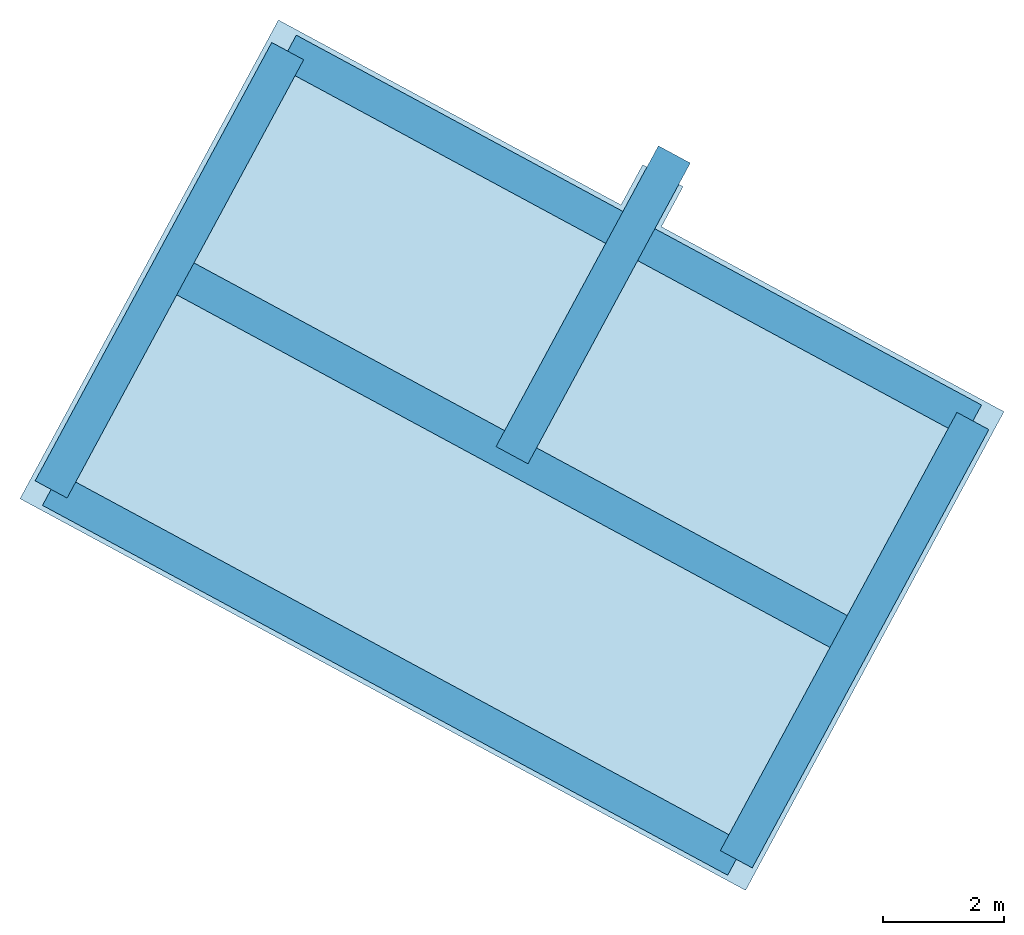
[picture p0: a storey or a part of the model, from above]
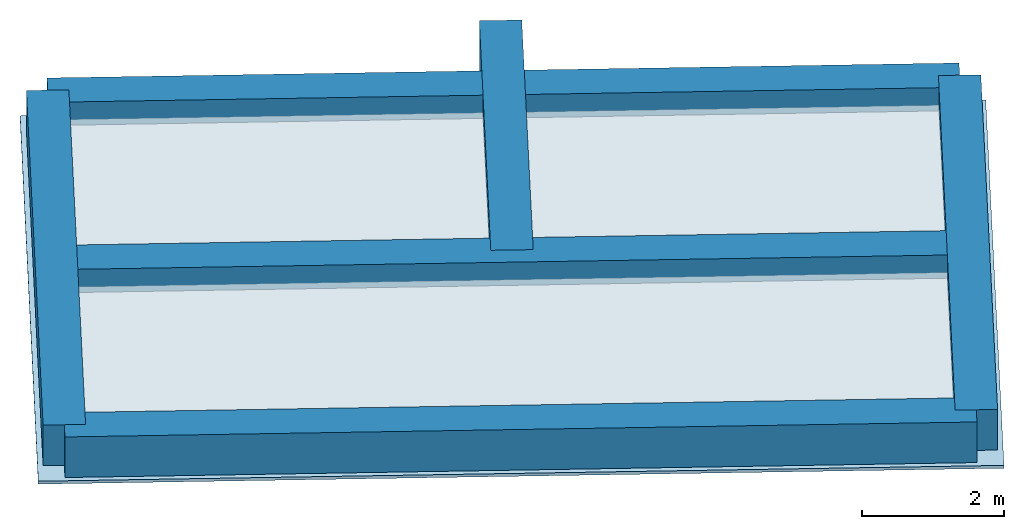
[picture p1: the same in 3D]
Properties of the parts of a building model (IFC2X3), part 1 of 3

# File
Description: ViewDefinition [CoordinationView_V2.0], Option [Elements to export: Visible elements (on all stories)], Option [Partial Structure Display: Entire Model], Option [IFC Domain: All], Option [Structural Function: All Elements], Option [Convert Grid elements: On], Option [Convert IFC Annotations and Archicad 2D elements: Off], Option [Convert 2D symbols of Doors and Windows: Off], Option [Export geometries that Participates in Collision Detection only: Off], Option [Split complex elements: Off], Option [Material Preservation: Never explode], Option [Elements in Solid Element Operations: Extruded/revolved], Option [Elements with junctions: Extruded/revolved without junctions], Option [IFC Model position: Survey Point and Project Origin], Option [Curtain Wall export mode: Single Element], Option [Railing export mode: Single Element], Option [Stair export mode: Single Element], Option [Properties To Export: All properties], Option [Space containment: Off], Option [Geometry to type objects: Off], Option [Element Properties: Off], Option [Building Material Properties: On], Option [Element Parameters: Off], Option [Component Parameters: Off], Option [IFC Base Quantities: Off], Option [Door Window Parameters: On], Option [IFC Space boundaries: Off], Option [Archicad Zone Categories as IFC Space classification data: Off], Option [Element Classifications: On]
File name: I:\_PROJEKT\PQRS\SIWH_18\05_Ausführungsplanung\02 CAD\06 IFC-Modelle\02 TGA\230329\SIWH_18_230329.ifc
Time: 2023-03-29T08:23:47
Author: Kohlrausch Stephan
Organization: Gruppe GME Architekten BDA
Written by: DDS_IFC v3.0
Made in: IFC file generated by Graphisoft Archicad 26.0.0 GER FULL Windows version (IFC add-on version: 4022 GER FULL).
Authorization: Kohlrausch Stephan

# IfcProject, Neubau eines Einfamilienhauses
Description: Katrepeler Landstraße 70A

# IfcSite, Gelände
RefLatitude: 52, 31, 0, 0; RefLongitude: 13, 24, 0, 0; RefElevation: 4.65 m

# IfcBuildingStorey (5)
In: Gebäude
Name | Elevation (m)
Dachaufsicht | 7.905
Staffelgeschoss | 4.55
Erdgeschoss | 0
Gründung | -3.68
Kellergeschoss | -2.98

# IfcBuildingElementProxy: ALLGEMEIN - BAUTEIL (404)
In: Staffelgeschoss
Type - ElementType: SHADING_DEVICE; PredefinedType: USERDEFINED
Classification: Sonnenschutz (Archicad Klassifizierung); Material: ALLGEMEIN - BAUTEIL
Pset_FireRatingProperties - FireResistanceRating: -
AC_Pset_RenovationAndPhasing - Renovation Status: Existing
Material Properties - ALLGEMEIN - BAUTEIL, ThermalConductivity: 0.13; ALLGEMEIN - BAUTEIL, SpecificHeatCapacity: 1600 J/kg/K; ALLGEMEIN - BAUTEIL, MassDensity: 500 kg/m3; ALLGEMEIN - BAUTEIL, Embodied Energy: 13.1 (MJ/kg); ALLGEMEIN - BAUTEIL, Embodied Carbon: 0.64 (kgCO₂/kg); ALLGEMEIN - BAUTEIL, Name: ALLGEMEIN - BAUTEIL; ALLGEMEIN - BAUTEIL, Participates in Collision Detection: yes

# IfcBuildingElementProxy: BO | Dämmung 8+Folie+Estrich 7+Fliese 0,5 | 16cm 170 (8)
In: Staffelgeschoss
Material: Dämmung, hart EPS, Sperrschicht, Folie, Estrich, Kleber, Beton, Leichtbeton
AC_Pset_RenovationAndPhasing - Renovation Status: Existing
Material Properties - Dämmung, hart EPS, ThermalConductivity: 0.042; Dämmung, hart EPS, SpecificHeatCapacity: 1450 J/kg/K; Dämmung, hart EPS, MassDensity: 15 kg/m3; Dämmung, hart EPS, Embodied Energy: 76 (MJ/kg); Dämmung, hart EPS, Embodied Carbon: 3.18 (kgCO₂/kg); Dämmung, hart EPS, Name: Dämmung, hart EPS; Dämmung, hart EPS, Participates in Collision Detection: yes; Sperrschicht, Folie, ThermalConductivity: 0.14; Sperrschicht, Folie, SpecificHeatCapacity: 1000 J/kg/K; Sperrschicht, Folie, MassDensity: 1200 kg/m3; Sperrschicht, Folie, Embodied Energy: 77.2 (MJ/kg); Sperrschicht, Folie, Embodied Carbon: 3.1 (kgCO₂/kg); Sperrschicht, Folie, Name: Sperrschicht, Folie; Sperrschicht, Folie, Participates in Collision Detection: yes; Estrich, ThermalConductivity: 0.8; Estrich, SpecificHeatCapacity: 800 J/kg/K; Estrich, MassDensity: 2300 kg/m3; Estrich, Embodied Energy: 0.92 (MJ/kg); Estrich, Embodied Carbon: 0.15 (kgCO₂/kg); Estrich, Name: Estrich; Estrich, Participates in Collision Detection: yes; Kleber, ThermalConductivity: 0.8; Kleber, SpecificHeatCapacity: 800 J/kg/K; Kleber, MassDensity: 2300 kg/m3; Kleber, Embodied Energy: 0.92 (MJ/kg); Kleber, Embodied Carbon: 0.15 (kgCO₂/kg); Kleber, Name: Kleber; Kleber, Participates in Collision Detection: yes; Beton, Leichtbeton, ThermalConductivity: 0.12; Beton, Leichtbeton, SpecificHeatCapacity: 800 J/kg/K; Beton, Leichtbeton, MassDensity: 450 kg/m3; Beton, Leichtbeton, Embodied Energy: 6.2 (MJ/kg); Beton, Leichtbeton, Embodied Carbon: 0.46 (kgCO₂/kg); Beton, Leichtbeton, Name: Beton, Leichtbeton; Beton, Leichtbeton, Participates in Collision Detection: yes
Name
Decke028
Decke029
Decke041
Decke055
Decke056
Decke057
Decke058
Decke040

# IfcBuildingElementProxy: Gipskarton 15, Decke001
In: Erdgeschoss
Material: Gipskarton
AC_Pset_RenovationAndPhasing - Renovation Status: Existing
Material Properties - Gipskarton, ThermalConductivity: 0.25; Gipskarton, SpecificHeatCapacity: 1000 J/kg/K; Gipskarton, MassDensity: 900 kg/m3; Gipskarton, Embodied Energy: 6.75 (MJ/kg); Gipskarton, Embodied Carbon: 0.39 (kgCO₂/kg); Gipskarton, Name: Gipskarton; Gipskarton, Participates in Collision Detection: yes

# IfcColumn: Beton, Stahlbeton C30/35 D450 (2)
In: Erdgeschoss
Classification: Stütze / Pfeiler (Archicad Klassifizierung); Material: Beton, Stahlbeton C30/35
Pset_ColumnCommon - Slope: 90 deg; FireRating: -; IsExternal: no; LoadBearing: yes; Reference: Beton, Stahlbeton C30/35 D450
AC_Pset_RenovationAndPhasing - Renovation Status: Existing
Material Properties - Beton, Stahlbeton C30/35, ThermalConductivity: 1.35; Beton, Stahlbeton C30/35, SpecificHeatCapacity: 1000 J/kg/K; Beton, Stahlbeton C30/35, MassDensity: 2000 kg/m3; Beton, Stahlbeton C30/35, Embodied Energy: 0.78 (MJ/kg); Beton, Stahlbeton C30/35, Embodied Carbon: 0.113 (kgCO₂/kg); Beton, Stahlbeton C30/35, Name: Beton, Stahlbeton C30/35; Beton, Stahlbeton C30/35, Participates in Collision Detection: yes
Pset_FireRatingProperties - FireResistanceRating: -

# IfcColumn: Metall, Edelstahl D152 (7)
Type - PredefinedType: COLUMN
Classification: Stütze (Archicad Klassifizierung); Material: Metall, Edelstahl
Pset_ColumnCommon - Slope: 90 deg; FireRating: -; IsExternal: no; LoadBearing: yes; Reference: Metall, Edelstahl D152
Pset_FireRatingProperties - FireResistanceRating: -
AC_Pset_RenovationAndPhasing - Renovation Status: Existing
Material Properties - Metall, Edelstahl, ThermalConductivity: 17; Metall, Edelstahl, SpecificHeatCapacity: 460 J/kg/K; Metall, Edelstahl, MassDensity: 7900 kg/m3; Metall, Edelstahl, Embodied Energy: 56.7 (MJ/kg); Metall, Edelstahl, Embodied Carbon: 6.15 (kgCO₂/kg); Metall, Edelstahl, Name: Metall, Edelstahl; Metall, Edelstahl, Participates in Collision Detection: yes
Name | In
4 x Stütze-003 | Erdgeschoss
3 x Stütze-003 | Staffelgeschoss

# IfcColumn: Metall, Edelstahl-Stütze D152 (3)
In: Erdgeschoss
Type - PredefinedType: COLUMN
Classification: Stütze (Archicad Klassifizierung); Material: Metall, Edelstahl-Stütze
Pset_ColumnCommon - Slope: 90 deg; FireRating: -; IsExternal: no; LoadBearing: yes; Reference: Metall, Edelstahl-Stütze D152
Pset_FireRatingProperties - FireResistanceRating: -
Material Properties - Metall, Edelstahl-Stütze, ThermalConductivity: 17; Metall, Edelstahl-Stütze, SpecificHeatCapacity: 460 J/kg/K; Metall, Edelstahl-Stütze, MassDensity: 7900 kg/m3; Metall, Edelstahl-Stütze, Embodied Energy: 56.7 (MJ/kg); Metall, Edelstahl-Stütze, Embodied Carbon: 6.15 (kgCO₂/kg); Metall, Edelstahl-Stütze, Name: Metall, Edelstahl-Stütze; Metall, Edelstahl-Stütze, Participates in Collision Detection: yes
AC_Pset_RenovationAndPhasing - Renovation Status: Existing

# IfcColumn: Metall, Stahl lackiert D152 (7)
In: Staffelgeschoss
Type - PredefinedType: COLUMN
Classification: Stütze (Archicad Klassifizierung); Material: Metall, Stahl lackiert
Pset_ColumnCommon - Slope: 90 deg; FireRating: -; IsExternal: no; LoadBearing: yes; Reference: Metall, Stahl lackiert D152
AC_Pset_RenovationAndPhasing - Renovation Status: Existing
Pset_FireRatingProperties - FireResistanceRating: -
Material Properties - Metall, Stahl lackiert, ThermalConductivity: 50; Metall, Stahl lackiert, SpecificHeatCapacity: 450 J/kg/K; Metall, Stahl lackiert, MassDensity: 7800 kg/m3; Metall, Stahl lackiert, Embodied Energy: 20.1 (MJ/kg); Metall, Stahl lackiert, Embodied Carbon: 1.46 (kgCO₂/kg); Metall, Stahl lackiert, Name: Metall, Stahl lackiert; Metall, Stahl lackiert, Participates in Collision Detection: yes
Name
4 x Stütze-003
3 x Stütze-004

# IfcColumn: _SIWH - Außenstütze1 EG 2395 x 400, Stütze-004
In: Erdgeschoss
Type - PredefinedType: COLUMN
Classification: Stütze (Archicad Klassifizierung); Material: _SIWH - Beton, Stahlbeton
Pset_ColumnCommon - Slope: 90 deg; FireRating: -; IsExternal: yes; LoadBearing: yes; Reference: _SIWH - Außenstütze1 EG 2395 x 400
AC_Pset_RenovationAndPhasing - Renovation Status: Existing
Material Properties - _SIWH - Beton, Stahlbeton, ThermalConductivity: 1.35; _SIWH - Beton, Stahlbeton, SpecificHeatCapacity: 1000 J/kg/K; _SIWH - Beton, Stahlbeton, MassDensity: 2000 kg/m3; _SIWH - Beton, Stahlbeton, Embodied Energy: 0.78 (MJ/kg); _SIWH - Beton, Stahlbeton, Embodied Carbon: 0.113 (kgCO₂/kg); _SIWH - Beton, Stahlbeton, Name: _SIWH - Beton, Stahlbeton; _SIWH - Beton, Stahlbeton, Participates in Collision Detection: yes
Pset_FireRatingProperties - FireResistanceRating: -

# IfcColumn: _SIWH - Beton, Stahlbeton 400 x 2200, Stütze-003
In: Erdgeschoss
Type - PredefinedType: COLUMN
Classification: Stütze (Archicad Klassifizierung); Material: _SIWH - Beton, Stahlbeton
Pset_FireRatingProperties - FireResistanceRating: -
AC_Pset_RenovationAndPhasing - Renovation Status: Existing
Material Properties - _SIWH - Beton, Stahlbeton, ThermalConductivity: 1.35; _SIWH - Beton, Stahlbeton, SpecificHeatCapacity: 1000 J/kg/K; _SIWH - Beton, Stahlbeton, MassDensity: 2000 kg/m3; _SIWH - Beton, Stahlbeton, Embodied Energy: 0.78 (MJ/kg); _SIWH - Beton, Stahlbeton, Embodied Carbon: 0.113 (kgCO₂/kg); _SIWH - Beton, Stahlbeton, Name: _SIWH - Beton, Stahlbeton; _SIWH - Beton, Stahlbeton, Participates in Collision Detection: yes
Pset_ColumnCommon - Slope: 90 deg; FireRating: -; IsExternal: yes; LoadBearing: yes; Reference: _SIWH - Beton, Stahlbeton 400 x 2200

# IfcColumn: _SIWH - Beton, Stahlbeton 400 x 400 (11)
In: Erdgeschoss
Type - PredefinedType: COLUMN
Classification: Stütze (Archicad Klassifizierung); Material: _SIWH - Beton, Stahlbeton
Pset_ColumnCommon - Slope: 90 deg; FireRating: -; IsExternal: yes; LoadBearing: yes; Reference: _SIWH - Beton, Stahlbeton 400 x 400
Pset_FireRatingProperties - FireResistanceRating: -
AC_Pset_RenovationAndPhasing - Renovation Status: Existing
Material Properties - _SIWH - Beton, Stahlbeton, ThermalConductivity: 1.35; _SIWH - Beton, Stahlbeton, SpecificHeatCapacity: 1000 J/kg/K; _SIWH - Beton, Stahlbeton, MassDensity: 2000 kg/m3; _SIWH - Beton, Stahlbeton, Embodied Energy: 0.78 (MJ/kg); _SIWH - Beton, Stahlbeton, Embodied Carbon: 0.113 (kgCO₂/kg); _SIWH - Beton, Stahlbeton, Name: _SIWH - Beton, Stahlbeton; _SIWH - Beton, Stahlbeton, Participates in Collision Detection: yes

# IfcColumn: _SIWH - Luftschicht vertikal D160 (4)
Type - PredefinedType: COLUMN
Classification: Stütze (Archicad Klassifizierung); Material: _SIWH | Metall, Stahl lackiert, _SIWH - Luftschicht vertikal
Pset_ColumnCommon - Slope: 90 deg; FireRating: -; IsExternal: no; LoadBearing: yes; Reference: _SIWH - Luftschicht vertikal D160
Pset_FireRatingProperties - FireResistanceRating: -
AC_Pset_RenovationAndPhasing - Renovation Status: Existing
Material Properties - _SIWH | Metall, Stahl lackiert, ThermalConductivity: 50; _SIWH | Metall, Stahl lackiert, SpecificHeatCapacity: 450 J/kg/K; _SIWH | Metall, Stahl lackiert, MassDensity: 7800 kg/m3; _SIWH | Metall, Stahl lackiert, Embodied Energy: 20.1 (MJ/kg); _SIWH | Metall, Stahl lackiert, Embodied Carbon: 1.46 (kgCO₂/kg); _SIWH | Metall, Stahl lackiert, Name: _SIWH | Metall, Stahl lackiert; _SIWH | Metall, Stahl lackiert, Participates in Collision Detection: yes; _SIWH - Luftschicht vertikal, ThermalConductivity: 0.16; _SIWH - Luftschicht vertikal, SpecificHeatCapacity: 1008 J/kg/K; _SIWH - Luftschicht vertikal, MassDensity: 1.2 kg/m3; _SIWH - Luftschicht vertikal, Embodied Energy: 0 (MJ/kg); _SIWH - Luftschicht vertikal, Embodied Carbon: 0 (kgCO₂/kg); _SIWH - Luftschicht vertikal, Name: _SIWH - Luftschicht vertikal; _SIWH - Luftschicht vertikal, Participates in Collision Detection: no
Name | In
2 x Stütze-003 | Erdgeschoss
2 x Stütze-003 | Staffelgeschoss

# IfcCovering: ALLGEMEIN - BAUTEIL 50, I-Wand036
In: Staffelgeschoss
Type - PredefinedType: CLADDING
Classification: Verkleidung (Archicad Klassifizierung); Material: ALLGEMEIN - BAUTEIL
Pset_CoveringCommon - FireRating: -; Material: ALLGEMEIN - BAUTEIL; TotalThickness: 0.05 m
Pset_FireRatingProperties - FireResistanceRating: -
Material Properties - ALLGEMEIN - BAUTEIL, ThermalConductivity: 0.13; ALLGEMEIN - BAUTEIL, SpecificHeatCapacity: 1600 J/kg/K; ALLGEMEIN - BAUTEIL, MassDensity: 500 kg/m3; ALLGEMEIN - BAUTEIL, Embodied Energy: 13.1 (MJ/kg); ALLGEMEIN - BAUTEIL, Embodied Carbon: 0.64 (kgCO₂/kg); ALLGEMEIN - BAUTEIL, Name: ALLGEMEIN - BAUTEIL; ALLGEMEIN - BAUTEIL, Participates in Collision Detection: yes
AC_Pset_RenovationAndPhasing - Renovation Status: Existing

# IfcCovering: Dämmung, hart Mineralwolle (6)
Type - PredefinedType: INSULATION
Classification: Dämmung (Archicad Klassifizierung); Material: Dämmung, hart Mineralwolle
Pset_CoveringCommon - FireRating: -; Material: Dämmung, hart Mineralwolle
Pset_FireRatingProperties - FireResistanceRating: -
AC_Pset_RenovationAndPhasing - Renovation Status: Existing
Material Properties - Dämmung, hart Mineralwolle, ThermalConductivity: 0.036; Dämmung, hart Mineralwolle, SpecificHeatCapacity: 840 J/kg/K; Dämmung, hart Mineralwolle, MassDensity: 115 kg/m3; Dämmung, hart Mineralwolle, Embodied Energy: 21.4 (MJ/kg); Dämmung, hart Mineralwolle, Embodied Carbon: 1.69 (kgCO₂/kg); Dämmung, hart Mineralwolle, Name: Dämmung, hart Mineralwolle; Dämmung, hart Mineralwolle, Participates in Collision Detection: yes
Name | In
4 x Freifläche-006 | Staffelgeschoss
Freifläche-005 | Staffelgeschoss
Freifläche-004 | Dachaufsicht

# IfcCovering: Gipskarton 15 (2)
Type - PredefinedType: CEILING
Classification: Abgehängte Decke / Deckenbekleidung (Archicad Klassifizierung); Material: Gipskarton
Pset_CoveringCommon - FireRating: -; Material: Gipskarton; TotalThickness: 0.015 m
Pset_FireRatingProperties - FireResistanceRating: -
AC_Pset_RenovationAndPhasing - Renovation Status: Existing
Material Properties - Gipskarton, ThermalConductivity: 0.25; Gipskarton, SpecificHeatCapacity: 1000 J/kg/K; Gipskarton, MassDensity: 900 kg/m3; Gipskarton, Embodied Energy: 6.75 (MJ/kg); Gipskarton, Embodied Carbon: 0.39 (kgCO₂/kg); Gipskarton, Name: Gipskarton; Gipskarton, Participates in Collision Detection: yes
Name | In
Decke007 | Erdgeschoss
Decke002 | Staffelgeschoss

# IfcCovering: Holz, Treppenstufe 966, Decke000
In: Erdgeschoss
Type - PredefinedType: FLOORING
Classification: Fußbodenaufbau (Archicad Klassifizierung); Material: Holz, Treppenstufe
Pset_CoveringCommon - FireRating: -; Material: Holz, Treppenstufe; TotalThickness: 0.965504 m
Pset_FireRatingProperties - FireResistanceRating: -
Material Properties - Holz, Treppenstufe, ThermalConductivity: 0.09; Holz, Treppenstufe, SpecificHeatCapacity: 1600 J/kg/K; Holz, Treppenstufe, MassDensity: 300 kg/m3; Holz, Treppenstufe, Embodied Energy: 11.9 (MJ/kg); Holz, Treppenstufe, Embodied Carbon: 0.52 (kgCO₂/kg); Holz, Treppenstufe, Name: Holz, Treppenstufe; Holz, Treppenstufe, Participates in Collision Detection: yes
AC_Pset_RenovationAndPhasing - Renovation Status: Existing

# IfcCovering: _SIWH - Abgehängte Decke Arkade 25 (2)
In: Erdgeschoss
Type - PredefinedType: CEILING
Classification: Abgehängte Decke / Deckenbekleidung (Archicad Klassifizierung); Material: _SIWH - Abgehängte Decke Arkade
Pset_CoveringCommon - FireRating: -; Material: _SIWH - Abgehängte Decke Arkade; TotalThickness: 0.025 m
Pset_FireRatingProperties - FireResistanceRating: -
AC_Pset_RenovationAndPhasing - Renovation Status: Existing
Material Properties - _SIWH - Abgehängte Decke Arkade, ThermalConductivity: 0.13; _SIWH - Abgehängte Decke Arkade, SpecificHeatCapacity: 1600 J/kg/K; _SIWH - Abgehängte Decke Arkade, MassDensity: 500 kg/m3; _SIWH - Abgehängte Decke Arkade, Embodied Energy: 13.1 (MJ/kg); _SIWH - Abgehängte Decke Arkade, Embodied Carbon: 0.64 (kgCO₂/kg); _SIWH - Abgehängte Decke Arkade, Name: _SIWH - Abgehängte Decke Arkade; _SIWH - Abgehängte Decke Arkade, Participates in Collision Detection: yes
Name
Decke016
Decke015

# IfcCovering: _SIWH - Attika1 Achse3 EG 440 x 865, A-Wand054
In: Staffelgeschoss
Type - PredefinedType: INSULATION
Classification: Dämmung (Archicad Klassifizierung); Material: _SIWH - Dämmung, weich Mineralwolle, _SIWH - Dämmung, hart Mineralwolle
Pset_CoveringCommon - FireRating: -; Material: _SIWH - Attika1 Achse3 EG; TotalThickness: 0.44 m
Pset_FireRatingProperties - FireResistanceRating: -
AC_Pset_RenovationAndPhasing - Renovation Status: Existing
Material Properties - _SIWH - Dämmung, weich Mineralwolle, ThermalConductivity: 0.037; _SIWH - Dämmung, weich Mineralwolle, SpecificHeatCapacity: 840 J/kg/K; _SIWH - Dämmung, weich Mineralwolle, MassDensity: 40 kg/m3; _SIWH - Dämmung, weich Mineralwolle, Embodied Energy: 14.3 (MJ/kg); _SIWH - Dämmung, weich Mineralwolle, Embodied Carbon: 1.08 (kgCO₂/kg); _SIWH - Dämmung, weich Mineralwolle, Name: _SIWH - Dämmung, weich Mineralwolle; _SIWH - Dämmung, weich Mineralwolle, Participates in Collision Detection: yes; _SIWH - Dämmung, hart Mineralwolle, ThermalConductivity: 0.036; _SIWH - Dämmung, hart Mineralwolle, SpecificHeatCapacity: 840 J/kg/K; _SIWH - Dämmung, hart Mineralwolle, MassDensity: 115 kg/m3; _SIWH - Dämmung, hart Mineralwolle, Embodied Energy: 21.4 (MJ/kg); _SIWH - Dämmung, hart Mineralwolle, Embodied Carbon: 1.69 (kgCO₂/kg); _SIWH - Dämmung, hart Mineralwolle, Name: _SIWH - Dämmung, hart Mineralwolle; _SIWH - Dämmung, hart Mineralwolle, Participates in Collision Detection: yes

# IfcCovering: _SIWH - Attika1 AchseB EG 440 x 865 (2)
In: Staffelgeschoss
Type - PredefinedType: INSULATION
Classification: Dämmung (Archicad Klassifizierung); Material: _SIWH - Dämmung, weich Mineralwolle, _SIWH - Dämmung, hart Mineralwolle
Pset_CoveringCommon - FireRating: -; Material: _SIWH - Attika1 AchseB EG; TotalThickness: 0.44 m
Pset_FireRatingProperties - FireResistanceRating: -
AC_Pset_RenovationAndPhasing - Renovation Status: Existing
Material Properties - _SIWH - Dämmung, weich Mineralwolle, ThermalConductivity: 0.037; _SIWH - Dämmung, weich Mineralwolle, SpecificHeatCapacity: 840 J/kg/K; _SIWH - Dämmung, weich Mineralwolle, MassDensity: 40 kg/m3; _SIWH - Dämmung, weich Mineralwolle, Embodied Energy: 14.3 (MJ/kg); _SIWH - Dämmung, weich Mineralwolle, Embodied Carbon: 1.08 (kgCO₂/kg); _SIWH - Dämmung, weich Mineralwolle, Name: _SIWH - Dämmung, weich Mineralwolle; _SIWH - Dämmung, weich Mineralwolle, Participates in Collision Detection: yes; _SIWH - Dämmung, hart Mineralwolle, ThermalConductivity: 0.036; _SIWH - Dämmung, hart Mineralwolle, SpecificHeatCapacity: 840 J/kg/K; _SIWH - Dämmung, hart Mineralwolle, MassDensity: 115 kg/m3; _SIWH - Dämmung, hart Mineralwolle, Embodied Energy: 21.4 (MJ/kg); _SIWH - Dämmung, hart Mineralwolle, Embodied Carbon: 1.69 (kgCO₂/kg); _SIWH - Dämmung, hart Mineralwolle, Name: _SIWH - Dämmung, hart Mineralwolle; _SIWH - Dämmung, hart Mineralwolle, Participates in Collision Detection: yes
Name
A-Wand057
A-Wand059

# IfcCovering: _SIWH - Attika2 Achse3 EG 440 x 585, A-Wand056
In: Staffelgeschoss
Type - PredefinedType: INSULATION
Classification: Dämmung (Archicad Klassifizierung); Material: _SIWH - Dämmung, weich Mineralwolle, _SIWH - Dämmung, hart Mineralwolle
Pset_CoveringCommon - FireRating: -; Material: _SIWH - Attika2 Achse3 EG; TotalThickness: 0.44 m
Pset_FireRatingProperties - FireResistanceRating: -
AC_Pset_RenovationAndPhasing - Renovation Status: Existing
Material Properties - _SIWH - Dämmung, weich Mineralwolle, ThermalConductivity: 0.037; _SIWH - Dämmung, weich Mineralwolle, SpecificHeatCapacity: 840 J/kg/K; _SIWH - Dämmung, weich Mineralwolle, MassDensity: 40 kg/m3; _SIWH - Dämmung, weich Mineralwolle, Embodied Energy: 14.3 (MJ/kg); _SIWH - Dämmung, weich Mineralwolle, Embodied Carbon: 1.08 (kgCO₂/kg); _SIWH - Dämmung, weich Mineralwolle, Name: _SIWH - Dämmung, weich Mineralwolle; _SIWH - Dämmung, weich Mineralwolle, Participates in Collision Detection: yes; _SIWH - Dämmung, hart Mineralwolle, ThermalConductivity: 0.036; _SIWH - Dämmung, hart Mineralwolle, SpecificHeatCapacity: 840 J/kg/K; _SIWH - Dämmung, hart Mineralwolle, MassDensity: 115 kg/m3; _SIWH - Dämmung, hart Mineralwolle, Embodied Energy: 21.4 (MJ/kg); _SIWH - Dämmung, hart Mineralwolle, Embodied Carbon: 1.69 (kgCO₂/kg); _SIWH - Dämmung, hart Mineralwolle, Name: _SIWH - Dämmung, hart Mineralwolle; _SIWH - Dämmung, hart Mineralwolle, Participates in Collision Detection: yes

# IfcCovering: _SIWH - Attika3 Achse3 EG 260 x 385, A-Wand055
In: Staffelgeschoss
Type - PredefinedType: INSULATION
Classification: Dämmung (Archicad Klassifizierung); Material: _SIWH - Dämmung, hart Mineralwolle
Pset_CoveringCommon - FireRating: -; Material: _SIWH - Attika3 Achse3 EG; TotalThickness: 0.26 m
Pset_FireRatingProperties - FireResistanceRating: -
AC_Pset_RenovationAndPhasing - Renovation Status: Existing
Material Properties - _SIWH - Dämmung, hart Mineralwolle, ThermalConductivity: 0.036; _SIWH - Dämmung, hart Mineralwolle, SpecificHeatCapacity: 840 J/kg/K; _SIWH - Dämmung, hart Mineralwolle, MassDensity: 115 kg/m3; _SIWH - Dämmung, hart Mineralwolle, Embodied Energy: 21.4 (MJ/kg); _SIWH - Dämmung, hart Mineralwolle, Embodied Carbon: 1.69 (kgCO₂/kg); _SIWH - Dämmung, hart Mineralwolle, Name: _SIWH - Dämmung, hart Mineralwolle; _SIWH - Dämmung, hart Mineralwolle, Participates in Collision Detection: yes

# IfcCovering: _SIWH - Attika4 Achse3 EG 320 x 385, A-Wand058
In: Staffelgeschoss
Type - PredefinedType: INSULATION
Classification: Dämmung (Archicad Klassifizierung); Material: _SIWH - Dämmung, hart Mineralwolle
Pset_CoveringCommon - FireRating: -; Material: _SIWH - Attika4 Achse3 EG; TotalThickness: 0.32 m
Pset_FireRatingProperties - FireResistanceRating: -
AC_Pset_RenovationAndPhasing - Renovation Status: Existing
Material Properties - _SIWH - Dämmung, hart Mineralwolle, ThermalConductivity: 0.036; _SIWH - Dämmung, hart Mineralwolle, SpecificHeatCapacity: 840 J/kg/K; _SIWH - Dämmung, hart Mineralwolle, MassDensity: 115 kg/m3; _SIWH - Dämmung, hart Mineralwolle, Embodied Energy: 21.4 (MJ/kg); _SIWH - Dämmung, hart Mineralwolle, Embodied Carbon: 1.69 (kgCO₂/kg); _SIWH - Dämmung, hart Mineralwolle, Name: _SIWH - Dämmung, hart Mineralwolle; _SIWH - Dämmung, hart Mineralwolle, Participates in Collision Detection: yes

# IfcCovering: _SIWH - Attikablech1 Achse3+B EG 660 x 115 (2)
In: Staffelgeschoss
Type - PredefinedType: ROOFING
Classification: Dachdeckung (Archicad Klassifizierung); Material: _SIWH - Holz, Bauholz, _SIWH - Metall, Aluminium
Pset_FireRatingProperties - FireResistanceRating: -
AC_Pset_RenovationAndPhasing - Renovation Status: Existing
Material Properties - _SIWH - Holz, Bauholz, ThermalConductivity: 0.13; _SIWH - Holz, Bauholz, SpecificHeatCapacity: 1600 J/kg/K; _SIWH - Holz, Bauholz, MassDensity: 500 kg/m3; _SIWH - Holz, Bauholz, Embodied Energy: 6.95 (MJ/kg); _SIWH - Holz, Bauholz, Embodied Carbon: 0.29 (kgCO₂/kg); _SIWH - Holz, Bauholz, Name: _SIWH - Holz, Bauholz; _SIWH - Holz, Bauholz, Participates in Collision Detection: yes; _SIWH - Metall, Aluminium, ThermalConductivity: 160; _SIWH - Metall, Aluminium, SpecificHeatCapacity: 880 J/kg/K; _SIWH - Metall, Aluminium, MassDensity: 2800 kg/m3; _SIWH - Metall, Aluminium, Embodied Energy: 155 (MJ/kg); _SIWH - Metall, Aluminium, Embodied Carbon: 9.16 (kgCO₂/kg); _SIWH - Metall, Aluminium, Name: _SIWH - Metall, Aluminium; _SIWH - Metall, Aluminium, Participates in Collision Detection: yes
Pset_CoveringCommon - FireRating: -; Material: _SIWH - Attikablech1 Achse3+B EG; TotalThickness: 0.66 m

# IfcCovering: _SIWH - Attikablech3 Achse3+4' EG 380 x 92 (2)
In: Staffelgeschoss
Type - PredefinedType: ROOFING
Classification: Dachdeckung (Archicad Klassifizierung); Material: _SIWH - Holz, Bauholz, _SIWH - Metall, Aluminium
Pset_CoveringCommon - FireRating: -; Material: _SIWH - Attikablech3 Achse3+4' EG; TotalThickness: 0.38 m
Pset_FireRatingProperties - FireResistanceRating: -
AC_Pset_RenovationAndPhasing - Renovation Status: Existing
Material Properties - _SIWH - Holz, Bauholz, ThermalConductivity: 0.13; _SIWH - Holz, Bauholz, SpecificHeatCapacity: 1600 J/kg/K; _SIWH - Holz, Bauholz, MassDensity: 500 kg/m3; _SIWH - Holz, Bauholz, Embodied Energy: 6.95 (MJ/kg); _SIWH - Holz, Bauholz, Embodied Carbon: 0.29 (kgCO₂/kg); _SIWH - Holz, Bauholz, Name: _SIWH - Holz, Bauholz; _SIWH - Holz, Bauholz, Participates in Collision Detection: yes; _SIWH - Metall, Aluminium, ThermalConductivity: 160; _SIWH - Metall, Aluminium, SpecificHeatCapacity: 880 J/kg/K; _SIWH - Metall, Aluminium, MassDensity: 2800 kg/m3; _SIWH - Metall, Aluminium, Embodied Energy: 155 (MJ/kg); _SIWH - Metall, Aluminium, Embodied Carbon: 9.16 (kgCO₂/kg); _SIWH - Metall, Aluminium, Name: _SIWH - Metall, Aluminium; _SIWH - Metall, Aluminium, Participates in Collision Detection: yes

# IfcCovering: _SIWH - Außendämmung Wand KG 230 x 2305, Unterzug-015
In: Kellergeschoss
Type - PredefinedType: INSULATION
Classification: Dämmung (Archicad Klassifizierung); Material: _SIWH - Dämmung, Perimeterdämmung (3)
Pset_CoveringCommon - FireRating: -; Material: _SIWH - Außendämmung Wand KG
Pset_FireRatingProperties - FireResistanceRating: -
Material Properties - _SIWH - Dämmung, Perimeterdämmung, ThermalConductivity: 0.046; _SIWH - Dämmung, Perimeterdämmung, SpecificHeatCapacity: 900 J/kg/K; _SIWH - Dämmung, Perimeterdämmung, MassDensity: 151.33 kg/m3; _SIWH - Dämmung, Perimeterdämmung, Embodied Energy: 13.5 (MJ/kg); _SIWH - Dämmung, Perimeterdämmung, Embodied Carbon: 0.9 (kgCO₂/kg); _SIWH - Dämmung, Perimeterdämmung, Name: _SIWH - Dämmung, Perimeterdämmung; _SIWH - Dämmung, Perimeterdämmung, Participates in Collision Detection: yes
AC_Pset_RenovationAndPhasing - Renovation Status: Existing

# IfcCovering: _SIWH - Außendämmung Wand KG 230 x 3250 (2)
In: Kellergeschoss
Type - PredefinedType: INSULATION
Classification: Dämmung (Archicad Klassifizierung); Material: _SIWH - Dämmung, Perimeterdämmung (3)
Pset_CoveringCommon - FireRating: -; Material: _SIWH - Außendämmung Wand KG
Pset_FireRatingProperties - FireResistanceRating: -
AC_Pset_RenovationAndPhasing - Renovation Status: Existing
Material Properties - _SIWH - Dämmung, Perimeterdämmung, ThermalConductivity: 0.046; _SIWH - Dämmung, Perimeterdämmung, SpecificHeatCapacity: 900 J/kg/K; _SIWH - Dämmung, Perimeterdämmung, MassDensity: 151.33 kg/m3; _SIWH - Dämmung, Perimeterdämmung, Embodied Energy: 13.5 (MJ/kg); _SIWH - Dämmung, Perimeterdämmung, Embodied Carbon: 0.9 (kgCO₂/kg); _SIWH - Dämmung, Perimeterdämmung, Name: _SIWH - Dämmung, Perimeterdämmung; _SIWH - Dämmung, Perimeterdämmung, Participates in Collision Detection: yes
Name
Unterzug-016
Unterzug-015

# IfcCovering: _SIWH - Außendämmung Wand KG 230 x 3500 (8)
In: Kellergeschoss
Type - PredefinedType: INSULATION
Classification: Dämmung (Archicad Klassifizierung); Material: _SIWH - Dämmung, Perimeterdämmung (3)
Pset_CoveringCommon - FireRating: -; Material: _SIWH - Außendämmung Wand KG
Pset_FireRatingProperties - FireResistanceRating: -
AC_Pset_RenovationAndPhasing - Renovation Status: Existing
Material Properties - _SIWH - Dämmung, Perimeterdämmung, ThermalConductivity: 0.046; _SIWH - Dämmung, Perimeterdämmung, SpecificHeatCapacity: 900 J/kg/K; _SIWH - Dämmung, Perimeterdämmung, MassDensity: 151.33 kg/m3; _SIWH - Dämmung, Perimeterdämmung, Embodied Energy: 13.5 (MJ/kg); _SIWH - Dämmung, Perimeterdämmung, Embodied Carbon: 0.9 (kgCO₂/kg); _SIWH - Dämmung, Perimeterdämmung, Name: _SIWH - Dämmung, Perimeterdämmung; _SIWH - Dämmung, Perimeterdämmung, Participates in Collision Detection: yes
Name
5 x Unterzug-015
2 x Unterzug-017
Unterzug-016

# IfcCovering: _SIWH - BO | EG 180, Decke008
In: Erdgeschoss
Type - PredefinedType: FLOORING
Classification: Fußbodenaufbau (Archicad Klassifizierung); Material: ALLGEMEIN - BAUTEIL
Pset_CoveringCommon - FireRating: -; Material: _SIWH - BO | EG; TotalThickness: 0.18 m
Pset_FireRatingProperties - FireResistanceRating: -
AC_Pset_RenovationAndPhasing - Renovation Status: Existing
Material Properties - ALLGEMEIN - BAUTEIL, ThermalConductivity: 0.13; ALLGEMEIN - BAUTEIL, SpecificHeatCapacity: 1600 J/kg/K; ALLGEMEIN - BAUTEIL, MassDensity: 500 kg/m3; ALLGEMEIN - BAUTEIL, Embodied Energy: 13.1 (MJ/kg); ALLGEMEIN - BAUTEIL, Embodied Carbon: 0.64 (kgCO₂/kg); ALLGEMEIN - BAUTEIL, Name: ALLGEMEIN - BAUTEIL; ALLGEMEIN - BAUTEIL, Participates in Collision Detection: yes

# IfcCovering: _SIWH - BO | Perimeterdämmung 10 | 10cm 100 (3)
In: Gründung
Type - PredefinedType: INSULATION
Classification: Dämmung (Archicad Klassifizierung); Material: _SIWH - Dämmung, Perimeterdämmung
Pset_CoveringCommon - FireRating: -; Material: _SIWH - BO | Perimeterdämmung 10 | 10cm; TotalThickness: 0.1 m
Pset_FireRatingProperties - FireResistanceRating: -
AC_Pset_RenovationAndPhasing - Renovation Status: Existing
Material Properties - _SIWH - Dämmung, Perimeterdämmung, ThermalConductivity: 0.046; _SIWH - Dämmung, Perimeterdämmung, SpecificHeatCapacity: 900 J/kg/K; _SIWH - Dämmung, Perimeterdämmung, MassDensity: 151.33 kg/m3; _SIWH - Dämmung, Perimeterdämmung, Embodied Energy: 13.5 (MJ/kg); _SIWH - Dämmung, Perimeterdämmung, Embodied Carbon: 0.9 (kgCO₂/kg); _SIWH - Dämmung, Perimeterdämmung, Name: _SIWH - Dämmung, Perimeterdämmung; _SIWH - Dämmung, Perimeterdämmung, Participates in Collision Detection: yes
Name
Decke035
Decke034
Decke033

# IfcCovering: _SIWH - BO | SG 190, Decke005
In: Staffelgeschoss
Type - PredefinedType: FLOORING
Classification: Fußbodenaufbau (Archicad Klassifizierung); Material: ALLGEMEIN - BAUTEIL
Pset_CoveringCommon - FireRating: -; Material: _SIWH - BO | SG; TotalThickness: 0.19 m
Pset_FireRatingProperties - FireResistanceRating: -
AC_Pset_RenovationAndPhasing - Renovation Status: Existing
Material Properties - ALLGEMEIN - BAUTEIL, ThermalConductivity: 0.13; ALLGEMEIN - BAUTEIL, SpecificHeatCapacity: 1600 J/kg/K; ALLGEMEIN - BAUTEIL, MassDensity: 500 kg/m3; ALLGEMEIN - BAUTEIL, Embodied Energy: 13.1 (MJ/kg); ALLGEMEIN - BAUTEIL, Embodied Carbon: 0.64 (kgCO₂/kg); ALLGEMEIN - BAUTEIL, Name: ALLGEMEIN - BAUTEIL; ALLGEMEIN - BAUTEIL, Participates in Collision Detection: yes

# IfcCovering: _SIWH - Belag Terrasse SG 40, Decke052
In: Staffelgeschoss
Type - PredefinedType: ROOFING
Classification: Dachdeckung (Archicad Klassifizierung); Material: _SIWH - Belag Terrasse SG
Pset_CoveringCommon - FireRating: -; Material: _SIWH - Belag Terrasse SG; TotalThickness: 0.04 m
Pset_FireRatingProperties - FireResistanceRating: -
AC_Pset_RenovationAndPhasing - Renovation Status: Existing
Material Properties - _SIWH - Belag Terrasse SG, ThermalConductivity: 2.3; _SIWH - Belag Terrasse SG, SpecificHeatCapacity: 1000 J/kg/K; _SIWH - Belag Terrasse SG, MassDensity: 2600 kg/m3; _SIWH - Belag Terrasse SG, Embodied Energy: 1 (MJ/kg); _SIWH - Belag Terrasse SG, Embodied Carbon: 0.06 (kgCO₂/kg); _SIWH - Belag Terrasse SG, Name: _SIWH - Belag Terrasse SG; _SIWH - Belag Terrasse SG, Participates in Collision Detection: yes

# IfcCovering: _SIWH - DE | Dämmung 8 | 8cm 80, Decke018
In: Erdgeschoss
Type - PredefinedType: INSULATION
Classification: Dämmung (Archicad Klassifizierung); Material: _SIWH - Dämmung, weich Mineralwolle
Pset_CoveringCommon - FireRating: -; Material: _SIWH - DE | Dämmung 8 | 8cm; TotalThickness: 0.08 m
AC_Pset_RenovationAndPhasing - Renovation Status: Existing
Material Properties - _SIWH - Dämmung, weich Mineralwolle, ThermalConductivity: 0.037; _SIWH - Dämmung, weich Mineralwolle, SpecificHeatCapacity: 840 J/kg/K; _SIWH - Dämmung, weich Mineralwolle, MassDensity: 40 kg/m3; _SIWH - Dämmung, weich Mineralwolle, Embodied Energy: 14.3 (MJ/kg); _SIWH - Dämmung, weich Mineralwolle, Embodied Carbon: 1.08 (kgCO₂/kg); _SIWH - Dämmung, weich Mineralwolle, Name: _SIWH - Dämmung, weich Mineralwolle; _SIWH - Dämmung, weich Mineralwolle, Participates in Collision Detection: yes
Pset_FireRatingProperties - FireResistanceRating: -

# IfcCovering: _SIWH - Dämmung, hart Mineralwolle 100 (3)
In: Staffelgeschoss
Type - PredefinedType: INSULATION
Classification: Dämmung (Archicad Klassifizierung); Material: _SIWH - Dämmung, hart Mineralwolle
Pset_CoveringCommon - FireRating: -; Material: _SIWH - Dämmung, hart Mineralwolle; TotalThickness: 0.1 m
Pset_FireRatingProperties - FireResistanceRating: -
Material Properties - _SIWH - Dämmung, hart Mineralwolle, ThermalConductivity: 0.036; _SIWH - Dämmung, hart Mineralwolle, SpecificHeatCapacity: 840 J/kg/K; _SIWH - Dämmung, hart Mineralwolle, MassDensity: 115 kg/m3; _SIWH - Dämmung, hart Mineralwolle, Embodied Energy: 21.4 (MJ/kg); _SIWH - Dämmung, hart Mineralwolle, Embodied Carbon: 1.69 (kgCO₂/kg); _SIWH - Dämmung, hart Mineralwolle, Name: _SIWH - Dämmung, hart Mineralwolle; _SIWH - Dämmung, hart Mineralwolle, Participates in Collision Detection: yes
AC_Pset_RenovationAndPhasing - Renovation Status: Existing
Name
Decke012
Decke011
Decke022

# IfcCovering: _SIWH - Dämmung, hart Mineralwolle 140 (2)
Type - PredefinedType: INSULATION
Classification: Dämmung (Archicad Klassifizierung); Material: _SIWH - Dämmung, hart Mineralwolle
Pset_CoveringCommon - FireRating: -; Material: _SIWH - Dämmung, hart Mineralwolle; TotalThickness: 0.14 m
Pset_FireRatingProperties - FireResistanceRating: -
AC_Pset_RenovationAndPhasing - Renovation Status: Existing
Material Properties - _SIWH - Dämmung, hart Mineralwolle, ThermalConductivity: 0.036; _SIWH - Dämmung, hart Mineralwolle, SpecificHeatCapacity: 840 J/kg/K; _SIWH - Dämmung, hart Mineralwolle, MassDensity: 115 kg/m3; _SIWH - Dämmung, hart Mineralwolle, Embodied Energy: 21.4 (MJ/kg); _SIWH - Dämmung, hart Mineralwolle, Embodied Carbon: 1.69 (kgCO₂/kg); _SIWH - Dämmung, hart Mineralwolle, Name: _SIWH - Dämmung, hart Mineralwolle; _SIWH - Dämmung, hart Mineralwolle, Participates in Collision Detection: yes
Name | In
Decke014 | Staffelgeschoss
Decke032 | Dachaufsicht

# IfcCovering: _SIWH - Dämmung, hart Mineralwolle 150, Decke023
In: Staffelgeschoss
Type - PredefinedType: INSULATION
Classification: Dämmung (Archicad Klassifizierung); Material: _SIWH - Dämmung, hart Mineralwolle
Pset_CoveringCommon - FireRating: -; Material: _SIWH - Dämmung, hart Mineralwolle; TotalThickness: 0.15 m
AC_Pset_RenovationAndPhasing - Renovation Status: Existing
Pset_FireRatingProperties - FireResistanceRating: -
Material Properties - _SIWH - Dämmung, hart Mineralwolle, ThermalConductivity: 0.036; _SIWH - Dämmung, hart Mineralwolle, SpecificHeatCapacity: 840 J/kg/K; _SIWH - Dämmung, hart Mineralwolle, MassDensity: 115 kg/m3; _SIWH - Dämmung, hart Mineralwolle, Embodied Energy: 21.4 (MJ/kg); _SIWH - Dämmung, hart Mineralwolle, Embodied Carbon: 1.69 (kgCO₂/kg); _SIWH - Dämmung, hart Mineralwolle, Name: _SIWH - Dämmung, hart Mineralwolle; _SIWH - Dämmung, hart Mineralwolle, Participates in Collision Detection: yes

# IfcCovering: _SIWH - Dämmung, hart Mineralwolle 275 (2)
In: Staffelgeschoss
Type - PredefinedType: INSULATION
Classification: Dämmung (Archicad Klassifizierung); Material: _SIWH - Dämmung, hart Mineralwolle
Pset_CoveringCommon - FireRating: -; Material: _SIWH - Dämmung, hart Mineralwolle; TotalThickness: 0.275 m
Pset_FireRatingProperties - FireResistanceRating: -
AC_Pset_RenovationAndPhasing - Renovation Status: Existing
Material Properties - _SIWH - Dämmung, hart Mineralwolle, ThermalConductivity: 0.036; _SIWH - Dämmung, hart Mineralwolle, SpecificHeatCapacity: 840 J/kg/K; _SIWH - Dämmung, hart Mineralwolle, MassDensity: 115 kg/m3; _SIWH - Dämmung, hart Mineralwolle, Embodied Energy: 21.4 (MJ/kg); _SIWH - Dämmung, hart Mineralwolle, Embodied Carbon: 1.69 (kgCO₂/kg); _SIWH - Dämmung, hart Mineralwolle, Name: _SIWH - Dämmung, hart Mineralwolle; _SIWH - Dämmung, hart Mineralwolle, Participates in Collision Detection: yes
Name
Decke018
Decke019

# IfcCovering: _SIWH - Dämmung, hart Mineralwolle 60 (4)
Type - PredefinedType: INSULATION
Classification: Dämmung (Archicad Klassifizierung); Material: _SIWH - Dämmung, hart Mineralwolle
Pset_CoveringCommon - FireRating: -; Material: _SIWH - Dämmung, hart Mineralwolle; TotalThickness: 0.06 m
AC_Pset_RenovationAndPhasing - Renovation Status: Existing
Material Properties - _SIWH - Dämmung, hart Mineralwolle, ThermalConductivity: 0.036; _SIWH - Dämmung, hart Mineralwolle, SpecificHeatCapacity: 840 J/kg/K; _SIWH - Dämmung, hart Mineralwolle, MassDensity: 115 kg/m3; _SIWH - Dämmung, hart Mineralwolle, Embodied Energy: 21.4 (MJ/kg); _SIWH - Dämmung, hart Mineralwolle, Embodied Carbon: 1.69 (kgCO₂/kg); _SIWH - Dämmung, hart Mineralwolle, Name: _SIWH - Dämmung, hart Mineralwolle; _SIWH - Dämmung, hart Mineralwolle, Participates in Collision Detection: yes
Pset_FireRatingProperties - FireResistanceRating: -
Name | In
Decke017 | Erdgeschoss
2 x A-Wand035 | Erdgeschoss
Decke017 | Staffelgeschoss

# IfcCovering: _SIWH - Dämmung, weich Mineralwolle 180, A-Wand060
In: Staffelgeschoss
Type - PredefinedType: INSULATION
Classification: Dämmung (Archicad Klassifizierung); Material: _SIWH - Dämmung, weich Mineralwolle
Pset_CoveringCommon - FireRating: -; Material: _SIWH - Dämmung, weich Mineralwolle; TotalThickness: 0.18 m
Pset_FireRatingProperties - FireResistanceRating: -
AC_Pset_RenovationAndPhasing - Renovation Status: Existing
Material Properties - _SIWH - Dämmung, weich Mineralwolle, ThermalConductivity: 0.037; _SIWH - Dämmung, weich Mineralwolle, SpecificHeatCapacity: 840 J/kg/K; _SIWH - Dämmung, weich Mineralwolle, MassDensity: 40 kg/m3; _SIWH - Dämmung, weich Mineralwolle, Embodied Energy: 14.3 (MJ/kg); _SIWH - Dämmung, weich Mineralwolle, Embodied Carbon: 1.08 (kgCO₂/kg); _SIWH - Dämmung, weich Mineralwolle, Name: _SIWH - Dämmung, weich Mineralwolle; _SIWH - Dämmung, weich Mineralwolle, Participates in Collision Detection: yes

# IfcCovering: _SIWH - Gründach (2)
In: Staffelgeschoss
Type - PredefinedType: INSULATION
Classification: Dämmung (Archicad Klassifizierung); Material: _SIWH - Gründach
Pset_CoveringCommon - FireRating: -; Material: _SIWH - Gründach
Pset_FireRatingProperties - FireResistanceRating: -
AC_Pset_RenovationAndPhasing - Renovation Status: Existing
Material Properties - _SIWH - Gründach, ThermalConductivity: 0.8; _SIWH - Gründach, SpecificHeatCapacity: 800 J/kg/K; _SIWH - Gründach, MassDensity: 2300 kg/m3; _SIWH - Gründach, Embodied Energy: 0.92 (MJ/kg); _SIWH - Gründach, Embodied Carbon: 0.15 (kgCO₂/kg); _SIWH - Gründach, Name: _SIWH - Gründach; _SIWH - Gründach, Participates in Collision Detection: yes

# IfcCovering: _SIWH - Gründach (3)
Type - PredefinedType: ROOFING
Classification: Dachdeckung (Archicad Klassifizierung); Material: _SIWH - Gründach
Pset_FireRatingProperties - FireResistanceRating: -
AC_Pset_RenovationAndPhasing - Renovation Status: Existing
Material Properties - _SIWH - Gründach, ThermalConductivity: 0.8; _SIWH - Gründach, SpecificHeatCapacity: 800 J/kg/K; _SIWH - Gründach, MassDensity: 2300 kg/m3; _SIWH - Gründach, Embodied Energy: 0.92 (MJ/kg); _SIWH - Gründach, Embodied Carbon: 0.15 (kgCO₂/kg); _SIWH - Gründach, Name: _SIWH - Gründach; _SIWH - Gründach, Participates in Collision Detection: yes
Pset_CoveringCommon - FireRating: -; Material: _SIWH - Gründach
Name | In
2 x Freifläche-006 | Staffelgeschoss
Freifläche-004 | Dachaufsicht

# IfcCovering: _SIWH - Schotter, fein, Freifläche-004
In: Dachaufsicht
Type - PredefinedType: ROOFING
Classification: Dachdeckung (Archicad Klassifizierung); Material: _SIWH - Schotter, fein
Pset_CoveringCommon - FireRating: -; Material: _SIWH - Schotter, fein
Pset_FireRatingProperties - FireResistanceRating: -
AC_Pset_RenovationAndPhasing - Renovation Status: Existing
Material Properties - _SIWH - Schotter, fein, ThermalConductivity: 0.55; _SIWH - Schotter, fein, SpecificHeatCapacity: 1000 J/kg/K; _SIWH - Schotter, fein, MassDensity: 1600 kg/m3; _SIWH - Schotter, fein, Embodied Energy: 1 (MJ/kg); _SIWH - Schotter, fein, Embodied Carbon: 0.06 (kgCO₂/kg); _SIWH - Schotter, fein, Name: _SIWH - Schotter, fein; _SIWH - Schotter, fein, Participates in Collision Detection: yes

# IfcCovering: _SIWH - Schotter, fein 150, Decke053
In: Staffelgeschoss
Type - PredefinedType: ROOFING
Classification: Dachdeckung (Archicad Klassifizierung); Material: _SIWH - Schotter, fein
Pset_CoveringCommon - FireRating: -; Material: _SIWH - Schotter, fein; TotalThickness: 0.15 m
Pset_FireRatingProperties - FireResistanceRating: -
AC_Pset_RenovationAndPhasing - Renovation Status: Existing
Material Properties - _SIWH - Schotter, fein, ThermalConductivity: 0.55; _SIWH - Schotter, fein, SpecificHeatCapacity: 1000 J/kg/K; _SIWH - Schotter, fein, MassDensity: 1600 kg/m3; _SIWH - Schotter, fein, Embodied Energy: 1 (MJ/kg); _SIWH - Schotter, fein, Embodied Carbon: 0.06 (kgCO₂/kg); _SIWH - Schotter, fein, Name: _SIWH - Schotter, fein; _SIWH - Schotter, fein, Participates in Collision Detection: yes

# IfcCovering: _SIWH - Schotter, fein 200, Decke054
In: Staffelgeschoss
Type - PredefinedType: ROOFING
Classification: Dachdeckung (Archicad Klassifizierung); Material: _SIWH - Schotter, fein
Pset_CoveringCommon - FireRating: -; Material: _SIWH - Schotter, fein; TotalThickness: 0.2 m
Pset_FireRatingProperties - FireResistanceRating: -
Material Properties - _SIWH - Schotter, fein, ThermalConductivity: 0.55; _SIWH - Schotter, fein, SpecificHeatCapacity: 1000 J/kg/K; _SIWH - Schotter, fein, MassDensity: 1600 kg/m3; _SIWH - Schotter, fein, Embodied Energy: 1 (MJ/kg); _SIWH - Schotter, fein, Embodied Carbon: 0.06 (kgCO₂/kg); _SIWH - Schotter, fein, Name: _SIWH - Schotter, fein; _SIWH - Schotter, fein, Participates in Collision Detection: yes
AC_Pset_RenovationAndPhasing - Renovation Status: Existing

# IfcCovering: _SIWH - WA | Dämmung 8 | 8cm 80, A-Wand036
In: Erdgeschoss
Type - PredefinedType: INSULATION
Classification: Dämmung (Archicad Klassifizierung); Material: _SIWH - Dämmung, weich Mineralwolle
Pset_FireRatingProperties - FireResistanceRating: -
AC_Pset_RenovationAndPhasing - Renovation Status: Existing
Pset_CoveringCommon - FireRating: -; Material: _SIWH - WA | Dämmung 8 | 8cm; TotalThickness: 0.08 m
Material Properties - _SIWH - Dämmung, weich Mineralwolle, ThermalConductivity: 0.037; _SIWH - Dämmung, weich Mineralwolle, SpecificHeatCapacity: 840 J/kg/K; _SIWH - Dämmung, weich Mineralwolle, MassDensity: 40 kg/m3; _SIWH - Dämmung, weich Mineralwolle, Embodied Energy: 14.3 (MJ/kg); _SIWH - Dämmung, weich Mineralwolle, Embodied Carbon: 1.08 (kgCO₂/kg); _SIWH - Dämmung, weich Mineralwolle, Name: _SIWH - Dämmung, weich Mineralwolle; _SIWH - Dämmung, weich Mineralwolle, Participates in Collision Detection: yes

# IfcCurtainWall: Fassadentyp (12)
Classification: Fassade (Archicad Klassifizierung)
Pset_CurtainWallCommon - FireRating: -
Pset_FireRatingProperties - FireResistanceRating: -
AC_Pset_RenovationAndPhasing - Renovation Status: Existing
Material Properties - Glas, Normalglas-50% durchlässig, ThermalConductivity: 1.4; Glas, Normalglas-50% durchlässig, SpecificHeatCapacity: 750 J/kg/K; Glas, Normalglas-50% durchlässig, MassDensity: 2200 kg/m3; Glas, Normalglas-50% durchlässig, Embodied Energy: 0.85 (MJ/kg); Glas, Normalglas-50% durchlässig, Embodied Carbon: 0.02 (kgCO₂/kg); Glas, Normalglas-50% durchlässig, Name: Glas, Normalglas-50% durchlässig; Glas, Normalglas-50% durchlässig, Participates in Collision Detection: yes; Metall, Stahl lackiert, ThermalConductivity: 50; Metall, Stahl lackiert, SpecificHeatCapacity: 450 J/kg/K; Metall, Stahl lackiert, MassDensity: 7800 kg/m3; Metall, Stahl lackiert, Embodied Energy: 20.1 (MJ/kg); Metall, Stahl lackiert, Embodied Carbon: 1.46 (kgCO₂/kg); Metall, Stahl lackiert, Name: Metall, Stahl lackiert; Metall, Stahl lackiert, Participates in Collision Detection: yes
Name | In | Material | Metall, Aluminium, ThermalConductivity | Metall, Aluminium, SpecificHeatCapacity (J/kg/K) | Metall, Aluminium, MassDensity (kg/m3) | Metall, Aluminium, Embodied Energy | Metall, Aluminium, Embodied Carbon | Metall, Aluminium, Name | Metall, Aluminium, Participates in Collision Detection
Fassade-006 | Erdgeschoss | Glas, Normalglas-50% durchlässig (2), Metall, Stahl lackiert (8), Metall, Aluminium (2) | 160 | 880 | 2800 | 155 (MJ/kg) | 9.16 (kgCO₂/kg) | Metall, Aluminium | yes
Fassade-007 | Erdgeschoss | Glas, Normalglas-50% durchlässig (3), Metall, Aluminium (5), Metall, Edelstahl, Metall, Stahl lackiert (18), Dämmung, hart EPS (2) | 160 | 880 | 2800 | 155 (MJ/kg) | 9.16 (kgCO₂/kg) | Metall, Aluminium | yes | Material Properties - Metall, Edelstahl, ThermalConductivity: 17; Metall, Edelstahl, SpecificHeatCapacity: 460 J/kg/K; Metall, Edelstahl, MassDensity: 7900 kg/m3; Metall, Edelstahl, Embodied Energy: 56.7 (MJ/kg); Metall, Edelstahl, Embodied Carbon: 6.15 (kgCO₂/kg); Metall, Edelstahl, Name: Metall, Edelstahl; Metall, Edelstahl, Participates in Collision Detection: yes; Dämmung, hart EPS, ThermalConductivity: 0.042; Dämmung, hart EPS, SpecificHeatCapacity: 1450 J/kg/K; Dämmung, hart EPS, MassDensity: 15 kg/m3; Dämmung, hart EPS, Embodied Energy: 76 (MJ/kg); Dämmung, hart EPS, Embodied Carbon: 3.18 (kgCO₂/kg); Dämmung, hart EPS, Name: Dämmung, hart EPS; Dämmung, hart EPS, Participates in Collision Detection: yes
Fassade-006 | Erdgeschoss | Metall, Aluminium (3), Glas, Normalglas-50% durchlässig (2), Metall, Edelstahl, Metall, Stahl lackiert (16) | 160 | 880 | 2800 | 155 (MJ/kg) | 9.16 (kgCO₂/kg) | Metall, Aluminium | yes | Material Properties - Metall, Edelstahl, ThermalConductivity: 17; Metall, Edelstahl, SpecificHeatCapacity: 460 J/kg/K; Metall, Edelstahl, MassDensity: 7900 kg/m3; Metall, Edelstahl, Embodied Energy: 56.7 (MJ/kg); Metall, Edelstahl, Embodied Carbon: 6.15 (kgCO₂/kg); Metall, Edelstahl, Name: Metall, Edelstahl; Metall, Edelstahl, Participates in Collision Detection: yes
Fassade-008 | Erdgeschoss | Glas, Normalglas-50% durchlässig (4), Metall, Stahl lackiert (14), Metall, Aluminium (5), Gummi, Dämmung, hart EPS | 160 | 880 | 2800 | 155 (MJ/kg) | 9.16 (kgCO₂/kg) | Metall, Aluminium | yes | Material Properties - Dämmung, hart EPS, ThermalConductivity: 0.042; Dämmung, hart EPS, SpecificHeatCapacity: 1450 J/kg/K; Dämmung, hart EPS, MassDensity: 15 kg/m3; Dämmung, hart EPS, Embodied Energy: 76 (MJ/kg); Dämmung, hart EPS, Embodied Carbon: 3.18 (kgCO₂/kg); Dämmung, hart EPS, Name: Dämmung, hart EPS; Dämmung, hart EPS, Participates in Collision Detection: yes; Gummi, ThermalConductivity: 0.17; Gummi, SpecificHeatCapacity: 1400 J/kg/K; Gummi, MassDensity: 1200 kg/m3; Gummi, Embodied Energy: 110 (MJ/kg); Gummi, Embodied Carbon: 3.8 (kgCO₂/kg); Gummi, Name: Gummi; Gummi, Participates in Collision Detection: yes
Fassade-006 | Erdgeschoss | Glas, Normalglas-50% durchlässig (3), Metall, Stahl lackiert (18), Metall, Aluminium (4) | 160 | 880 | 2800 | 155 (MJ/kg) | 9.16 (kgCO₂/kg) | Metall, Aluminium | yes
Fassade-007 | Erdgeschoss | Metall, Aluminium (4), Glas, Normalglas-50% durchlässig (2), Metall, Edelstahl (2), Dämmung, hart EPS (2), Metall, Stahl lackiert (14) | 160 | 880 | 2800 | 155 (MJ/kg) | 9.16 (kgCO₂/kg) | Metall, Aluminium | yes | Material Properties - Metall, Edelstahl, ThermalConductivity: 17; Metall, Edelstahl, SpecificHeatCapacity: 460 J/kg/K; Metall, Edelstahl, MassDensity: 7900 kg/m3; Metall, Edelstahl, Embodied Energy: 56.7 (MJ/kg); Metall, Edelstahl, Embodied Carbon: 6.15 (kgCO₂/kg); Metall, Edelstahl, Name: Metall, Edelstahl; Metall, Edelstahl, Participates in Collision Detection: yes; Dämmung, hart EPS, ThermalConductivity: 0.042; Dämmung, hart EPS, SpecificHeatCapacity: 1450 J/kg/K; Dämmung, hart EPS, MassDensity: 15 kg/m3; Dämmung, hart EPS, Embodied Energy: 76 (MJ/kg); Dämmung, hart EPS, Embodied Carbon: 3.18 (kgCO₂/kg); Dämmung, hart EPS, Name: Dämmung, hart EPS; Dämmung, hart EPS, Participates in Collision Detection: yes
Fassade-008 | Staffelgeschoss | Glas, Normalglas-50% durchlässig (27), Metall, Aluminium (28), Metall, Edelstahl, Metall, Stahl lackiert (74), Dämmung, hart EPS (2) | 160 | 880 | 2800 | 155 (MJ/kg) | 9.16 (kgCO₂/kg) | Metall, Aluminium | yes | Material Properties - Metall, Edelstahl, ThermalConductivity: 17; Metall, Edelstahl, SpecificHeatCapacity: 460 J/kg/K; Metall, Edelstahl, MassDensity: 7900 kg/m3; Metall, Edelstahl, Embodied Energy: 56.7 (MJ/kg); Metall, Edelstahl, Embodied Carbon: 6.15 (kgCO₂/kg); Metall, Edelstahl, Name: Metall, Edelstahl; Metall, Edelstahl, Participates in Collision Detection: yes; Dämmung, hart EPS, ThermalConductivity: 0.042; Dämmung, hart EPS, SpecificHeatCapacity: 1450 J/kg/K; Dämmung, hart EPS, MassDensity: 15 kg/m3; Dämmung, hart EPS, Embodied Energy: 76 (MJ/kg); Dämmung, hart EPS, Embodied Carbon: 3.18 (kgCO₂/kg); Dämmung, hart EPS, Name: Dämmung, hart EPS; Dämmung, hart EPS, Participates in Collision Detection: yes; Pset_CurtainWallCommon - IsExternal: yes
Fassade-006 | Staffelgeschoss | Glas, Normalglas-50% durchlässig, Metall, Stahl lackiert (6) | Pset_CurtainWallCommon - IsExternal: yes
2 x Fassade-006 | Staffelgeschoss | Glas, Normalglas-50% durchlässig, Metall, Stahl lackiert (6) | Pset_CurtainWallCommon - IsExternal: no
Fassade-008 | Staffelgeschoss | Glas, Normalglas-50% durchlässig (2), Metall, Aluminium (2), Metall, Edelstahl, Metall, Stahl lackiert (15), Dämmung, hart EPS | 160 | 880 | 2800 | 155 (MJ/kg) | 9.16 (kgCO₂/kg) | Metall, Aluminium | yes | Material Properties - Metall, Edelstahl, ThermalConductivity: 17; Metall, Edelstahl, SpecificHeatCapacity: 460 J/kg/K; Metall, Edelstahl, MassDensity: 7900 kg/m3; Metall, Edelstahl, Embodied Energy: 56.7 (MJ/kg); Metall, Edelstahl, Embodied Carbon: 6.15 (kgCO₂/kg); Metall, Edelstahl, Name: Metall, Edelstahl; Metall, Edelstahl, Participates in Collision Detection: yes; Dämmung, hart EPS, ThermalConductivity: 0.042; Dämmung, hart EPS, SpecificHeatCapacity: 1450 J/kg/K; Dämmung, hart EPS, MassDensity: 15 kg/m3; Dämmung, hart EPS, Embodied Energy: 76 (MJ/kg); Dämmung, hart EPS, Embodied Carbon: 3.18 (kgCO₂/kg); Dämmung, hart EPS, Name: Dämmung, hart EPS; Dämmung, hart EPS, Participates in Collision Detection: yes; Pset_CurtainWallCommon - IsExternal: yes
Fassade-006 | Staffelgeschoss | Glas, Normalglas-50% durchlässig (3), Metall, Aluminium (3), Metall, Edelstahl, Metall, Stahl lackiert (15), Dämmung, hart EPS | 160 | 880 | 2800 | 155 (MJ/kg) | 9.16 (kgCO₂/kg) | Metall, Aluminium | yes | Material Properties - Metall, Edelstahl, ThermalConductivity: 17; Metall, Edelstahl, SpecificHeatCapacity: 460 J/kg/K; Metall, Edelstahl, MassDensity: 7900 kg/m3; Metall, Edelstahl, Embodied Energy: 56.7 (MJ/kg); Metall, Edelstahl, Embodied Carbon: 6.15 (kgCO₂/kg); Metall, Edelstahl, Name: Metall, Edelstahl; Metall, Edelstahl, Participates in Collision Detection: yes; Dämmung, hart EPS, ThermalConductivity: 0.042; Dämmung, hart EPS, SpecificHeatCapacity: 1450 J/kg/K; Dämmung, hart EPS, MassDensity: 15 kg/m3; Dämmung, hart EPS, Embodied Energy: 76 (MJ/kg); Dämmung, hart EPS, Embodied Carbon: 3.18 (kgCO₂/kg); Dämmung, hart EPS, Name: Dämmung, hart EPS; Dämmung, hart EPS, Participates in Collision Detection: yes

# IfcDistributionChamberElement: WI | KS 11,5+1-seitig Putz 1,5 | 13cm 130 (3)
In: Staffelgeschoss
Classification: Schacht / Graben / Revisionsschacht (Archicad Klassifizierung); Material: MW Kalksandstein, Verputz, Gips
Material Properties - MW Kalksandstein, ThermalConductivity: 0.93; MW Kalksandstein, SpecificHeatCapacity: 840 J/kg/K; MW Kalksandstein, MassDensity: 1800 kg/m3; MW Kalksandstein, Embodied Energy: 1.2 (MJ/kg); MW Kalksandstein, Embodied Carbon: 0.07 (kgCO₂/kg); MW Kalksandstein, Name: MW Kalksandstein; MW Kalksandstein, Participates in Collision Detection: yes; Verputz, Gips, ThermalConductivity: 0.4; Verputz, Gips, SpecificHeatCapacity: 1000 J/kg/K; Verputz, Gips, MassDensity: 1000 kg/m3; Verputz, Gips, Embodied Energy: 1.6 (MJ/kg); Verputz, Gips, Embodied Carbon: 0.11 (kgCO₂/kg); Verputz, Gips, Name: Verputz, Gips; Verputz, Gips, Participates in Collision Detection: yes
AC_Pset_RenovationAndPhasing - Renovation Status: Existing
Name
I-Wand020
I-Wand021
I-Wand013

# IfcDistributionChamberElement: _SIWH - Lichtschacht 1270x800 870 x 1410, Stütze-004
In: Kellergeschoss
Classification: Schacht / Graben / Revisionsschacht (Archicad Klassifizierung); Material: _SIWH - Dämmung, hart Mineralwolle (2), _SIWH - Beton, Stahlbeton Fertigteil
Material Properties - _SIWH - Dämmung, hart Mineralwolle, ThermalConductivity: 0.036; _SIWH - Dämmung, hart Mineralwolle, SpecificHeatCapacity: 840 J/kg/K; _SIWH - Dämmung, hart Mineralwolle, MassDensity: 115 kg/m3; _SIWH - Dämmung, hart Mineralwolle, Embodied Energy: 21.4 (MJ/kg); _SIWH - Dämmung, hart Mineralwolle, Embodied Carbon: 1.69 (kgCO₂/kg); _SIWH - Dämmung, hart Mineralwolle, Name: _SIWH - Dämmung, hart Mineralwolle; _SIWH - Dämmung, hart Mineralwolle, Participates in Collision Detection: yes; _SIWH - Beton, Stahlbeton Fertigteil, ThermalConductivity: 1.15; _SIWH - Beton, Stahlbeton Fertigteil, SpecificHeatCapacity: 1000 J/kg/K; _SIWH - Beton, Stahlbeton Fertigteil, MassDensity: 1800 kg/m3; _SIWH - Beton, Stahlbeton Fertigteil, Embodied Energy: 0.74 (MJ/kg); _SIWH - Beton, Stahlbeton Fertigteil, Embodied Carbon: 0.107 (kgCO₂/kg); _SIWH - Beton, Stahlbeton Fertigteil, Name: _SIWH - Beton, Stahlbeton Fertigteil; _SIWH - Beton, Stahlbeton Fertigteil, Participates in Collision Detection: yes
AC_Pset_RenovationAndPhasing - Renovation Status: Existing

# IfcDoor: Eingang 01 1-Fl 1S 26, Tür-018
In: Erdgeschoss
Type - OperationType: SINGLE_SWING_RIGHT; ParameterTakesPrecedence: no; Sizeable: no
OverallHeight: 3.62 m; OverallWidth: 2.63477 m; Classification: Tür (Archicad Klassifizierung)
Pset_DoorCommon - FireRating: -; GlazingAreaFraction: 4.86465; SmokeStop: no; IsExternal: yes
Pset_FireRatingProperties - FireResistanceRating: -
AC_Pset_RenovationAndPhasing - Renovation Status: Existing

# IfcDoor: Eingangstür 02 1 22, Tür-017
In: Erdgeschoss
Type - OperationType: SINGLE_SWING_RIGHT; ParameterTakesPrecedence: no; Sizeable: no
OverallHeight: 2.5 m; OverallWidth: 1.135 m; Classification: Tür (Archicad Klassifizierung)
Pset_DoorCommon - FireRating: -; SmokeStop: no; IsExternal: no
Pset_FireRatingProperties - FireResistanceRating: -
AC_Pset_RenovationAndPhasing - Renovation Status: Existing

# IfcDoor: Schiebetür 02 1 22, I-Wand057
In: Staffelgeschoss
Type - OperationType: SLIDING_TO_LEFT; ParameterTakesPrecedence: no; Sizeable: no
OverallHeight: 2.01 m; OverallWidth: 1.01 m; Classification: Tür (Archicad Klassifizierung)
Pset_DoorCommon - FireRating: -; SmokeStop: no; IsExternal: no
Pset_FireRatingProperties - FireResistanceRating: -
AC_Pset_RenovationAndPhasing - Renovation Status: Existing

# IfcDoor: Schiebetür 02 1 22, I-Wand056
In: Staffelgeschoss
Type - OperationType: SLIDING_TO_RIGHT; ParameterTakesPrecedence: no; Sizeable: no
OverallHeight: 2.01 m; OverallWidth: 1.01 m; Classification: Tür (Archicad Klassifizierung)
Pset_DoorCommon - FireRating: -; SmokeStop: no; IsExternal: no
Pset_FireRatingProperties - FireResistanceRating: -
AC_Pset_RenovationAndPhasing - Renovation Status: Existing

# IfcDoor: Schiebetür 02 1-Fl 26 (2)
Type - OperationType: SLIDING_TO_LEFT; ParameterTakesPrecedence: no; Sizeable: no
Classification: Tür (Archicad Klassifizierung)
Pset_DoorCommon - FireRating: -; SmokeStop: no; IsExternal: no
Pset_FireRatingProperties - FireResistanceRating: -
AC_Pset_RenovationAndPhasing - Renovation Status: Existing
Name | In | OverallHeight (m) | OverallWidth (m) | GlazingAreaFraction
I-Wand062 | Erdgeschoss | 2.94 | 1.15 | 2.60263
Tür-017 | Staffelgeschoss | 2.135 | 0.76 | 1.08335

# IfcDoor: Schiebetür 02 1-Fl 26 (3)
In: Erdgeschoss
Type - OperationType: SLIDING_TO_RIGHT; ParameterTakesPrecedence: no; Sizeable: no
Classification: Tür (Archicad Klassifizierung)
Pset_DoorCommon - FireRating: -; SmokeStop: no; IsExternal: no
AC_Pset_RenovationAndPhasing - Renovation Status: Existing
Pset_FireRatingProperties - FireResistanceRating: -
Name | OverallHeight (m) | OverallWidth (m) | GlazingAreaFraction
I-Wand059 | 2.94 | 2.76 | 7.01387
I-Wand061 | 2.94 | 1.26 | 2.90402
I-Wand060 | 2.26 | 1.26 | 2.18329

# IfcDoor: Sektionaltor 22, Tür-016
In: Erdgeschoss
Type - OperationType: USERDEFINED; ParameterTakesPrecedence: no; Sizeable: no
OverallHeight: 3.375 m; OverallWidth: 6 m; Classification: Tür (Archicad Klassifizierung)
Pset_DoorCommon - FireRating: -; SmokeStop: no; IsExternal: no
Pset_FireRatingProperties - FireResistanceRating: -
AC_Pset_RenovationAndPhasing - Renovation Status: Existing

# IfcDoor: Zargentür 1-Fl 22 (5)
Type - OperationType: SINGLE_SWING_LEFT; ParameterTakesPrecedence: no; Sizeable: no
Classification: Tür (Archicad Klassifizierung)
Pset_DoorCommon - FireRating: -; SmokeStop: no; IsExternal: no
Pset_FireRatingProperties - FireResistanceRating: -
AC_Pset_RenovationAndPhasing - Renovation Status: Existing
Name | In | OverallHeight (m) | OverallWidth (m)
I-Wand045 | Kellergeschoss | 2.01 | 0.885
I-Wand049 | Kellergeschoss | 2.01 | 0.885
I-Wand050 | Erdgeschoss | 2.26 | 1.01
I-Wand052 | Erdgeschoss | 2.26 | 1.01
I-Wand055 | Erdgeschoss | 2.26 | 1.01

# IfcDoor: Zargentür 1-Fl 22 (6)
Type - OperationType: SINGLE_SWING_RIGHT; ParameterTakesPrecedence: no; Sizeable: no
Classification: Tür (Archicad Klassifizierung)
Pset_DoorCommon - FireRating: -; SmokeStop: no; IsExternal: no
Pset_FireRatingProperties - FireResistanceRating: -
AC_Pset_RenovationAndPhasing - Renovation Status: Existing
Name | In | OverallHeight (m) | OverallWidth (m)
I-Wand048 | Kellergeschoss | 2.01 | 0.885
I-Wand051 | Erdgeschoss | 2.26 | 1.135
I-Wand053 | Erdgeschoss | 2.26 | 1.01
I-Wand058 | Erdgeschoss | 2.98 | 1.51
I-Wand047 | Staffelgeschoss | 2.135 | 1.135
I-Wand054 | Staffelgeschoss | 2.135 | 1.01

# IfcFlowTerminal: Badewanne rund 22, Objekt-0061
In: Staffelgeschoss
Classification: Sanitäreinrichtung (Archicad Klassifizierung)
AC_Pset_RenovationAndPhasing - Renovation Status: Existing

# IfcFlowTerminal: Duschset 22 (2)
In: Staffelgeschoss
Classification: Sanitäreinrichtung (Archicad Klassifizierung)
AC_Pset_RenovationAndPhasing - Renovation Status: Existing

# IfcFlowTerminal: Kleiderschrank 22, Objekt-0063
In: Staffelgeschoss
Classification: Sanitäreinrichtung (Archicad Klassifizierung)
AC_Pset_RenovationAndPhasing - Renovation Status: Existing

# IfcFlowTerminal: Unterschrank Mehrfach-Schublade 22 (2)
Classification: Sanitäreinrichtung (Archicad Klassifizierung)
AC_Pset_RenovationAndPhasing - Renovation Status: Existing
Name | In
Objekt-0079 | Erdgeschoss
Objekt-0079 | Staffelgeschoss

# IfcFlowTerminal: Wand WC 22 (4)
Classification: Sanitäreinrichtung (Archicad Klassifizierung)
AC_Pset_RenovationAndPhasing - Renovation Status: Existing
Name | In
Objekt-0061 | Erdgeschoss
3 x Objekt-0061 | Staffelgeschoss

# IfcFlowTerminal: Waschbecken 1 22 (4)
Classification: Sanitäreinrichtung (Archicad Klassifizierung)
AC_Pset_RenovationAndPhasing - Renovation Status: Existing
Name | In
Objekt-0061 | Erdgeschoss
3 x Objekt-0061 | Staffelgeschoss

# IfcFooting (12)
AC_Pset_RenovationAndPhasing - Renovation Status: Existing
Name | In | Classification | Material
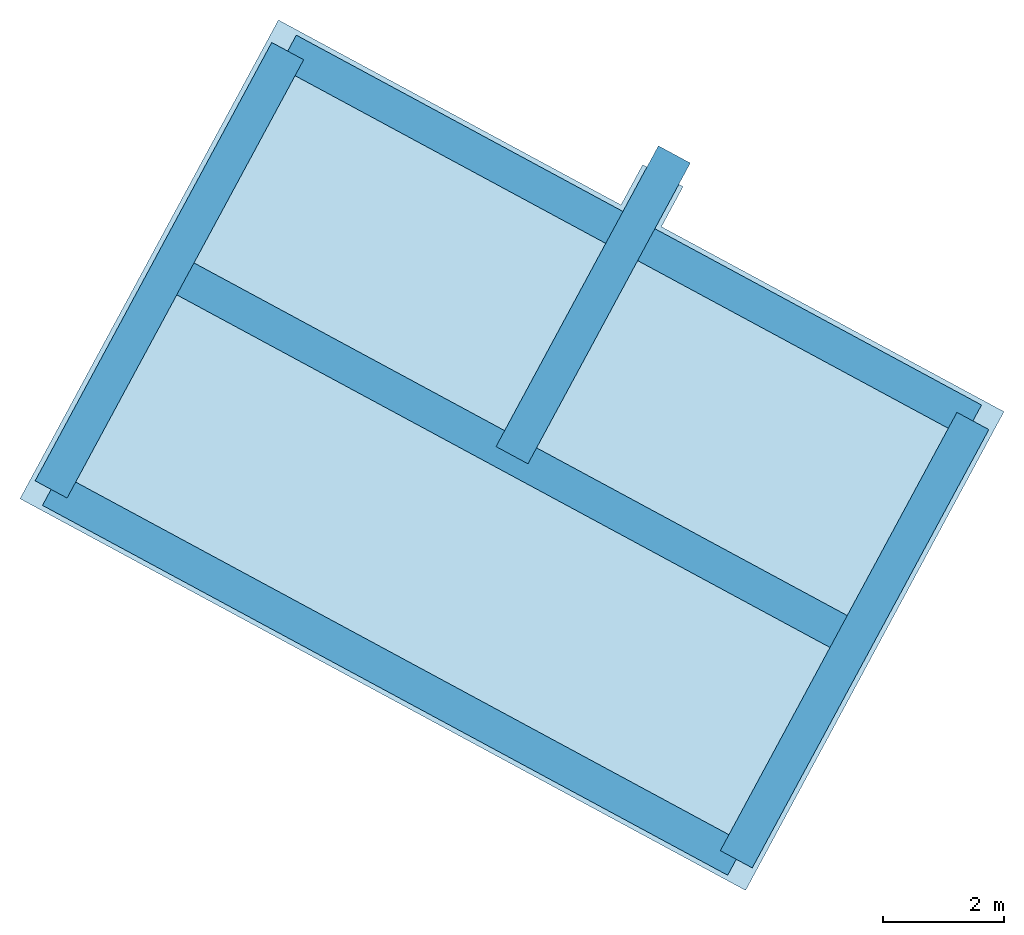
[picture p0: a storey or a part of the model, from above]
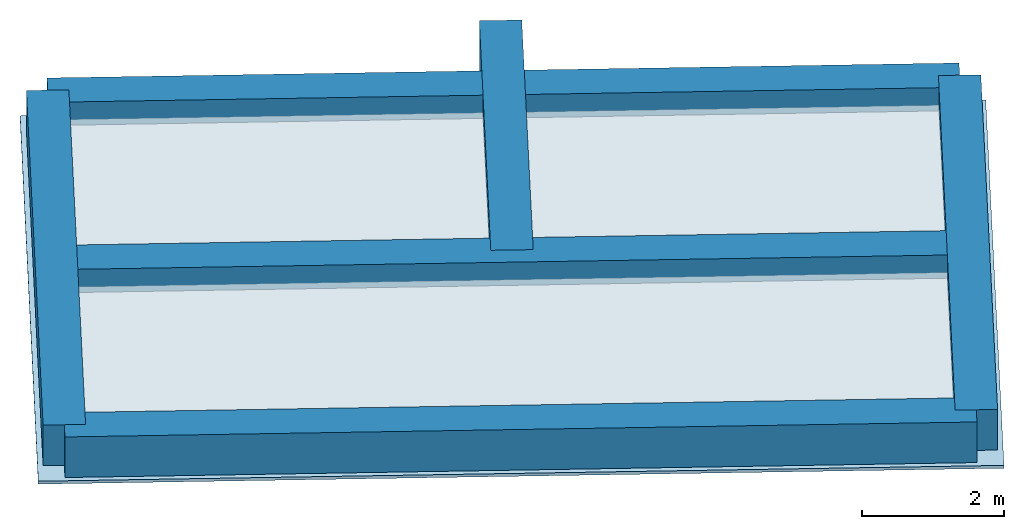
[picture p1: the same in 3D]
Properties of the parts of a building model (IFC2X3), part 2 of 3

# IfcFooting (12)
Name | In | Classification | Material
6 x Unterzug-014 | Gründung | Fundament (Archicad Klassifizierung) | _SIWH - Beton, Stahlbeton | Material Properties - _SIWH - Beton, Stahlbeton, ThermalConductivity: 1.35; _SIWH - Beton, Stahlbeton, SpecificHeatCapacity: 1000 J/kg/K; _SIWH - Beton, Stahlbeton, MassDensity: 2000 kg/m3; _SIWH - Beton, Stahlbeton, Embodied Energy: 0.78 (MJ/kg); _SIWH - Beton, Stahlbeton, Embodied Carbon: 0.113 (kgCO₂/kg); _SIWH - Beton, Stahlbeton, Name: _SIWH - Beton, Stahlbeton; _SIWH - Beton, Stahlbeton, Participates in Collision Detection: yes
Decke037 | Gründung | Fundament (Archicad Klassifizierung) | Beton, unbewehrt | Material Properties - Beton, unbewehrt, ThermalConductivity: 0.8; Beton, unbewehrt, SpecificHeatCapacity: 800 J/kg/K; Beton, unbewehrt, MassDensity: 2300 kg/m3; Beton, unbewehrt, Embodied Energy: 0.92 (MJ/kg); Beton, unbewehrt, Embodied Carbon: 0.15 (kgCO₂/kg); Beton, unbewehrt, Name: Beton, unbewehrt; Beton, unbewehrt, Participates in Collision Detection: yes
Decke038 | Gründung | Fundament (Archicad Klassifizierung) | Beton, unbewehrt | Material Properties - Beton, unbewehrt, ThermalConductivity: 0.8; Beton, unbewehrt, SpecificHeatCapacity: 800 J/kg/K; Beton, unbewehrt, MassDensity: 2300 kg/m3; Beton, unbewehrt, Embodied Energy: 0.92 (MJ/kg); Beton, unbewehrt, Embodied Carbon: 0.15 (kgCO₂/kg); Beton, unbewehrt, Name: Beton, unbewehrt; Beton, unbewehrt, Participates in Collision Detection: yes
Decke036 | Gründung | Fundament (Archicad Klassifizierung) | Beton, unbewehrt | Material Properties - Beton, unbewehrt, ThermalConductivity: 0.8; Beton, unbewehrt, SpecificHeatCapacity: 800 J/kg/K; Beton, unbewehrt, MassDensity: 2300 kg/m3; Beton, unbewehrt, Embodied Energy: 0.92 (MJ/kg); Beton, unbewehrt, Embodied Carbon: 0.15 (kgCO₂/kg); Beton, unbewehrt, Name: Beton, unbewehrt; Beton, unbewehrt, Participates in Collision Detection: yes
A-Wand038 | Kellergeschoss | Streifenfundament (Archicad Klassifizierung) | Beton, Stahlbeton C30/35 | PredefinedType: STRIP_FOOTING; Material Properties - Beton, Stahlbeton C30/35, ThermalConductivity: 1.35; Beton, Stahlbeton C30/35, SpecificHeatCapacity: 1000 J/kg/K; Beton, Stahlbeton C30/35, MassDensity: 2000 kg/m3; Beton, Stahlbeton C30/35, Embodied Energy: 0.78 (MJ/kg); Beton, Stahlbeton C30/35, Embodied Carbon: 0.113 (kgCO₂/kg); Beton, Stahlbeton C30/35, Name: Beton, Stahlbeton C30/35; Beton, Stahlbeton C30/35, Participates in Collision Detection: yes
A-Wand037 | Kellergeschoss | Streifenfundament (Archicad Klassifizierung) | Beton, Stahlbeton C30/35 | PredefinedType: STRIP_FOOTING; Material Properties - Beton, Stahlbeton C30/35, ThermalConductivity: 1.35; Beton, Stahlbeton C30/35, SpecificHeatCapacity: 1000 J/kg/K; Beton, Stahlbeton C30/35, MassDensity: 2000 kg/m3; Beton, Stahlbeton C30/35, Embodied Energy: 0.78 (MJ/kg); Beton, Stahlbeton C30/35, Embodied Carbon: 0.113 (kgCO₂/kg); Beton, Stahlbeton C30/35, Name: Beton, Stahlbeton C30/35; Beton, Stahlbeton C30/35, Participates in Collision Detection: yes
A-Wand036 | Kellergeschoss | Streifenfundament (Archicad Klassifizierung) | MW Kalksandstein | PredefinedType: STRIP_FOOTING; Material Properties - MW Kalksandstein, ThermalConductivity: 0.93; MW Kalksandstein, SpecificHeatCapacity: 840 J/kg/K; MW Kalksandstein, MassDensity: 1800 kg/m3; MW Kalksandstein, Embodied Energy: 1.2 (MJ/kg); MW Kalksandstein, Embodied Carbon: 0.07 (kgCO₂/kg); MW Kalksandstein, Name: MW Kalksandstein; MW Kalksandstein, Participates in Collision Detection: yes

# IfcFurnishingElement: Armstuhl 2 22 (3)
In: Staffelgeschoss
Type - ElementType: FURNITURE
Classification: Möbel (Archicad Klassifizierung)
AC_Pset_RenovationAndPhasing - Renovation Status: Existing

# IfcFurnishingElement: Bistrotisch 26, Objekt-0064
In: Erdgeschoss
Type - ElementType: FURNITURE
Classification: Möbel (Archicad Klassifizierung)
AC_Pset_RenovationAndPhasing - Renovation Status: Existing

# IfcFurnishingElement: Couchtisch 03 26, Objekt-0062
In: Erdgeschoss
Type - ElementType: FURNITURE
Classification: Möbel (Archicad Klassifizierung)
AC_Pset_RenovationAndPhasing - Renovation Status: Existing

# IfcFurnishingElement: Couchtisch 1 22 (8)
Type - ElementType: FURNITURE
Classification: Möbel (Archicad Klassifizierung)
AC_Pset_RenovationAndPhasing - Renovation Status: Existing
Name | In
6 x Objekt-0076 | Erdgeschoss
2 x Objekt-0072 | Staffelgeschoss

# IfcFurnishingElement: Designhocker 22, Objekt-0093
In: Erdgeschoss
Type - ElementType: FURNITURE
Classification: Möbel (Archicad Klassifizierung)
AC_Pset_RenovationAndPhasing - Renovation Status: Existing

# IfcFurnishingElement: Designstuhl 2 22 (2)
In: Staffelgeschoss
Type - ElementType: FURNITURE
Classification: Möbel (Archicad Klassifizierung)
AC_Pset_RenovationAndPhasing - Renovation Status: Existing

# IfcFurnishingElement: Designstuhl 3 22, Objekt-0064
In: Erdgeschoss
Type - ElementType: FURNITURE
Classification: Möbel (Archicad Klassifizierung)
AC_Pset_RenovationAndPhasing - Renovation Status: Existing

# IfcFurnishingElement: Doppelbett 2 22, Objekt-0064
In: Staffelgeschoss
Type - ElementType: FURNITURE
Classification: Möbel (Archicad Klassifizierung)
AC_Pset_RenovationAndPhasing - Renovation Status: Existing

# IfcFurnishingElement: Doppelbett Rahmen 22, Objekt-0064
In: Staffelgeschoss
Type - ElementType: FURNITURE
Classification: Möbel (Archicad Klassifizierung)
AC_Pset_RenovationAndPhasing - Renovation Status: Existing

# IfcFurnishingElement: Flachbildfernseher 22 (3)
Type - ElementType: FURNITURE
Classification: Möbel (Archicad Klassifizierung)
AC_Pset_RenovationAndPhasing - Renovation Status: Existing
Name | In
Objekt-0064 | Erdgeschoss
2 x Objekt-0064 | Staffelgeschoss

# IfcFurnishingElement: Flügel 22, Objekt-0090
In: Erdgeschoss
Type - ElementType: FURNITURE
Classification: Möbel (Archicad Klassifizierung)
AC_Pset_RenovationAndPhasing - Renovation Status: Existing

# IfcFurnishingElement: Gitter 26, Objekt-0100
In: Erdgeschoss
Type - ElementType: FURNITURE
Classification: Möbel (Archicad Klassifizierung)
AC_Pset_RenovationAndPhasing - Renovation Status: Existing

# IfcFurnishingElement: Kamin freistehend 22 (3)
Type - ElementType: FURNITURE
Classification: Möbel (Archicad Klassifizierung)
AC_Pset_RenovationAndPhasing - Renovation Status: Existing
Name | In
Objekt-0070 | Erdgeschoss
2 x Objekt-0070 | Staffelgeschoss

# IfcFurnishingElement: Kleiderschrank 22 (24)
Type - ElementType: FURNITURE
Classification: Möbel (Archicad Klassifizierung)
AC_Pset_RenovationAndPhasing - Renovation Status: Existing
Name | In
5 x Objekt-0067 | Erdgeschoss
19 x Objekt-0066 | Staffelgeschoss

# IfcFurnishingElement: Kleiderschrank modular 22, Objekt-0066
In: Staffelgeschoss
Type - ElementType: FURNITURE
Classification: Möbel (Archicad Klassifizierung)
AC_Pset_RenovationAndPhasing - Renovation Status: Existing

# IfcFurnishingElement: Kommode 26, Objekt-0098
In: Staffelgeschoss
Type - ElementType: FURNITURE
Classification: Möbel (Archicad Klassifizierung)
AC_Pset_RenovationAndPhasing - Renovation Status: Existing

# IfcFurnishingElement: Konzeptküche 26 (5)
In: Erdgeschoss
Type - ElementType: FURNITURE
Classification: Möbel (Archicad Klassifizierung)
AC_Pset_RenovationAndPhasing - Renovation Status: Existing

# IfcFurnishingElement: Regal 1 22 (2)
In: Staffelgeschoss
Type - ElementType: FURNITURE
Classification: Möbel (Archicad Klassifizierung)
AC_Pset_RenovationAndPhasing - Renovation Status: Existing
Name
Objekt-0070
Objekt-0067

# IfcFurnishingElement: Regal 3 22 (5)
In: Erdgeschoss
Type - ElementType: FURNITURE
Classification: Möbel (Archicad Klassifizierung)
AC_Pset_RenovationAndPhasing - Renovation Status: Existing

# IfcFurnishingElement: Schreibtisch 22 (2)
In: Staffelgeschoss
Type - ElementType: FURNITURE
Classification: Möbel (Archicad Klassifizierung)
AC_Pset_RenovationAndPhasing - Renovation Status: Existing

# IfcFurnishingElement: Sideboard 22, Objekt-0067
In: Erdgeschoss
Type - ElementType: FURNITURE
Classification: Möbel (Archicad Klassifizierung)
AC_Pset_RenovationAndPhasing - Renovation Status: Existing

# IfcFurnishingElement: Sideboard wandhängend 26, Objekt-0099
In: Erdgeschoss
Type - ElementType: FURNITURE
Classification: Möbel (Archicad Klassifizierung)
AC_Pset_RenovationAndPhasing - Renovation Status: Existing

# IfcFurnishingElement: Sofa L-Form 01 26, Objekt-0064
In: Erdgeschoss
Type - ElementType: FURNITURE
Classification: Möbel (Archicad Klassifizierung)
AC_Pset_RenovationAndPhasing - Renovation Status: Existing

# IfcFurnishingElement: Sofa Set 01 17 (9)
In: Erdgeschoss
Type - ElementType: FURNITURE
Classification: Möbel (Archicad Klassifizierung)
AC_Pset_RenovationAndPhasing - Renovation Status: Existing

# IfcFurnishingElement: Stuhl 09 26 (12)
In: Erdgeschoss
Type - ElementType: FURNITURE
Classification: Möbel (Archicad Klassifizierung)
AC_Pset_RenovationAndPhasing - Renovation Status: Existing

# IfcFurnishingElement: Teppich 22, Objekt-0074
In: Staffelgeschoss
Type - ElementType: FURNITURE
Classification: Möbel (Archicad Klassifizierung)
AC_Pset_RenovationAndPhasing - Renovation Status: Existing

# IfcFurnishingElement: Tisch rechteckig 1 22, Objekt-0073
In: Erdgeschoss
Type - ElementType: FURNITURE
Classification: Möbel (Archicad Klassifizierung)
AC_Pset_RenovationAndPhasing - Renovation Status: Existing

# IfcFurnishingElement: Unterschrank Mehrfach-Schublade 22 (7)
In: Erdgeschoss
Type - ElementType: FURNITURE
Classification: Möbel (Archicad Klassifizierung)
AC_Pset_RenovationAndPhasing - Renovation Status: Existing

# IfcFurnishingElement: bucket chair (1) (8)
In: Erdgeschoss
Type - ElementType: FURNITURE
Classification: Möbel (Archicad Klassifizierung)
AC_Pset_RenovationAndPhasing - Renovation Status: Existing

# IfcOpeningElement: OPENING, BD-002
In: Erdgeschoss
Classification: Öffnung (Archicad Klassifizierung)
Pset_FireRatingProperties - FireResistanceRating: -
AC_Pset_RenovationAndPhasing - Renovation Status: Existing

# IfcRailing: Geländerart (5)
In: Staffelgeschoss
Classification: Geländer (Archicad Klassifizierung)
AC_Pset_RenovationAndPhasing - Renovation Status: Existing
Pset_RailingCommon - IsExternal: no
Material Properties - Metall, Stahl lackiert, ThermalConductivity: 50; Metall, Stahl lackiert, SpecificHeatCapacity: 450 J/kg/K; Metall, Stahl lackiert, MassDensity: 7800 kg/m3; Metall, Stahl lackiert, Embodied Energy: 20.1 (MJ/kg); Metall, Stahl lackiert, Embodied Carbon: 1.46 (kgCO₂/kg); Metall, Stahl lackiert, Name: Metall, Stahl lackiert; Metall, Stahl lackiert, Participates in Collision Detection: yes
Name | Material | Glas, Normalglas-50% durchlässig, ThermalConductivity | Glas, Normalglas-50% durchlässig, SpecificHeatCapacity (J/kg/K) | Glas, Normalglas-50% durchlässig, MassDensity (kg/m3) | Glas, Normalglas-50% durchlässig, Embodied Energy | Glas, Normalglas-50% durchlässig, Embodied Carbon | Glas, Normalglas-50% durchlässig, Name | Glas, Normalglas-50% durchlässig, Participates in Collision Detection
4 x Geländer-005 | Metall, Stahl lackiert (5), Glas, Normalglas-50% durchlässig | 1.4 | 750 | 2200 | 0.85 (MJ/kg) | 0.02 (kgCO₂/kg) | Glas, Normalglas-50% durchlässig | yes
Geländer-005 | Metall, Stahl lackiert (5), Glas, Normalglas | Material Properties - Glas, Normalglas, ThermalConductivity: 1.4; Glas, Normalglas, SpecificHeatCapacity: 750 J/kg/K; Glas, Normalglas, MassDensity: 2200 kg/m3; Glas, Normalglas, Embodied Energy: 0.85 (MJ/kg); Glas, Normalglas, Embodied Carbon: 0.02 (kgCO₂/kg); Glas, Normalglas, Name: Glas, Normalglas; Glas, Normalglas, Participates in Collision Detection: yes

# IfcSlab: Beton, unbewehrt 50, Decke039
In: Gründung
Type - PredefinedType: BASESLAB
Classification: Bodenplatte / Flachgründung (Archicad Klassifizierung); Material: Beton, unbewehrt 0.05 m
Pset_SlabCommon - IsExternal: yes; LoadBearing: no
AC_Pset_RenovationAndPhasing - Renovation Status: Existing
Material Properties - Beton, unbewehrt, ThermalConductivity: 0.8; Beton, unbewehrt, SpecificHeatCapacity: 800 J/kg/K; Beton, unbewehrt, MassDensity: 2300 kg/m3; Beton, unbewehrt, Embodied Energy: 0.92 (MJ/kg); Beton, unbewehrt, Embodied Carbon: 0.15 (kgCO₂/kg); Beton, unbewehrt, Name: Beton, unbewehrt; Beton, unbewehrt, Participates in Collision Detection: yes

# IfcSlab: _SIWH - Beton, Stahlbeton 120, Decke013
In: Staffelgeschoss
Type - PredefinedType: FLOOR
Classification: Rohbaudecke (Archicad Klassifizierung); Material: _SIWH - Beton, Stahlbeton 0.12 m
Pset_SlabCommon - FireRating: -; IsExternal: no; LoadBearing: yes
Pset_FireRatingProperties - FireResistanceRating: -
AC_Pset_RenovationAndPhasing - Renovation Status: Existing
Material Properties - _SIWH - Beton, Stahlbeton, ThermalConductivity: 1.35; _SIWH - Beton, Stahlbeton, SpecificHeatCapacity: 1000 J/kg/K; _SIWH - Beton, Stahlbeton, MassDensity: 2000 kg/m3; _SIWH - Beton, Stahlbeton, Embodied Energy: 0.78 (MJ/kg); _SIWH - Beton, Stahlbeton, Embodied Carbon: 0.113 (kgCO₂/kg); _SIWH - Beton, Stahlbeton, Name: _SIWH - Beton, Stahlbeton; _SIWH - Beton, Stahlbeton, Participates in Collision Detection: yes

# IfcSlab: _SIWH - Beton, Stahlbeton 200 (9)
Type - PredefinedType: FLOOR
Classification: Rohbaudecke (Archicad Klassifizierung)
Pset_FireRatingProperties - FireResistanceRating: -
AC_Pset_RenovationAndPhasing - Renovation Status: Existing
Material Properties - _SIWH - Beton, Stahlbeton, ThermalConductivity: 1.35; _SIWH - Beton, Stahlbeton, SpecificHeatCapacity: 1000 J/kg/K; _SIWH - Beton, Stahlbeton, MassDensity: 2000 kg/m3; _SIWH - Beton, Stahlbeton, Embodied Energy: 0.78 (MJ/kg); _SIWH - Beton, Stahlbeton, Embodied Carbon: 0.113 (kgCO₂/kg); _SIWH - Beton, Stahlbeton, Name: _SIWH - Beton, Stahlbeton; _SIWH - Beton, Stahlbeton, Participates in Collision Detection: yes
Pset_SlabCommon - FireRating: -; LoadBearing: yes
Name | In | Material | IsExternal
5 x Wand-026 | Staffelgeschoss | _SIWH - Beton, Stahlbeton | yes
Decke010 | Staffelgeschoss | _SIWH - Beton, Stahlbeton 0.2 m | no
Decke020 | Staffelgeschoss | _SIWH - Beton, Stahlbeton 0.2 m | no
Decke-004 | Staffelgeschoss | _SIWH - Beton, Stahlbeton 0.2 m | no
Decke030 | Dachaufsicht | _SIWH - Beton, Stahlbeton 0.2 m | no

# IfcSlab: _SIWH - Beton, Stahlbeton 250 (3)
Type - PredefinedType: FLOOR
Classification: Rohbaudecke (Archicad Klassifizierung); Material: _SIWH - Beton, Stahlbeton 0.25 m
Pset_SlabCommon - FireRating: -; IsExternal: no; LoadBearing: yes
Pset_FireRatingProperties - FireResistanceRating: -
Material Properties - _SIWH - Beton, Stahlbeton, ThermalConductivity: 1.35; _SIWH - Beton, Stahlbeton, SpecificHeatCapacity: 1000 J/kg/K; _SIWH - Beton, Stahlbeton, MassDensity: 2000 kg/m3; _SIWH - Beton, Stahlbeton, Embodied Energy: 0.78 (MJ/kg); _SIWH - Beton, Stahlbeton, Embodied Carbon: 0.113 (kgCO₂/kg); _SIWH - Beton, Stahlbeton, Name: _SIWH - Beton, Stahlbeton; _SIWH - Beton, Stahlbeton, Participates in Collision Detection: yes
AC_Pset_RenovationAndPhasing - Renovation Status: Existing
Name | In
Decke004 | Erdgeschoss
Decke009 | Staffelgeschoss
Decke-004 | Staffelgeschoss

# IfcSlab: _SIWH - Beton, Stahlbeton 300, Decke027
In: Kellergeschoss
Type - PredefinedType: FLOOR
Classification: Rohbaudecke (Archicad Klassifizierung); Material: _SIWH - Beton, Stahlbeton 0.3 m
Pset_SlabCommon - FireRating: -; IsExternal: yes; LoadBearing: yes
Pset_FireRatingProperties - FireResistanceRating: -
AC_Pset_RenovationAndPhasing - Renovation Status: Existing
Material Properties - _SIWH - Beton, Stahlbeton, ThermalConductivity: 1.35; _SIWH - Beton, Stahlbeton, SpecificHeatCapacity: 1000 J/kg/K; _SIWH - Beton, Stahlbeton, MassDensity: 2000 kg/m3; _SIWH - Beton, Stahlbeton, Embodied Energy: 0.78 (MJ/kg); _SIWH - Beton, Stahlbeton, Embodied Carbon: 0.113 (kgCO₂/kg); _SIWH - Beton, Stahlbeton, Name: _SIWH - Beton, Stahlbeton; _SIWH - Beton, Stahlbeton, Participates in Collision Detection: yes

# IfcSlab: _SIWH - Beton, Stahlbeton 340, Decke006
In: Staffelgeschoss
Type - PredefinedType: FLOOR
Classification: Rohbaudecke (Archicad Klassifizierung); Material: _SIWH - Beton, Stahlbeton 0.34 m
Pset_FireRatingProperties - FireResistanceRating: -
AC_Pset_RenovationAndPhasing - Renovation Status: Existing
Material Properties - _SIWH - Beton, Stahlbeton, ThermalConductivity: 1.35; _SIWH - Beton, Stahlbeton, SpecificHeatCapacity: 1000 J/kg/K; _SIWH - Beton, Stahlbeton, MassDensity: 2000 kg/m3; _SIWH - Beton, Stahlbeton, Embodied Energy: 0.78 (MJ/kg); _SIWH - Beton, Stahlbeton, Embodied Carbon: 0.113 (kgCO₂/kg); _SIWH - Beton, Stahlbeton, Name: _SIWH - Beton, Stahlbeton; _SIWH - Beton, Stahlbeton, Participates in Collision Detection: yes
Pset_SlabCommon - FireRating: -; IsExternal: no; LoadBearing: yes

# IfcSlab: _SIWH - Beton, Stahlbeton Polygon, Wand-026
In: Staffelgeschoss
Type - PredefinedType: FLOOR
Classification: Rohbaudecke (Archicad Klassifizierung); Material: _SIWH - Beton, Stahlbeton
Pset_SlabCommon - FireRating: -; IsExternal: yes; LoadBearing: yes
Pset_FireRatingProperties - FireResistanceRating: -
Material Properties - _SIWH - Beton, Stahlbeton, ThermalConductivity: 1.35; _SIWH - Beton, Stahlbeton, SpecificHeatCapacity: 1000 J/kg/K; _SIWH - Beton, Stahlbeton, MassDensity: 2000 kg/m3; _SIWH - Beton, Stahlbeton, Embodied Energy: 0.78 (MJ/kg); _SIWH - Beton, Stahlbeton, Embodied Carbon: 0.113 (kgCO₂/kg); _SIWH - Beton, Stahlbeton, Name: _SIWH - Beton, Stahlbeton; _SIWH - Beton, Stahlbeton, Participates in Collision Detection: yes
AC_Pset_RenovationAndPhasing - Renovation Status: Existing

# IfcSlab: _SIWH - Dämmung, weich Mineralwolle 200, Decke021
In: Staffelgeschoss
Type - PredefinedType: FLOOR
Classification: Rohbaudecke (Archicad Klassifizierung); Material: _SIWH - Dämmung, weich Mineralwolle 0.2 m
Pset_SlabCommon - FireRating: -; IsExternal: no; LoadBearing: yes
Pset_FireRatingProperties - FireResistanceRating: -
AC_Pset_RenovationAndPhasing - Renovation Status: Existing
Material Properties - _SIWH - Dämmung, weich Mineralwolle, ThermalConductivity: 0.037; _SIWH - Dämmung, weich Mineralwolle, SpecificHeatCapacity: 840 J/kg/K; _SIWH - Dämmung, weich Mineralwolle, MassDensity: 40 kg/m3; _SIWH - Dämmung, weich Mineralwolle, Embodied Energy: 14.3 (MJ/kg); _SIWH - Dämmung, weich Mineralwolle, Embodied Carbon: 1.08 (kgCO₂/kg); _SIWH - Dämmung, weich Mineralwolle, Name: _SIWH - Dämmung, weich Mineralwolle; _SIWH - Dämmung, weich Mineralwolle, Participates in Collision Detection: yes

# IfcSlab: _SIWH - Vordach Eingang 1 4035 x 310, Wand-024
In: Staffelgeschoss
Type - PredefinedType: FLOOR
Classification: Rohbaudecke (Archicad Klassifizierung); Material: _SIWH - Abgehängte Decke Arkade (3), _SIWH - Holz, Bauholz (4), _SIWH - Dämmung, weich Mineralwolle, _SIWH - Luftschicht vertikal (3)
Pset_SlabCommon - FireRating: -; IsExternal: yes; LoadBearing: yes
AC_Pset_RenovationAndPhasing - Renovation Status: Existing
Material Properties - _SIWH - Abgehängte Decke Arkade, ThermalConductivity: 0.13; _SIWH - Abgehängte Decke Arkade, SpecificHeatCapacity: 1600 J/kg/K; _SIWH - Abgehängte Decke Arkade, MassDensity: 500 kg/m3; _SIWH - Abgehängte Decke Arkade, Embodied Energy: 13.1 (MJ/kg); _SIWH - Abgehängte Decke Arkade, Embodied Carbon: 0.64 (kgCO₂/kg); _SIWH - Abgehängte Decke Arkade, Name: _SIWH - Abgehängte Decke Arkade; _SIWH - Abgehängte Decke Arkade, Participates in Collision Detection: yes; _SIWH - Holz, Bauholz, ThermalConductivity: 0.13; _SIWH - Holz, Bauholz, SpecificHeatCapacity: 1600 J/kg/K; _SIWH - Holz, Bauholz, MassDensity: 500 kg/m3; _SIWH - Holz, Bauholz, Embodied Energy: 6.95 (MJ/kg); _SIWH - Holz, Bauholz, Embodied Carbon: 0.29 (kgCO₂/kg); _SIWH - Holz, Bauholz, Name: _SIWH - Holz, Bauholz; _SIWH - Holz, Bauholz, Participates in Collision Detection: yes; _SIWH - Dämmung, weich Mineralwolle, ThermalConductivity: 0.037; _SIWH - Dämmung, weich Mineralwolle, SpecificHeatCapacity: 840 J/kg/K; _SIWH - Dämmung, weich Mineralwolle, MassDensity: 40 kg/m3; _SIWH - Dämmung, weich Mineralwolle, Embodied Energy: 14.3 (MJ/kg); _SIWH - Dämmung, weich Mineralwolle, Embodied Carbon: 1.08 (kgCO₂/kg); _SIWH - Dämmung, weich Mineralwolle, Name: _SIWH - Dämmung, weich Mineralwolle; _SIWH - Dämmung, weich Mineralwolle, Participates in Collision Detection: yes; _SIWH - Luftschicht vertikal, ThermalConductivity: 0.16; _SIWH - Luftschicht vertikal, SpecificHeatCapacity: 1008 J/kg/K; _SIWH - Luftschicht vertikal, MassDensity: 1.2 kg/m3; _SIWH - Luftschicht vertikal, Embodied Energy: 0 (MJ/kg); _SIWH - Luftschicht vertikal, Embodied Carbon: 0 (kgCO₂/kg); _SIWH - Luftschicht vertikal, Name: _SIWH - Luftschicht vertikal; _SIWH - Luftschicht vertikal, Participates in Collision Detection: no
Pset_FireRatingProperties - FireResistanceRating: -

# IfcSlab: _SIWH - Vordach Eingang 2 2720 x 310 (2)
In: Staffelgeschoss
Type - PredefinedType: FLOOR
Classification: Rohbaudecke (Archicad Klassifizierung); Material: _SIWH - Abgehängte Decke Arkade (3), _SIWH - Holz, Bauholz (2), _SIWH - Dämmung, weich Mineralwolle, _SIWH - Luftschicht vertikal (2)
Pset_SlabCommon - FireRating: -; IsExternal: yes; LoadBearing: yes
Pset_FireRatingProperties - FireResistanceRating: -
AC_Pset_RenovationAndPhasing - Renovation Status: Existing
Material Properties - _SIWH - Abgehängte Decke Arkade, ThermalConductivity: 0.13; _SIWH - Abgehängte Decke Arkade, SpecificHeatCapacity: 1600 J/kg/K; _SIWH - Abgehängte Decke Arkade, MassDensity: 500 kg/m3; _SIWH - Abgehängte Decke Arkade, Embodied Energy: 13.1 (MJ/kg); _SIWH - Abgehängte Decke Arkade, Embodied Carbon: 0.64 (kgCO₂/kg); _SIWH - Abgehängte Decke Arkade, Name: _SIWH - Abgehängte Decke Arkade; _SIWH - Abgehängte Decke Arkade, Participates in Collision Detection: yes; _SIWH - Holz, Bauholz, ThermalConductivity: 0.13; _SIWH - Holz, Bauholz, SpecificHeatCapacity: 1600 J/kg/K; _SIWH - Holz, Bauholz, MassDensity: 500 kg/m3; _SIWH - Holz, Bauholz, Embodied Energy: 6.95 (MJ/kg); _SIWH - Holz, Bauholz, Embodied Carbon: 0.29 (kgCO₂/kg); _SIWH - Holz, Bauholz, Name: _SIWH - Holz, Bauholz; _SIWH - Holz, Bauholz, Participates in Collision Detection: yes; _SIWH - Dämmung, weich Mineralwolle, ThermalConductivity: 0.037; _SIWH - Dämmung, weich Mineralwolle, SpecificHeatCapacity: 840 J/kg/K; _SIWH - Dämmung, weich Mineralwolle, MassDensity: 40 kg/m3; _SIWH - Dämmung, weich Mineralwolle, Embodied Energy: 14.3 (MJ/kg); _SIWH - Dämmung, weich Mineralwolle, Embodied Carbon: 1.08 (kgCO₂/kg); _SIWH - Dämmung, weich Mineralwolle, Name: _SIWH - Dämmung, weich Mineralwolle; _SIWH - Dämmung, weich Mineralwolle, Participates in Collision Detection: yes; _SIWH - Luftschicht vertikal, ThermalConductivity: 0.16; _SIWH - Luftschicht vertikal, SpecificHeatCapacity: 1008 J/kg/K; _SIWH - Luftschicht vertikal, MassDensity: 1.2 kg/m3; _SIWH - Luftschicht vertikal, Embodied Energy: 0 (MJ/kg); _SIWH - Luftschicht vertikal, Embodied Carbon: 0 (kgCO₂/kg); _SIWH - Luftschicht vertikal, Name: _SIWH - Luftschicht vertikal; _SIWH - Luftschicht vertikal, Participates in Collision Detection: no

# IfcSlab: _SIWH - Vordach Luftbalken2 410 x 980, Wand-024
In: Staffelgeschoss
Type - PredefinedType: FLOOR
Classification: Rohbaudecke (Archicad Klassifizierung); Material: _SIWH - Beton, Stahlbeton Fertigteil, _SIWH - Metall, Aluminium
Pset_SlabCommon - FireRating: -; IsExternal: yes; LoadBearing: yes
Pset_FireRatingProperties - FireResistanceRating: -
AC_Pset_RenovationAndPhasing - Renovation Status: Existing
Material Properties - _SIWH - Beton, Stahlbeton Fertigteil, ThermalConductivity: 1.15; _SIWH - Beton, Stahlbeton Fertigteil, SpecificHeatCapacity: 1000 J/kg/K; _SIWH - Beton, Stahlbeton Fertigteil, MassDensity: 1800 kg/m3; _SIWH - Beton, Stahlbeton Fertigteil, Embodied Energy: 0.74 (MJ/kg); _SIWH - Beton, Stahlbeton Fertigteil, Embodied Carbon: 0.107 (kgCO₂/kg); _SIWH - Beton, Stahlbeton Fertigteil, Name: _SIWH - Beton, Stahlbeton Fertigteil; _SIWH - Beton, Stahlbeton Fertigteil, Participates in Collision Detection: yes; _SIWH - Metall, Aluminium, ThermalConductivity: 160; _SIWH - Metall, Aluminium, SpecificHeatCapacity: 880 J/kg/K; _SIWH - Metall, Aluminium, MassDensity: 2800 kg/m3; _SIWH - Metall, Aluminium, Embodied Energy: 155 (MJ/kg); _SIWH - Metall, Aluminium, Embodied Carbon: 9.16 (kgCO₂/kg); _SIWH - Metall, Aluminium, Name: _SIWH - Metall, Aluminium; _SIWH - Metall, Aluminium, Participates in Collision Detection: yes

# IfcSlab: _SIWH - Vordach+Arkade1 1555 x 980 (3)
In: Staffelgeschoss
Type - PredefinedType: FLOOR
Classification: Rohbaudecke (Archicad Klassifizierung); Material: _SIWH - Dämmung, weich Mineralwolle, _SIWH - Beton, Stahlbeton, _SIWH - Beton, Stahlbeton Fertigteil, _SIWH - Metall, Aluminium
Pset_SlabCommon - FireRating: -; IsExternal: yes; LoadBearing: yes
AC_Pset_RenovationAndPhasing - Renovation Status: Existing
Pset_FireRatingProperties - FireResistanceRating: -
Material Properties - _SIWH - Dämmung, weich Mineralwolle, ThermalConductivity: 0.037; _SIWH - Dämmung, weich Mineralwolle, SpecificHeatCapacity: 840 J/kg/K; _SIWH - Dämmung, weich Mineralwolle, MassDensity: 40 kg/m3; _SIWH - Dämmung, weich Mineralwolle, Embodied Energy: 14.3 (MJ/kg); _SIWH - Dämmung, weich Mineralwolle, Embodied Carbon: 1.08 (kgCO₂/kg); _SIWH - Dämmung, weich Mineralwolle, Name: _SIWH - Dämmung, weich Mineralwolle; _SIWH - Dämmung, weich Mineralwolle, Participates in Collision Detection: yes; _SIWH - Beton, Stahlbeton, ThermalConductivity: 1.35; _SIWH - Beton, Stahlbeton, SpecificHeatCapacity: 1000 J/kg/K; _SIWH - Beton, Stahlbeton, MassDensity: 2000 kg/m3; _SIWH - Beton, Stahlbeton, Embodied Energy: 0.78 (MJ/kg); _SIWH - Beton, Stahlbeton, Embodied Carbon: 0.113 (kgCO₂/kg); _SIWH - Beton, Stahlbeton, Name: _SIWH - Beton, Stahlbeton; _SIWH - Beton, Stahlbeton, Participates in Collision Detection: yes; _SIWH - Beton, Stahlbeton Fertigteil, ThermalConductivity: 1.15; _SIWH - Beton, Stahlbeton Fertigteil, SpecificHeatCapacity: 1000 J/kg/K; _SIWH - Beton, Stahlbeton Fertigteil, MassDensity: 1800 kg/m3; _SIWH - Beton, Stahlbeton Fertigteil, Embodied Energy: 0.74 (MJ/kg); _SIWH - Beton, Stahlbeton Fertigteil, Embodied Carbon: 0.107 (kgCO₂/kg); _SIWH - Beton, Stahlbeton Fertigteil, Name: _SIWH - Beton, Stahlbeton Fertigteil; _SIWH - Beton, Stahlbeton Fertigteil, Participates in Collision Detection: yes; _SIWH - Metall, Aluminium, ThermalConductivity: 160; _SIWH - Metall, Aluminium, SpecificHeatCapacity: 880 J/kg/K; _SIWH - Metall, Aluminium, MassDensity: 2800 kg/m3; _SIWH - Metall, Aluminium, Embodied Energy: 155 (MJ/kg); _SIWH - Metall, Aluminium, Embodied Carbon: 9.16 (kgCO₂/kg); _SIWH - Metall, Aluminium, Name: _SIWH - Metall, Aluminium; _SIWH - Metall, Aluminium, Participates in Collision Detection: yes

# IfcSlab: _SIWH - Vordach+Arkade2 1555 x 980, Wand-024
In: Staffelgeschoss
Type - PredefinedType: FLOOR
Classification: Rohbaudecke (Archicad Klassifizierung); Material: _SIWH - Dämmung, weich Mineralwolle, _SIWH - Beton, Stahlbeton, _SIWH - Beton, Stahlbeton Fertigteil, _SIWH - Metall, Aluminium
Pset_SlabCommon - FireRating: -; IsExternal: yes; LoadBearing: yes
Pset_FireRatingProperties - FireResistanceRating: -
AC_Pset_RenovationAndPhasing - Renovation Status: Existing
Material Properties - _SIWH - Dämmung, weich Mineralwolle, ThermalConductivity: 0.037; _SIWH - Dämmung, weich Mineralwolle, SpecificHeatCapacity: 840 J/kg/K; _SIWH - Dämmung, weich Mineralwolle, MassDensity: 40 kg/m3; _SIWH - Dämmung, weich Mineralwolle, Embodied Energy: 14.3 (MJ/kg); _SIWH - Dämmung, weich Mineralwolle, Embodied Carbon: 1.08 (kgCO₂/kg); _SIWH - Dämmung, weich Mineralwolle, Name: _SIWH - Dämmung, weich Mineralwolle; _SIWH - Dämmung, weich Mineralwolle, Participates in Collision Detection: yes; _SIWH - Beton, Stahlbeton, ThermalConductivity: 1.35; _SIWH - Beton, Stahlbeton, SpecificHeatCapacity: 1000 J/kg/K; _SIWH - Beton, Stahlbeton, MassDensity: 2000 kg/m3; _SIWH - Beton, Stahlbeton, Embodied Energy: 0.78 (MJ/kg); _SIWH - Beton, Stahlbeton, Embodied Carbon: 0.113 (kgCO₂/kg); _SIWH - Beton, Stahlbeton, Name: _SIWH - Beton, Stahlbeton; _SIWH - Beton, Stahlbeton, Participates in Collision Detection: yes; _SIWH - Beton, Stahlbeton Fertigteil, ThermalConductivity: 1.15; _SIWH - Beton, Stahlbeton Fertigteil, SpecificHeatCapacity: 1000 J/kg/K; _SIWH - Beton, Stahlbeton Fertigteil, MassDensity: 1800 kg/m3; _SIWH - Beton, Stahlbeton Fertigteil, Embodied Energy: 0.74 (MJ/kg); _SIWH - Beton, Stahlbeton Fertigteil, Embodied Carbon: 0.107 (kgCO₂/kg); _SIWH - Beton, Stahlbeton Fertigteil, Name: _SIWH - Beton, Stahlbeton Fertigteil; _SIWH - Beton, Stahlbeton Fertigteil, Participates in Collision Detection: yes; _SIWH - Metall, Aluminium, ThermalConductivity: 160; _SIWH - Metall, Aluminium, SpecificHeatCapacity: 880 J/kg/K; _SIWH - Metall, Aluminium, MassDensity: 2800 kg/m3; _SIWH - Metall, Aluminium, Embodied Energy: 155 (MJ/kg); _SIWH - Metall, Aluminium, Embodied Carbon: 9.16 (kgCO₂/kg); _SIWH - Metall, Aluminium, Name: _SIWH - Metall, Aluminium; _SIWH - Metall, Aluminium, Participates in Collision Detection: yes

# IfcSlab: _SIWH - Vordach+Arkade2 nur Luftbalken 210 x 650, Wand-024
In: Staffelgeschoss
Type - PredefinedType: FLOOR
Classification: Rohbaudecke (Archicad Klassifizierung); Material: _SIWH - Metall, Aluminium, _SIWH - Beton, Stahlbeton Fertigteil
Pset_SlabCommon - FireRating: -; IsExternal: yes; LoadBearing: yes
Pset_FireRatingProperties - FireResistanceRating: -
AC_Pset_RenovationAndPhasing - Renovation Status: Existing
Material Properties - _SIWH - Metall, Aluminium, ThermalConductivity: 160; _SIWH - Metall, Aluminium, SpecificHeatCapacity: 880 J/kg/K; _SIWH - Metall, Aluminium, MassDensity: 2800 kg/m3; _SIWH - Metall, Aluminium, Embodied Energy: 155 (MJ/kg); _SIWH - Metall, Aluminium, Embodied Carbon: 9.16 (kgCO₂/kg); _SIWH - Metall, Aluminium, Name: _SIWH - Metall, Aluminium; _SIWH - Metall, Aluminium, Participates in Collision Detection: yes; _SIWH - Beton, Stahlbeton Fertigteil, ThermalConductivity: 1.15; _SIWH - Beton, Stahlbeton Fertigteil, SpecificHeatCapacity: 1000 J/kg/K; _SIWH - Beton, Stahlbeton Fertigteil, MassDensity: 1800 kg/m3; _SIWH - Beton, Stahlbeton Fertigteil, Embodied Energy: 0.74 (MJ/kg); _SIWH - Beton, Stahlbeton Fertigteil, Embodied Carbon: 0.107 (kgCO₂/kg); _SIWH - Beton, Stahlbeton Fertigteil, Name: _SIWH - Beton, Stahlbeton Fertigteil; _SIWH - Beton, Stahlbeton Fertigteil, Participates in Collision Detection: yes

# IfcSlab: _SIWH - Vordach+Arkade3 1395 x 980, Wand-024
In: Staffelgeschoss
Type - PredefinedType: FLOOR
Classification: Rohbaudecke (Archicad Klassifizierung); Material: _SIWH - Dämmung, weich Mineralwolle, _SIWH - Beton, Stahlbeton, _SIWH - Beton, Stahlbeton Fertigteil, _SIWH - Metall, Aluminium
Pset_SlabCommon - FireRating: -; IsExternal: yes; LoadBearing: yes
Pset_FireRatingProperties - FireResistanceRating: -
AC_Pset_RenovationAndPhasing - Renovation Status: Existing
Material Properties - _SIWH - Dämmung, weich Mineralwolle, ThermalConductivity: 0.037; _SIWH - Dämmung, weich Mineralwolle, SpecificHeatCapacity: 840 J/kg/K; _SIWH - Dämmung, weich Mineralwolle, MassDensity: 40 kg/m3; _SIWH - Dämmung, weich Mineralwolle, Embodied Energy: 14.3 (MJ/kg); _SIWH - Dämmung, weich Mineralwolle, Embodied Carbon: 1.08 (kgCO₂/kg); _SIWH - Dämmung, weich Mineralwolle, Name: _SIWH - Dämmung, weich Mineralwolle; _SIWH - Dämmung, weich Mineralwolle, Participates in Collision Detection: yes; _SIWH - Beton, Stahlbeton, ThermalConductivity: 1.35; _SIWH - Beton, Stahlbeton, SpecificHeatCapacity: 1000 J/kg/K; _SIWH - Beton, Stahlbeton, MassDensity: 2000 kg/m3; _SIWH - Beton, Stahlbeton, Embodied Energy: 0.78 (MJ/kg); _SIWH - Beton, Stahlbeton, Embodied Carbon: 0.113 (kgCO₂/kg); _SIWH - Beton, Stahlbeton, Name: _SIWH - Beton, Stahlbeton; _SIWH - Beton, Stahlbeton, Participates in Collision Detection: yes; _SIWH - Beton, Stahlbeton Fertigteil, ThermalConductivity: 1.15; _SIWH - Beton, Stahlbeton Fertigteil, SpecificHeatCapacity: 1000 J/kg/K; _SIWH - Beton, Stahlbeton Fertigteil, MassDensity: 1800 kg/m3; _SIWH - Beton, Stahlbeton Fertigteil, Embodied Energy: 0.74 (MJ/kg); _SIWH - Beton, Stahlbeton Fertigteil, Embodied Carbon: 0.107 (kgCO₂/kg); _SIWH - Beton, Stahlbeton Fertigteil, Name: _SIWH - Beton, Stahlbeton Fertigteil; _SIWH - Beton, Stahlbeton Fertigteil, Participates in Collision Detection: yes; _SIWH - Metall, Aluminium, ThermalConductivity: 160; _SIWH - Metall, Aluminium, SpecificHeatCapacity: 880 J/kg/K; _SIWH - Metall, Aluminium, MassDensity: 2800 kg/m3; _SIWH - Metall, Aluminium, Embodied Energy: 155 (MJ/kg); _SIWH - Metall, Aluminium, Embodied Carbon: 9.16 (kgCO₂/kg); _SIWH - Metall, Aluminium, Name: _SIWH - Metall, Aluminium; _SIWH - Metall, Aluminium, Participates in Collision Detection: yes

# IfcSlab: _SIWH - Vordach+Arkade3 nur Luftbalken 210 x 980 (2)
In: Staffelgeschoss
Type - PredefinedType: FLOOR
Classification: Rohbaudecke (Archicad Klassifizierung); Material: _SIWH - Beton, Stahlbeton Fertigteil, _SIWH - Metall, Aluminium
Pset_SlabCommon - FireRating: -; IsExternal: yes; LoadBearing: yes
Pset_FireRatingProperties - FireResistanceRating: -
AC_Pset_RenovationAndPhasing - Renovation Status: Existing
Material Properties - _SIWH - Beton, Stahlbeton Fertigteil, ThermalConductivity: 1.15; _SIWH - Beton, Stahlbeton Fertigteil, SpecificHeatCapacity: 1000 J/kg/K; _SIWH - Beton, Stahlbeton Fertigteil, MassDensity: 1800 kg/m3; _SIWH - Beton, Stahlbeton Fertigteil, Embodied Energy: 0.74 (MJ/kg); _SIWH - Beton, Stahlbeton Fertigteil, Embodied Carbon: 0.107 (kgCO₂/kg); _SIWH - Beton, Stahlbeton Fertigteil, Name: _SIWH - Beton, Stahlbeton Fertigteil; _SIWH - Beton, Stahlbeton Fertigteil, Participates in Collision Detection: yes; _SIWH - Metall, Aluminium, ThermalConductivity: 160; _SIWH - Metall, Aluminium, SpecificHeatCapacity: 880 J/kg/K; _SIWH - Metall, Aluminium, MassDensity: 2800 kg/m3; _SIWH - Metall, Aluminium, Embodied Energy: 155 (MJ/kg); _SIWH - Metall, Aluminium, Embodied Carbon: 9.16 (kgCO₂/kg); _SIWH - Metall, Aluminium, Name: _SIWH - Metall, Aluminium; _SIWH - Metall, Aluminium, Participates in Collision Detection: yes

# IfcStair (14)
Classification: Treppe (Archicad Klassifizierung)
Pset_StairCommon - FireRating: -
Pset_FireRatingProperties - FireResistanceRating: -
AC_Pset_RenovationAndPhasing - Renovation Status: Existing
Name | In | Material | ALLGEMEIN - NIEDRIGE PRIORITÄT, ThermalConductivity = ALLGEMEIN - NIEDRIGE PRIORITÄT, SpecificHeatCapacity (J/kg/K) = ALLGEMEIN - NIEDRIGE PRIORITÄT, MassDensity (kg/m3) | ALLGEMEIN - NIEDRIGE PRIORITÄT, Embodied Energy | ALLGEMEIN - NIEDRIGE PRIORITÄT, Embodied Carbon | ALLGEMEIN - NIEDRIGE PRIORITÄT, Name | ALLGEMEIN - NIEDRIGE PRIORITÄT, Participates in Collision Detection
Treppe-001 | Kellergeschoss | ALLGEMEIN - BAUTEIL | Pset_StairCommon - NumberOfRiser: 16; NumberOfTreads: 15; RiserHeight: 0.18625 m; RequiredHeadroom: 2.2 m; IsExternal: no; Material Properties - ALLGEMEIN - BAUTEIL, ThermalConductivity: 0.13; ALLGEMEIN - BAUTEIL, SpecificHeatCapacity: 1600 J/kg/K; ALLGEMEIN - BAUTEIL, MassDensity: 500 kg/m3; ALLGEMEIN - BAUTEIL, Embodied Energy: 13.1 (MJ/kg); ALLGEMEIN - BAUTEIL, Embodied Carbon: 0.64 (kgCO₂/kg); ALLGEMEIN - BAUTEIL, Name: ALLGEMEIN - BAUTEIL; ALLGEMEIN - BAUTEIL, Participates in Collision Detection: yes
Decke003 | Erdgeschoss | ALLGEMEIN - BAUTEIL | Material Properties - ALLGEMEIN - BAUTEIL, ThermalConductivity: 0.13; ALLGEMEIN - BAUTEIL, SpecificHeatCapacity: 1600 J/kg/K; ALLGEMEIN - BAUTEIL, MassDensity: 500 kg/m3; ALLGEMEIN - BAUTEIL, Embodied Energy: 13.1 (MJ/kg); ALLGEMEIN - BAUTEIL, Embodied Carbon: 0.64 (kgCO₂/kg); ALLGEMEIN - BAUTEIL, Name: ALLGEMEIN - BAUTEIL; ALLGEMEIN - BAUTEIL, Participates in Collision Detection: yes
Decke031 | Erdgeschoss | ALLGEMEIN - NIEDRIGE PRIORITÄT | 0 | 0 (MJ/kg) | 0 (kgCO₂/kg) | ALLGEMEIN - NIEDRIGE PRIORITÄT | yes
Decke042 | Erdgeschoss | ALLGEMEIN - NIEDRIGE PRIORITÄT | 0 | 0 (MJ/kg) | 0 (kgCO₂/kg) | ALLGEMEIN - NIEDRIGE PRIORITÄT | yes
Decke044 | Erdgeschoss | ALLGEMEIN - NIEDRIGE PRIORITÄT | 0 | 0 (MJ/kg) | 0 (kgCO₂/kg) | ALLGEMEIN - NIEDRIGE PRIORITÄT | yes
Decke045 | Erdgeschoss | ALLGEMEIN - NIEDRIGE PRIORITÄT | 0 | 0 (MJ/kg) | 0 (kgCO₂/kg) | ALLGEMEIN - NIEDRIGE PRIORITÄT | yes
Decke046 | Erdgeschoss | ALLGEMEIN - NIEDRIGE PRIORITÄT | 0 | 0 (MJ/kg) | 0 (kgCO₂/kg) | ALLGEMEIN - NIEDRIGE PRIORITÄT | yes
Decke043 | Erdgeschoss | ALLGEMEIN - NIEDRIGE PRIORITÄT | 0 | 0 (MJ/kg) | 0 (kgCO₂/kg) | ALLGEMEIN - NIEDRIGE PRIORITÄT | yes
Decke047 | Erdgeschoss | ALLGEMEIN - NIEDRIGE PRIORITÄT | 0 | 0 (MJ/kg) | 0 (kgCO₂/kg) | ALLGEMEIN - NIEDRIGE PRIORITÄT | yes
Decke048 | Erdgeschoss | ALLGEMEIN - NIEDRIGE PRIORITÄT | 0 | 0 (MJ/kg) | 0 (kgCO₂/kg) | ALLGEMEIN - NIEDRIGE PRIORITÄT | yes
Decke049 | Erdgeschoss | ALLGEMEIN - NIEDRIGE PRIORITÄT | 0 | 0 (MJ/kg) | 0 (kgCO₂/kg) | ALLGEMEIN - NIEDRIGE PRIORITÄT | yes
Decke050 | Erdgeschoss | ALLGEMEIN - NIEDRIGE PRIORITÄT | 0 | 0 (MJ/kg) | 0 (kgCO₂/kg) | ALLGEMEIN - NIEDRIGE PRIORITÄT | yes
Decke051 | Erdgeschoss | ALLGEMEIN - NIEDRIGE PRIORITÄT | 0 | 0 (MJ/kg) | 0 (kgCO₂/kg) | ALLGEMEIN - NIEDRIGE PRIORITÄT | yes
Treppe-001 | Erdgeschoss | Metall, Stahl lackiert | Pset_StairCommon - NumberOfRiser: 18; NumberOfTreads: 17; RiserHeight: 0.182 m; RequiredHeadroom: 2.2 m; IsExternal: no; Material Properties - Metall, Stahl lackiert, ThermalConductivity: 50; Metall, Stahl lackiert, SpecificHeatCapacity: 450 J/kg/K; Metall, Stahl lackiert, MassDensity: 7800 kg/m3; Metall, Stahl lackiert, Embodied Energy: 20.1 (MJ/kg); Metall, Stahl lackiert, Embodied Carbon: 1.46 (kgCO₂/kg); Metall, Stahl lackiert, Name: Metall, Stahl lackiert; Metall, Stahl lackiert, Participates in Collision Detection: yes

# IfcTransportElement: Glas, Normalglas 10 (6)
Type - PredefinedType: ELEVATOR
Classification: Aufzug (Archicad Klassifizierung); Material: Glas, Normalglas
Pset_FireRatingProperties - FireResistanceRating: -
AC_Pset_RenovationAndPhasing - Renovation Status: Existing
Material Properties - Glas, Normalglas, ThermalConductivity: 1.4; Glas, Normalglas, SpecificHeatCapacity: 750 J/kg/K; Glas, Normalglas, MassDensity: 2200 kg/m3; Glas, Normalglas, Embodied Energy: 0.85 (MJ/kg); Glas, Normalglas, Embodied Carbon: 0.02 (kgCO₂/kg); Glas, Normalglas, Name: Glas, Normalglas; Glas, Normalglas, Participates in Collision Detection: yes
Name | In
Aufzug3 | Erdgeschoss
Aufzug2 | Erdgeschoss
Aufzug1 | Erdgeschoss
Aufzug6 | Staffelgeschoss
Aufzug4 | Staffelgeschoss
Aufzug5 | Staffelgeschoss

# IfcTransportElement: Teleskoptür 22 (2)
Type - PredefinedType: ELEVATOR
Classification: Aufzug (Archicad Klassifizierung)
Pset_FireRatingProperties - FireResistanceRating: -
AC_Pset_RenovationAndPhasing - Renovation Status: Existing
Name | In
Tür-011 | Erdgeschoss
Tür-011 | Staffelgeschoss

# IfcWall: Wandabschluss 02 26 (2)
In: Staffelgeschoss
Type - PredefinedType: PLUMBINGWALL
Classification: Vorwand / Installationswand (Archicad Klassifizierung); Material: _SIWH - Gipskarton
Material Properties - _SIWH - Gipskarton, ThermalConductivity: 0.25; _SIWH - Gipskarton, SpecificHeatCapacity: 1000 J/kg/K; _SIWH - Gipskarton, MassDensity: 900 kg/m3; _SIWH - Gipskarton, Embodied Energy: 6.75 (MJ/kg); _SIWH - Gipskarton, Embodied Carbon: 0.39 (kgCO₂/kg); _SIWH - Gipskarton, Name: _SIWH - Gipskarton; _SIWH - Gipskarton, Participates in Collision Detection: yes
AC_Pset_RenovationAndPhasing - Renovation Status: Existing
Pset_FireRatingProperties - FireResistanceRating: -
Pset_WallCommon - FireRating: -

# IfcWall: _SIWH - Attika 1.OG 635 x 625 (4)
In: Dachaufsicht
Classification: Wand (Archicad Klassifizierung); Material: _SIWH - Dämmung, weich Mineralwolle, _SIWH - Dämmung, hart Mineralwolle, _SIWH - MW Vormauerziegel, _SIWH - Beton, Stahlbeton, _SIWH - Luftschicht vertikal, _SIWH - Holz, Bauholz, _SIWH - Metall, Aluminium
Pset_WallCommon - FireRating: -; IsExternal: yes; LoadBearing: yes
Pset_FireRatingProperties - FireResistanceRating: -
AC_Pset_RenovationAndPhasing - Renovation Status: Existing
Material Properties - _SIWH - Dämmung, weich Mineralwolle, ThermalConductivity: 0.037; _SIWH - Dämmung, weich Mineralwolle, SpecificHeatCapacity: 840 J/kg/K; _SIWH - Dämmung, weich Mineralwolle, MassDensity: 40 kg/m3; _SIWH - Dämmung, weich Mineralwolle, Embodied Energy: 14.3 (MJ/kg); _SIWH - Dämmung, weich Mineralwolle, Embodied Carbon: 1.08 (kgCO₂/kg); _SIWH - Dämmung, weich Mineralwolle, Name: _SIWH - Dämmung, weich Mineralwolle; _SIWH - Dämmung, weich Mineralwolle, Participates in Collision Detection: yes; _SIWH - Dämmung, hart Mineralwolle, ThermalConductivity: 0.036; _SIWH - Dämmung, hart Mineralwolle, SpecificHeatCapacity: 840 J/kg/K; _SIWH - Dämmung, hart Mineralwolle, MassDensity: 115 kg/m3; _SIWH - Dämmung, hart Mineralwolle, Embodied Energy: 21.4 (MJ/kg); _SIWH - Dämmung, hart Mineralwolle, Embodied Carbon: 1.69 (kgCO₂/kg); _SIWH - Dämmung, hart Mineralwolle, Name: _SIWH - Dämmung, hart Mineralwolle; _SIWH - Dämmung, hart Mineralwolle, Participates in Collision Detection: yes; _SIWH - MW Vormauerziegel, ThermalConductivity: 0.109; _SIWH - MW Vormauerziegel, SpecificHeatCapacity: 920 J/kg/K; _SIWH - MW Vormauerziegel, MassDensity: 600 kg/m3; _SIWH - MW Vormauerziegel, Embodied Energy: 6 (MJ/kg); _SIWH - MW Vormauerziegel, Embodied Carbon: 0.48 (kgCO₂/kg); _SIWH - MW Vormauerziegel, Name: _SIWH - MW Vormauerziegel; _SIWH - MW Vormauerziegel, Participates in Collision Detection: yes; _SIWH - Beton, Stahlbeton, ThermalConductivity: 1.35; _SIWH - Beton, Stahlbeton, SpecificHeatCapacity: 1000 J/kg/K; _SIWH - Beton, Stahlbeton, MassDensity: 2000 kg/m3; _SIWH - Beton, Stahlbeton, Embodied Energy: 0.78 (MJ/kg); _SIWH - Beton, Stahlbeton, Embodied Carbon: 0.113 (kgCO₂/kg); _SIWH - Beton, Stahlbeton, Name: _SIWH - Beton, Stahlbeton; _SIWH - Beton, Stahlbeton, Participates in Collision Detection: yes; _SIWH - Luftschicht vertikal, ThermalConductivity: 0.16; _SIWH - Luftschicht vertikal, SpecificHeatCapacity: 1008 J/kg/K; _SIWH - Luftschicht vertikal, MassDensity: 1.2 kg/m3; _SIWH - Luftschicht vertikal, Embodied Energy: 0 (MJ/kg); _SIWH - Luftschicht vertikal, Embodied Carbon: 0 (kgCO₂/kg); _SIWH - Luftschicht vertikal, Name: _SIWH - Luftschicht vertikal; _SIWH - Luftschicht vertikal, Participates in Collision Detection: no; _SIWH - Holz, Bauholz, ThermalConductivity: 0.13; _SIWH - Holz, Bauholz, SpecificHeatCapacity: 1600 J/kg/K; _SIWH - Holz, Bauholz, MassDensity: 500 kg/m3; _SIWH - Holz, Bauholz, Embodied Energy: 6.95 (MJ/kg); _SIWH - Holz, Bauholz, Embodied Carbon: 0.29 (kgCO₂/kg); _SIWH - Holz, Bauholz, Name: _SIWH - Holz, Bauholz; _SIWH - Holz, Bauholz, Participates in Collision Detection: yes; _SIWH - Metall, Aluminium, ThermalConductivity: 160; _SIWH - Metall, Aluminium, SpecificHeatCapacity: 880 J/kg/K; _SIWH - Metall, Aluminium, MassDensity: 2800 kg/m3; _SIWH - Metall, Aluminium, Embodied Energy: 155 (MJ/kg); _SIWH - Metall, Aluminium, Embodied Carbon: 9.16 (kgCO₂/kg); _SIWH - Metall, Aluminium, Name: _SIWH - Metall, Aluminium; _SIWH - Metall, Aluminium, Participates in Collision Detection: yes
Name
A-Wand031
A-Wand030
A-Wand033
A-Wand032

# IfcWall: _SIWH - Attikablech2 Achse3 EG 660 x 65, Wand-028
In: Staffelgeschoss
Classification: Wand (Archicad Klassifizierung); Material: _SIWH - Metall, Aluminium
Pset_WallCommon - FireRating: -; IsExternal: yes; LoadBearing: yes
AC_Pset_RenovationAndPhasing - Renovation Status: Existing
Pset_FireRatingProperties - FireResistanceRating: -
Material Properties - _SIWH - Metall, Aluminium, ThermalConductivity: 160; _SIWH - Metall, Aluminium, SpecificHeatCapacity: 880 J/kg/K; _SIWH - Metall, Aluminium, MassDensity: 2800 kg/m3; _SIWH - Metall, Aluminium, Embodied Energy: 155 (MJ/kg); _SIWH - Metall, Aluminium, Embodied Carbon: 9.16 (kgCO₂/kg); _SIWH - Metall, Aluminium, Name: _SIWH - Metall, Aluminium; _SIWH - Metall, Aluminium, Participates in Collision Detection: yes

# IfcWall: _SIWH - Beton, Stahlbeton 240 x 930, Unterzug-014
In: Erdgeschoss
Classification: Wand (Archicad Klassifizierung); Material: _SIWH - Beton, Stahlbeton
Pset_WallCommon - FireRating: -; IsExternal: yes; LoadBearing: yes
Pset_FireRatingProperties - FireResistanceRating: -
AC_Pset_RenovationAndPhasing - Renovation Status: Existing
Material Properties - _SIWH - Beton, Stahlbeton, ThermalConductivity: 1.35; _SIWH - Beton, Stahlbeton, SpecificHeatCapacity: 1000 J/kg/K; _SIWH - Beton, Stahlbeton, MassDensity: 2000 kg/m3; _SIWH - Beton, Stahlbeton, Embodied Energy: 0.78 (MJ/kg); _SIWH - Beton, Stahlbeton, Embodied Carbon: 0.113 (kgCO₂/kg); _SIWH - Beton, Stahlbeton, Name: _SIWH - Beton, Stahlbeton; _SIWH - Beton, Stahlbeton, Participates in Collision Detection: yes

# IfcWall: _SIWH - Beton, Stahlbeton Fertigteil 70, Decke025
In: Kellergeschoss
Type - PredefinedType: ELEMENTEDWALL
Classification: Elementwand (Archicad Klassifizierung); Material: _SIWH - Beton, Stahlbeton Fertigteil
Pset_WallCommon - FireRating: -; IsExternal: yes; LoadBearing: no
Pset_FireRatingProperties - FireResistanceRating: -
AC_Pset_RenovationAndPhasing - Renovation Status: Existing
Material Properties - _SIWH - Beton, Stahlbeton Fertigteil, ThermalConductivity: 1.15; _SIWH - Beton, Stahlbeton Fertigteil, SpecificHeatCapacity: 1000 J/kg/K; _SIWH - Beton, Stahlbeton Fertigteil, MassDensity: 1800 kg/m3; _SIWH - Beton, Stahlbeton Fertigteil, Embodied Energy: 0.74 (MJ/kg); _SIWH - Beton, Stahlbeton Fertigteil, Embodied Carbon: 0.107 (kgCO₂/kg); _SIWH - Beton, Stahlbeton Fertigteil, Name: _SIWH - Beton, Stahlbeton Fertigteil; _SIWH - Beton, Stahlbeton Fertigteil, Participates in Collision Detection: yes

# IfcWall: _SIWH - Dämmung, hart Mineralwolle 70, Decke024
In: Kellergeschoss
Type - PredefinedType: ELEMENTEDWALL
Classification: Elementwand (Archicad Klassifizierung); Material: _SIWH - Dämmung, hart Mineralwolle
Pset_WallCommon - FireRating: -; IsExternal: yes; LoadBearing: no
Pset_FireRatingProperties - FireResistanceRating: -
AC_Pset_RenovationAndPhasing - Renovation Status: Existing
Material Properties - _SIWH - Dämmung, hart Mineralwolle, ThermalConductivity: 0.036; _SIWH - Dämmung, hart Mineralwolle, SpecificHeatCapacity: 840 J/kg/K; _SIWH - Dämmung, hart Mineralwolle, MassDensity: 115 kg/m3; _SIWH - Dämmung, hart Mineralwolle, Embodied Energy: 21.4 (MJ/kg); _SIWH - Dämmung, hart Mineralwolle, Embodied Carbon: 1.69 (kgCO₂/kg); _SIWH - Dämmung, hart Mineralwolle, Name: _SIWH - Dämmung, hart Mineralwolle; _SIWH - Dämmung, hart Mineralwolle, Participates in Collision Detection: yes

# IfcWall: _SIWH - Sturz Außenwand EG - Stb. 20cm 515 x 280, A-Wand020
In: Erdgeschoss
Classification: Wand (Archicad Klassifizierung); Material: _SIWH - Dämmung, weich Mineralwolle, _SIWH - Beton, Stahlbeton, _SIWH - MW Vormauerziegel, _SIWH - Luftschicht vertikal
Pset_WallCommon - FireRating: -; IsExternal: yes; LoadBearing: yes
AC_Pset_RenovationAndPhasing - Renovation Status: Existing
Pset_FireRatingProperties - FireResistanceRating: -
Material Properties - _SIWH - Dämmung, weich Mineralwolle, ThermalConductivity: 0.037; _SIWH - Dämmung, weich Mineralwolle, SpecificHeatCapacity: 840 J/kg/K; _SIWH - Dämmung, weich Mineralwolle, MassDensity: 40 kg/m3; _SIWH - Dämmung, weich Mineralwolle, Embodied Energy: 14.3 (MJ/kg); _SIWH - Dämmung, weich Mineralwolle, Embodied Carbon: 1.08 (kgCO₂/kg); _SIWH - Dämmung, weich Mineralwolle, Name: _SIWH - Dämmung, weich Mineralwolle; _SIWH - Dämmung, weich Mineralwolle, Participates in Collision Detection: yes; _SIWH - Beton, Stahlbeton, ThermalConductivity: 1.35; _SIWH - Beton, Stahlbeton, SpecificHeatCapacity: 1000 J/kg/K; _SIWH - Beton, Stahlbeton, MassDensity: 2000 kg/m3; _SIWH - Beton, Stahlbeton, Embodied Energy: 0.78 (MJ/kg); _SIWH - Beton, Stahlbeton, Embodied Carbon: 0.113 (kgCO₂/kg); _SIWH - Beton, Stahlbeton, Name: _SIWH - Beton, Stahlbeton; _SIWH - Beton, Stahlbeton, Participates in Collision Detection: yes; _SIWH - MW Vormauerziegel, ThermalConductivity: 0.109; _SIWH - MW Vormauerziegel, SpecificHeatCapacity: 920 J/kg/K; _SIWH - MW Vormauerziegel, MassDensity: 600 kg/m3; _SIWH - MW Vormauerziegel, Embodied Energy: 6 (MJ/kg); _SIWH - MW Vormauerziegel, Embodied Carbon: 0.48 (kgCO₂/kg); _SIWH - MW Vormauerziegel, Name: _SIWH - MW Vormauerziegel; _SIWH - MW Vormauerziegel, Participates in Collision Detection: yes; _SIWH - Luftschicht vertikal, ThermalConductivity: 0.16; _SIWH - Luftschicht vertikal, SpecificHeatCapacity: 1008 J/kg/K; _SIWH - Luftschicht vertikal, MassDensity: 1.2 kg/m3; _SIWH - Luftschicht vertikal, Embodied Energy: 0 (MJ/kg); _SIWH - Luftschicht vertikal, Embodied Carbon: 0 (kgCO₂/kg); _SIWH - Luftschicht vertikal, Name: _SIWH - Luftschicht vertikal; _SIWH - Luftschicht vertikal, Participates in Collision Detection: no

# IfcWall: _SIWH - Sturz Außenwand EG 555 x 330 (5)
In: Erdgeschoss
Classification: Wand (Archicad Klassifizierung); Material: _SIWH - Dämmung, weich Mineralwolle, _SIWH - Beton, Stahlbeton, _SIWH - MW Vormauerziegel, _SIWH - Luftschicht vertikal
Pset_WallCommon - FireRating: -; IsExternal: yes; LoadBearing: yes
Pset_FireRatingProperties - FireResistanceRating: -
AC_Pset_RenovationAndPhasing - Renovation Status: Existing
Material Properties - _SIWH - Dämmung, weich Mineralwolle, ThermalConductivity: 0.037; _SIWH - Dämmung, weich Mineralwolle, SpecificHeatCapacity: 840 J/kg/K; _SIWH - Dämmung, weich Mineralwolle, MassDensity: 40 kg/m3; _SIWH - Dämmung, weich Mineralwolle, Embodied Energy: 14.3 (MJ/kg); _SIWH - Dämmung, weich Mineralwolle, Embodied Carbon: 1.08 (kgCO₂/kg); _SIWH - Dämmung, weich Mineralwolle, Name: _SIWH - Dämmung, weich Mineralwolle; _SIWH - Dämmung, weich Mineralwolle, Participates in Collision Detection: yes; _SIWH - Beton, Stahlbeton, ThermalConductivity: 1.35; _SIWH - Beton, Stahlbeton, SpecificHeatCapacity: 1000 J/kg/K; _SIWH - Beton, Stahlbeton, MassDensity: 2000 kg/m3; _SIWH - Beton, Stahlbeton, Embodied Energy: 0.78 (MJ/kg); _SIWH - Beton, Stahlbeton, Embodied Carbon: 0.113 (kgCO₂/kg); _SIWH - Beton, Stahlbeton, Name: _SIWH - Beton, Stahlbeton; _SIWH - Beton, Stahlbeton, Participates in Collision Detection: yes; _SIWH - MW Vormauerziegel, ThermalConductivity: 0.109; _SIWH - MW Vormauerziegel, SpecificHeatCapacity: 920 J/kg/K; _SIWH - MW Vormauerziegel, MassDensity: 600 kg/m3; _SIWH - MW Vormauerziegel, Embodied Energy: 6 (MJ/kg); _SIWH - MW Vormauerziegel, Embodied Carbon: 0.48 (kgCO₂/kg); _SIWH - MW Vormauerziegel, Name: _SIWH - MW Vormauerziegel; _SIWH - MW Vormauerziegel, Participates in Collision Detection: yes; _SIWH - Luftschicht vertikal, ThermalConductivity: 0.16; _SIWH - Luftschicht vertikal, SpecificHeatCapacity: 1008 J/kg/K; _SIWH - Luftschicht vertikal, MassDensity: 1.2 kg/m3; _SIWH - Luftschicht vertikal, Embodied Energy: 0 (MJ/kg); _SIWH - Luftschicht vertikal, Embodied Carbon: 0 (kgCO₂/kg); _SIWH - Luftschicht vertikal, Name: _SIWH - Luftschicht vertikal; _SIWH - Luftschicht vertikal, Participates in Collision Detection: no
Name
A-Wand010
A-Wand009
A-Wand016
A-Wand013
A-Wand041

# IfcWall: _SIWH - Sturz Außenwand EG Garage 615 x 280 (2)
In: Erdgeschoss
Classification: Wand (Archicad Klassifizierung); Material: _SIWH - Dämmung, weich Mineralwolle, _SIWH - Beton, Stahlbeton, _SIWH - MW Vormauerziegel, _SIWH - Luftschicht vertikal
Pset_WallCommon - FireRating: -; IsExternal: yes; LoadBearing: yes
Pset_FireRatingProperties - FireResistanceRating: -
AC_Pset_RenovationAndPhasing - Renovation Status: Existing
Material Properties - _SIWH - Dämmung, weich Mineralwolle, ThermalConductivity: 0.037; _SIWH - Dämmung, weich Mineralwolle, SpecificHeatCapacity: 840 J/kg/K; _SIWH - Dämmung, weich Mineralwolle, MassDensity: 40 kg/m3; _SIWH - Dämmung, weich Mineralwolle, Embodied Energy: 14.3 (MJ/kg); _SIWH - Dämmung, weich Mineralwolle, Embodied Carbon: 1.08 (kgCO₂/kg); _SIWH - Dämmung, weich Mineralwolle, Name: _SIWH - Dämmung, weich Mineralwolle; _SIWH - Dämmung, weich Mineralwolle, Participates in Collision Detection: yes; _SIWH - Beton, Stahlbeton, ThermalConductivity: 1.35; _SIWH - Beton, Stahlbeton, SpecificHeatCapacity: 1000 J/kg/K; _SIWH - Beton, Stahlbeton, MassDensity: 2000 kg/m3; _SIWH - Beton, Stahlbeton, Embodied Energy: 0.78 (MJ/kg); _SIWH - Beton, Stahlbeton, Embodied Carbon: 0.113 (kgCO₂/kg); _SIWH - Beton, Stahlbeton, Name: _SIWH - Beton, Stahlbeton; _SIWH - Beton, Stahlbeton, Participates in Collision Detection: yes; _SIWH - MW Vormauerziegel, ThermalConductivity: 0.109; _SIWH - MW Vormauerziegel, SpecificHeatCapacity: 920 J/kg/K; _SIWH - MW Vormauerziegel, MassDensity: 600 kg/m3; _SIWH - MW Vormauerziegel, Embodied Energy: 6 (MJ/kg); _SIWH - MW Vormauerziegel, Embodied Carbon: 0.48 (kgCO₂/kg); _SIWH - MW Vormauerziegel, Name: _SIWH - MW Vormauerziegel; _SIWH - MW Vormauerziegel, Participates in Collision Detection: yes; _SIWH - Luftschicht vertikal, ThermalConductivity: 0.16; _SIWH - Luftschicht vertikal, SpecificHeatCapacity: 1008 J/kg/K; _SIWH - Luftschicht vertikal, MassDensity: 1.2 kg/m3; _SIWH - Luftschicht vertikal, Embodied Energy: 0 (MJ/kg); _SIWH - Luftschicht vertikal, Embodied Carbon: 0 (kgCO₂/kg); _SIWH - Luftschicht vertikal, Name: _SIWH - Luftschicht vertikal; _SIWH - Luftschicht vertikal, Participates in Collision Detection: no
Name
A-Wand019
A-Wand018

# IfcWall: _SIWH - Sturz Außenwand EG Vordach 555 x 280 (2)
In: Erdgeschoss
Classification: Wand (Archicad Klassifizierung); Material: _SIWH - Dämmung, weich Mineralwolle, _SIWH - Beton, Stahlbeton, _SIWH - MW Vormauerziegel, _SIWH - Luftschicht vertikal
Pset_FireRatingProperties - FireResistanceRating: -
Material Properties - _SIWH - Dämmung, weich Mineralwolle, ThermalConductivity: 0.037; _SIWH - Dämmung, weich Mineralwolle, SpecificHeatCapacity: 840 J/kg/K; _SIWH - Dämmung, weich Mineralwolle, MassDensity: 40 kg/m3; _SIWH - Dämmung, weich Mineralwolle, Embodied Energy: 14.3 (MJ/kg); _SIWH - Dämmung, weich Mineralwolle, Embodied Carbon: 1.08 (kgCO₂/kg); _SIWH - Dämmung, weich Mineralwolle, Name: _SIWH - Dämmung, weich Mineralwolle; _SIWH - Dämmung, weich Mineralwolle, Participates in Collision Detection: yes; _SIWH - Beton, Stahlbeton, ThermalConductivity: 1.35; _SIWH - Beton, Stahlbeton, SpecificHeatCapacity: 1000 J/kg/K; _SIWH - Beton, Stahlbeton, MassDensity: 2000 kg/m3; _SIWH - Beton, Stahlbeton, Embodied Energy: 0.78 (MJ/kg); _SIWH - Beton, Stahlbeton, Embodied Carbon: 0.113 (kgCO₂/kg); _SIWH - Beton, Stahlbeton, Name: _SIWH - Beton, Stahlbeton; _SIWH - Beton, Stahlbeton, Participates in Collision Detection: yes; _SIWH - MW Vormauerziegel, ThermalConductivity: 0.109; _SIWH - MW Vormauerziegel, SpecificHeatCapacity: 920 J/kg/K; _SIWH - MW Vormauerziegel, MassDensity: 600 kg/m3; _SIWH - MW Vormauerziegel, Embodied Energy: 6 (MJ/kg); _SIWH - MW Vormauerziegel, Embodied Carbon: 0.48 (kgCO₂/kg); _SIWH - MW Vormauerziegel, Name: _SIWH - MW Vormauerziegel; _SIWH - MW Vormauerziegel, Participates in Collision Detection: yes; _SIWH - Luftschicht vertikal, ThermalConductivity: 0.16; _SIWH - Luftschicht vertikal, SpecificHeatCapacity: 1008 J/kg/K; _SIWH - Luftschicht vertikal, MassDensity: 1.2 kg/m3; _SIWH - Luftschicht vertikal, Embodied Energy: 0 (MJ/kg); _SIWH - Luftschicht vertikal, Embodied Carbon: 0 (kgCO₂/kg); _SIWH - Luftschicht vertikal, Name: _SIWH - Luftschicht vertikal; _SIWH - Luftschicht vertikal, Participates in Collision Detection: no
AC_Pset_RenovationAndPhasing - Renovation Status: Existing
Pset_WallCommon - FireRating: -; IsExternal: yes; LoadBearing: yes
Name
A-Wand022
A-Wand017

# IfcWall: _SIWH - Terrasse Luftbalken 140 x 915 (2)
In: Staffelgeschoss
Classification: Wand (Archicad Klassifizierung); Material: _SIWH - Beton, Stahlbeton Fertigteil
Pset_WallCommon - FireRating: -; IsExternal: yes; LoadBearing: no
Pset_FireRatingProperties - FireResistanceRating: -
AC_Pset_RenovationAndPhasing - Renovation Status: Existing
Material Properties - _SIWH - Beton, Stahlbeton Fertigteil, ThermalConductivity: 1.15; _SIWH - Beton, Stahlbeton Fertigteil, SpecificHeatCapacity: 1000 J/kg/K; _SIWH - Beton, Stahlbeton Fertigteil, MassDensity: 1800 kg/m3; _SIWH - Beton, Stahlbeton Fertigteil, Embodied Energy: 0.74 (MJ/kg); _SIWH - Beton, Stahlbeton Fertigteil, Embodied Carbon: 0.107 (kgCO₂/kg); _SIWH - Beton, Stahlbeton Fertigteil, Name: _SIWH - Beton, Stahlbeton Fertigteil; _SIWH - Beton, Stahlbeton Fertigteil, Participates in Collision Detection: yes

# IfcWall: _SIWH - WA | Stb. 20+WD 18+LS 2+Verblender 11,5 | 51,5cm 515, A-Wand043
In: Staffelgeschoss
Classification: Wand (Archicad Klassifizierung); Material: _SIWH - Beton, Stahlbeton, _SIWH - Dämmung, weich Mineralwolle, _SIWH - Luftschicht vertikal, _SIWH - MW Vormauerziegel
Pset_FireRatingProperties - FireResistanceRating: -
Pset_WallCommon - FireRating: -; IsExternal: yes; LoadBearing: yes
Material Properties - _SIWH - Beton, Stahlbeton, ThermalConductivity: 1.35; _SIWH - Beton, Stahlbeton, SpecificHeatCapacity: 1000 J/kg/K; _SIWH - Beton, Stahlbeton, MassDensity: 2000 kg/m3; _SIWH - Beton, Stahlbeton, Embodied Energy: 0.78 (MJ/kg); _SIWH - Beton, Stahlbeton, Embodied Carbon: 0.113 (kgCO₂/kg); _SIWH - Beton, Stahlbeton, Name: _SIWH - Beton, Stahlbeton; _SIWH - Beton, Stahlbeton, Participates in Collision Detection: yes; _SIWH - Dämmung, weich Mineralwolle, ThermalConductivity: 0.037; _SIWH - Dämmung, weich Mineralwolle, SpecificHeatCapacity: 840 J/kg/K; _SIWH - Dämmung, weich Mineralwolle, MassDensity: 40 kg/m3; _SIWH - Dämmung, weich Mineralwolle, Embodied Energy: 14.3 (MJ/kg); _SIWH - Dämmung, weich Mineralwolle, Embodied Carbon: 1.08 (kgCO₂/kg); _SIWH - Dämmung, weich Mineralwolle, Name: _SIWH - Dämmung, weich Mineralwolle; _SIWH - Dämmung, weich Mineralwolle, Participates in Collision Detection: yes; _SIWH - Luftschicht vertikal, ThermalConductivity: 0.16; _SIWH - Luftschicht vertikal, SpecificHeatCapacity: 1008 J/kg/K; _SIWH - Luftschicht vertikal, MassDensity: 1.2 kg/m3; _SIWH - Luftschicht vertikal, Embodied Energy: 0 (MJ/kg); _SIWH - Luftschicht vertikal, Embodied Carbon: 0 (kgCO₂/kg); _SIWH - Luftschicht vertikal, Name: _SIWH - Luftschicht vertikal; _SIWH - Luftschicht vertikal, Participates in Collision Detection: no; _SIWH - MW Vormauerziegel, ThermalConductivity: 0.109; _SIWH - MW Vormauerziegel, SpecificHeatCapacity: 920 J/kg/K; _SIWH - MW Vormauerziegel, MassDensity: 600 kg/m3; _SIWH - MW Vormauerziegel, Embodied Energy: 6 (MJ/kg); _SIWH - MW Vormauerziegel, Embodied Carbon: 0.48 (kgCO₂/kg); _SIWH - MW Vormauerziegel, Name: _SIWH - MW Vormauerziegel; _SIWH - MW Vormauerziegel, Participates in Collision Detection: yes
AC_Pset_RenovationAndPhasing - Renovation Status: Existing

# IfcWallStandardCase: ALLGEMEIN - BAUTEIL 125, L-Wand036
In: Erdgeschoss
Type - PredefinedType: PLUMBINGWALL
Classification: Vorwand / Installationswand (Archicad Klassifizierung); Material: ALLGEMEIN - BAUTEIL 0.125 m
Pset_WallCommon - FireRating: -; IsExternal: no; LoadBearing: no
Pset_FireRatingProperties - FireResistanceRating: -
Material Properties - ALLGEMEIN - BAUTEIL, ThermalConductivity: 0.13; ALLGEMEIN - BAUTEIL, SpecificHeatCapacity: 1600 J/kg/K; ALLGEMEIN - BAUTEIL, MassDensity: 500 kg/m3; ALLGEMEIN - BAUTEIL, Embodied Energy: 13.1 (MJ/kg); ALLGEMEIN - BAUTEIL, Embodied Carbon: 0.64 (kgCO₂/kg); ALLGEMEIN - BAUTEIL, Name: ALLGEMEIN - BAUTEIL; ALLGEMEIN - BAUTEIL, Participates in Collision Detection: yes
AC_Pset_RenovationAndPhasing - Renovation Status: Existing

# IfcWallStandardCase: ALLGEMEIN - BAUTEIL 50 (2)
In: Staffelgeschoss
Classification: Wand (Archicad Klassifizierung); Material: ALLGEMEIN - BAUTEIL 0.05 m
Pset_WallCommon - FireRating: -; IsExternal: no; LoadBearing: no
Pset_FireRatingProperties - FireResistanceRating: -
AC_Pset_RenovationAndPhasing - Renovation Status: Existing
Material Properties - ALLGEMEIN - BAUTEIL, ThermalConductivity: 0.13; ALLGEMEIN - BAUTEIL, SpecificHeatCapacity: 1600 J/kg/K; ALLGEMEIN - BAUTEIL, MassDensity: 500 kg/m3; ALLGEMEIN - BAUTEIL, Embodied Energy: 13.1 (MJ/kg); ALLGEMEIN - BAUTEIL, Embodied Carbon: 0.64 (kgCO₂/kg); ALLGEMEIN - BAUTEIL, Name: ALLGEMEIN - BAUTEIL; ALLGEMEIN - BAUTEIL, Participates in Collision Detection: yes
Name
I-Wand034
I-Wand035
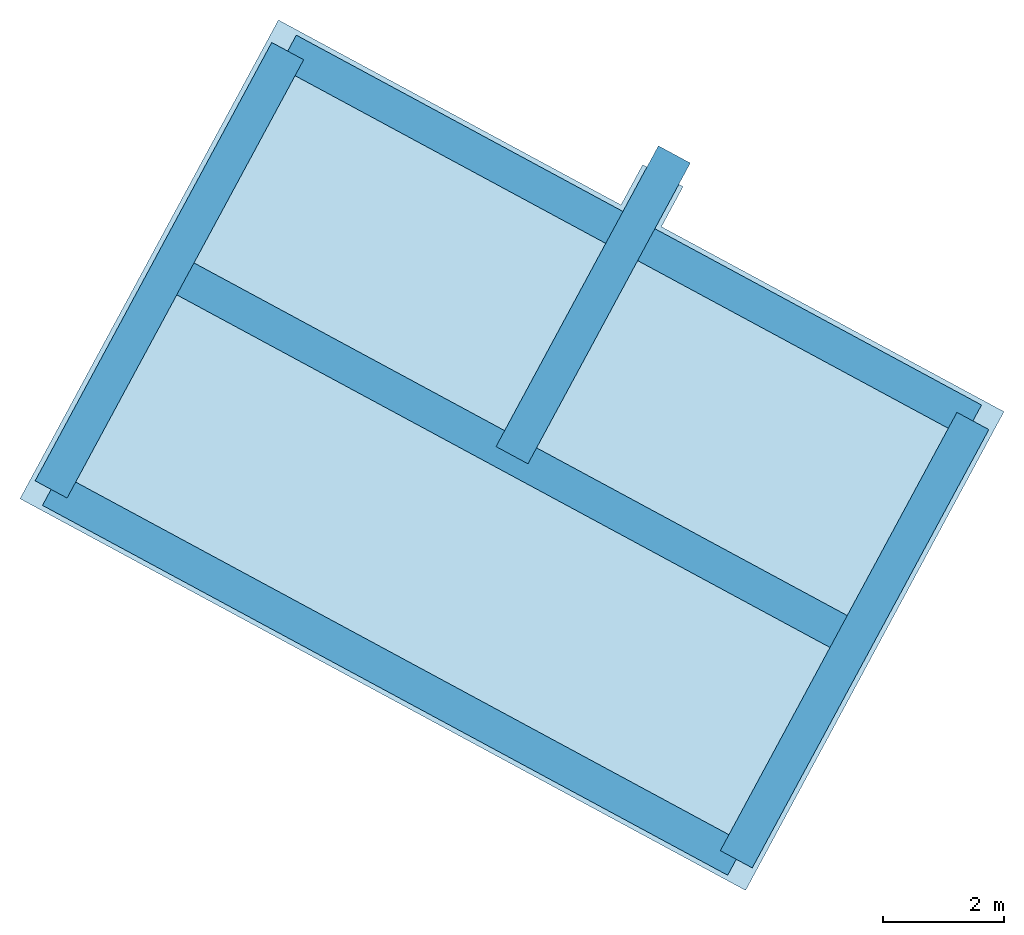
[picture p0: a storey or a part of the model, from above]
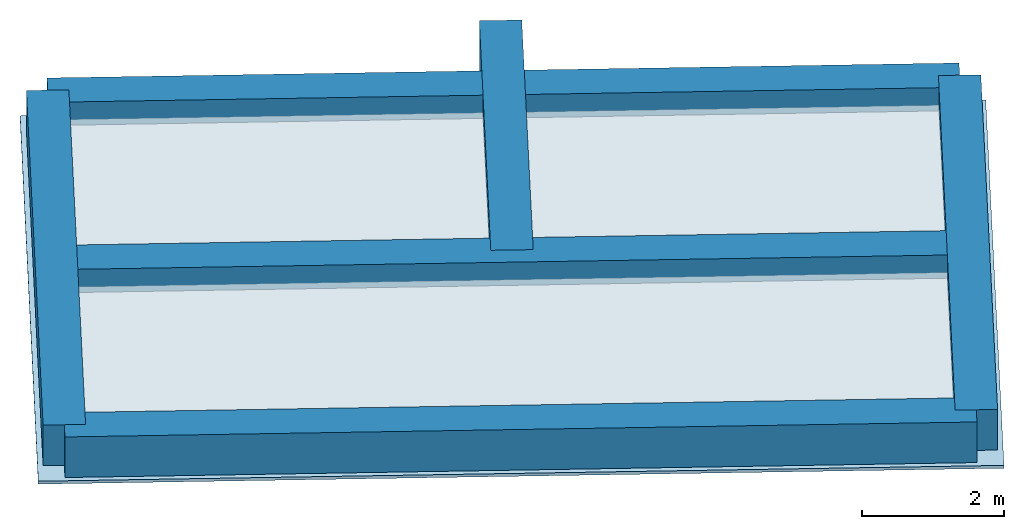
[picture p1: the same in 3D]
Properties of the parts of a building model (IFC2X3), part 3 of 3

# IfcWallStandardCase: Glas, Normalglas-50% durchlässig 30, L-Wand033
In: Staffelgeschoss
Type - ElementType: PARTITIONING; PredefinedType: USERDEFINED
Classification: Trennwand (Archicad Klassifizierung); Material: Glas, Normalglas-50% durchlässig 0.03 m
Pset_WallCommon - FireRating: -; IsExternal: no; LoadBearing: no
Pset_FireRatingProperties - FireResistanceRating: -
AC_Pset_RenovationAndPhasing - Renovation Status: Existing
Material Properties - Glas, Normalglas-50% durchlässig, ThermalConductivity: 1.4; Glas, Normalglas-50% durchlässig, SpecificHeatCapacity: 750 J/kg/K; Glas, Normalglas-50% durchlässig, MassDensity: 2200 kg/m3; Glas, Normalglas-50% durchlässig, Embodied Energy: 0.85 (MJ/kg); Glas, Normalglas-50% durchlässig, Embodied Carbon: 0.02 (kgCO₂/kg); Glas, Normalglas-50% durchlässig, Name: Glas, Normalglas-50% durchlässig; Glas, Normalglas-50% durchlässig, Participates in Collision Detection: yes

# IfcWallStandardCase: _SIWH - Beton, Stahlbeton 200, A-Wand034
In: Erdgeschoss
Classification: Wand (Archicad Klassifizierung); Material: _SIWH - Beton, Stahlbeton 0.2 m
Pset_WallCommon - FireRating: -; IsExternal: yes; LoadBearing: yes
Pset_FireRatingProperties - FireResistanceRating: -
AC_Pset_RenovationAndPhasing - Renovation Status: Existing
Material Properties - _SIWH - Beton, Stahlbeton, ThermalConductivity: 1.35; _SIWH - Beton, Stahlbeton, SpecificHeatCapacity: 1000 J/kg/K; _SIWH - Beton, Stahlbeton, MassDensity: 2000 kg/m3; _SIWH - Beton, Stahlbeton, Embodied Energy: 0.78 (MJ/kg); _SIWH - Beton, Stahlbeton, Embodied Carbon: 0.113 (kgCO₂/kg); _SIWH - Beton, Stahlbeton, Name: _SIWH - Beton, Stahlbeton; _SIWH - Beton, Stahlbeton, Participates in Collision Detection: yes

# IfcWallStandardCase: _SIWH - Beton, Stahlbeton 240 (2)
In: Erdgeschoss
Classification: Wand (Archicad Klassifizierung); Material: _SIWH - Beton, Stahlbeton 0.24 m
Pset_WallCommon - FireRating: -; IsExternal: yes; LoadBearing: yes
Pset_FireRatingProperties - FireResistanceRating: -
AC_Pset_RenovationAndPhasing - Renovation Status: Existing
Material Properties - _SIWH - Beton, Stahlbeton, ThermalConductivity: 1.35; _SIWH - Beton, Stahlbeton, SpecificHeatCapacity: 1000 J/kg/K; _SIWH - Beton, Stahlbeton, MassDensity: 2000 kg/m3; _SIWH - Beton, Stahlbeton, Embodied Energy: 0.78 (MJ/kg); _SIWH - Beton, Stahlbeton, Embodied Carbon: 0.113 (kgCO₂/kg); _SIWH - Beton, Stahlbeton, Name: _SIWH - Beton, Stahlbeton; _SIWH - Beton, Stahlbeton, Participates in Collision Detection: yes
Name
A-Wand052
A-Wand053

# IfcWallStandardCase: _SIWH - Dämmung, weich Mineralwolle 180, A-Wand066
In: Staffelgeschoss
Classification: Wand (Archicad Klassifizierung); Material: _SIWH - Dämmung, weich Mineralwolle 0.18 m
Material Properties - _SIWH - Dämmung, weich Mineralwolle, ThermalConductivity: 0.037; _SIWH - Dämmung, weich Mineralwolle, SpecificHeatCapacity: 840 J/kg/K; _SIWH - Dämmung, weich Mineralwolle, MassDensity: 40 kg/m3; _SIWH - Dämmung, weich Mineralwolle, Embodied Energy: 14.3 (MJ/kg); _SIWH - Dämmung, weich Mineralwolle, Embodied Carbon: 1.08 (kgCO₂/kg); _SIWH - Dämmung, weich Mineralwolle, Name: _SIWH - Dämmung, weich Mineralwolle; _SIWH - Dämmung, weich Mineralwolle, Participates in Collision Detection: yes
AC_Pset_RenovationAndPhasing - Renovation Status: Existing
Pset_FireRatingProperties - FireResistanceRating: -
Pset_WallCommon - FireRating: -; IsExternal: yes; LoadBearing: yes

# IfcWallStandardCase: _SIWH - Dämmung, weich Mineralwolle, hohe Priorität 180, A-Wand065
In: Staffelgeschoss
Classification: Wand (Archicad Klassifizierung); Material: _SIWH - Dämmung, weich Mineralwolle, hohe Priorität 0.18 m
Pset_WallCommon - FireRating: -; IsExternal: yes; LoadBearing: yes
Pset_FireRatingProperties - FireResistanceRating: -
AC_Pset_RenovationAndPhasing - Renovation Status: Existing
Material Properties - _SIWH - Dämmung, weich Mineralwolle, hohe Priorität, ThermalConductivity: 0.037; _SIWH - Dämmung, weich Mineralwolle, hohe Priorität, SpecificHeatCapacity: 840 J/kg/K; _SIWH - Dämmung, weich Mineralwolle, hohe Priorität, MassDensity: 40 kg/m3; _SIWH - Dämmung, weich Mineralwolle, hohe Priorität, Embodied Energy: 14.3 (MJ/kg); _SIWH - Dämmung, weich Mineralwolle, hohe Priorität, Embodied Carbon: 1.08 (kgCO₂/kg); _SIWH - Dämmung, weich Mineralwolle, hohe Priorität, Name: _SIWH - Dämmung, weich Mineralwolle, hohe Priorität; _SIWH - Dämmung, weich Mineralwolle, hohe Priorität, Participates in Collision Detection: yes

# IfcWallStandardCase: _SIWH - Glas, Normalglas 30 (2)
In: Staffelgeschoss
Type - ElementType: PARTITIONING; PredefinedType: USERDEFINED
Classification: Trennwand (Archicad Klassifizierung); Material: _SIWH - Glas, Normalglas 0.03 m
Pset_WallCommon - FireRating: -
Pset_FireRatingProperties - FireResistanceRating: -
AC_Pset_RenovationAndPhasing - Renovation Status: Existing
Material Properties - _SIWH - Glas, Normalglas, ThermalConductivity: 1.4; _SIWH - Glas, Normalglas, SpecificHeatCapacity: 750 J/kg/K; _SIWH - Glas, Normalglas, MassDensity: 2200 kg/m3; _SIWH - Glas, Normalglas, Embodied Energy: 0.85 (MJ/kg); _SIWH - Glas, Normalglas, Embodied Carbon: 0.02 (kgCO₂/kg); _SIWH - Glas, Normalglas, Name: _SIWH - Glas, Normalglas; _SIWH - Glas, Normalglas, Participates in Collision Detection: yes
Name
L-Wand046
L-Wand047

# IfcWallStandardCase: _SIWH - MW Kalksandstein, nichttragend 120, I-Wand044
In: Staffelgeschoss
Classification: Wand (Archicad Klassifizierung); Material: _SIWH - MW Kalksandstein, nichttragend 0.12 m
Pset_WallCommon - FireRating: -; IsExternal: no; LoadBearing: no
Pset_FireRatingProperties - FireResistanceRating: -
AC_Pset_RenovationAndPhasing - Renovation Status: Existing
Material Properties - _SIWH - MW Kalksandstein, nichttragend, ThermalConductivity: 0.93; _SIWH - MW Kalksandstein, nichttragend, SpecificHeatCapacity: 840 J/kg/K; _SIWH - MW Kalksandstein, nichttragend, MassDensity: 1800 kg/m3; _SIWH - MW Kalksandstein, nichttragend, Embodied Energy: 1.2 (MJ/kg); _SIWH - MW Kalksandstein, nichttragend, Embodied Carbon: 0.07 (kgCO₂/kg); _SIWH - MW Kalksandstein, nichttragend, Name: _SIWH - MW Kalksandstein, nichttragend; _SIWH - MW Kalksandstein, nichttragend, Participates in Collision Detection: yes

# IfcWallStandardCase: _SIWH - WA | Perimeterdämmung 8 | 8cm 80, A-Wand029
In: Kellergeschoss
Classification: Wand (Archicad Klassifizierung); Material: _SIWH - Dämmung, Perimeterdämmung 0.08 m
Pset_FireRatingProperties - FireResistanceRating: -
AC_Pset_RenovationAndPhasing - Renovation Status: Existing
Pset_WallCommon - FireRating: -; IsExternal: yes; LoadBearing: yes
Material Properties - _SIWH - Dämmung, Perimeterdämmung, ThermalConductivity: 0.046; _SIWH - Dämmung, Perimeterdämmung, SpecificHeatCapacity: 900 J/kg/K; _SIWH - Dämmung, Perimeterdämmung, MassDensity: 151.33 kg/m3; _SIWH - Dämmung, Perimeterdämmung, Embodied Energy: 13.5 (MJ/kg); _SIWH - Dämmung, Perimeterdämmung, Embodied Carbon: 0.9 (kgCO₂/kg); _SIWH - Dämmung, Perimeterdämmung, Name: _SIWH - Dämmung, Perimeterdämmung; _SIWH - Dämmung, Perimeterdämmung, Participates in Collision Detection: yes

# IfcWallStandardCase: _SIWH - WA | Stb. 20+WD 18 | 38cm 380 (6)
Classification: Wand (Archicad Klassifizierung); Material: _SIWH - Dämmung, weich Mineralwolle 0.18 m, _SIWH - Beton, Stahlbeton 0.2 m
Pset_WallCommon - FireRating: -; IsExternal: yes; LoadBearing: yes
AC_Pset_RenovationAndPhasing - Renovation Status: Existing
Material Properties - _SIWH - Dämmung, weich Mineralwolle, ThermalConductivity: 0.037; _SIWH - Dämmung, weich Mineralwolle, SpecificHeatCapacity: 840 J/kg/K; _SIWH - Dämmung, weich Mineralwolle, MassDensity: 40 kg/m3; _SIWH - Dämmung, weich Mineralwolle, Embodied Energy: 14.3 (MJ/kg); _SIWH - Dämmung, weich Mineralwolle, Embodied Carbon: 1.08 (kgCO₂/kg); _SIWH - Dämmung, weich Mineralwolle, Name: _SIWH - Dämmung, weich Mineralwolle; _SIWH - Dämmung, weich Mineralwolle, Participates in Collision Detection: yes; _SIWH - Beton, Stahlbeton, ThermalConductivity: 1.35; _SIWH - Beton, Stahlbeton, SpecificHeatCapacity: 1000 J/kg/K; _SIWH - Beton, Stahlbeton, MassDensity: 2000 kg/m3; _SIWH - Beton, Stahlbeton, Embodied Energy: 0.78 (MJ/kg); _SIWH - Beton, Stahlbeton, Embodied Carbon: 0.113 (kgCO₂/kg); _SIWH - Beton, Stahlbeton, Name: _SIWH - Beton, Stahlbeton; _SIWH - Beton, Stahlbeton, Participates in Collision Detection: yes
Pset_FireRatingProperties - FireResistanceRating: -
Name | In
A-Wand021 | Erdgeschoss
A-Wand051 | Staffelgeschoss
A-Wand050 | Staffelgeschoss
A-Wand049 | Staffelgeschoss
A-Wand047 | Staffelgeschoss
A-Wand048 | Staffelgeschoss

# IfcWallStandardCase: _SIWH - WA | Stb. 20+WD 18+LS 2+Verblender 11,5 | 51,5cm 515 (5)
Classification: Wand (Archicad Klassifizierung); Material: _SIWH - MW Vormauerziegel 0.115 m, _SIWH - Luftschicht vertikal 0.02 m, _SIWH - Dämmung, weich Mineralwolle 0.18 m, _SIWH - Beton, Stahlbeton 0.2 m
AC_Pset_RenovationAndPhasing - Renovation Status: Existing
Pset_WallCommon - FireRating: -; IsExternal: yes; LoadBearing: yes
Pset_FireRatingProperties - FireResistanceRating: -
Material Properties - _SIWH - MW Vormauerziegel, ThermalConductivity: 0.109; _SIWH - MW Vormauerziegel, SpecificHeatCapacity: 920 J/kg/K; _SIWH - MW Vormauerziegel, MassDensity: 600 kg/m3; _SIWH - MW Vormauerziegel, Embodied Energy: 6 (MJ/kg); _SIWH - MW Vormauerziegel, Embodied Carbon: 0.48 (kgCO₂/kg); _SIWH - MW Vormauerziegel, Name: _SIWH - MW Vormauerziegel; _SIWH - MW Vormauerziegel, Participates in Collision Detection: yes; _SIWH - Luftschicht vertikal, ThermalConductivity: 0.16; _SIWH - Luftschicht vertikal, SpecificHeatCapacity: 1008 J/kg/K; _SIWH - Luftschicht vertikal, MassDensity: 1.2 kg/m3; _SIWH - Luftschicht vertikal, Embodied Energy: 0 (MJ/kg); _SIWH - Luftschicht vertikal, Embodied Carbon: 0 (kgCO₂/kg); _SIWH - Luftschicht vertikal, Name: _SIWH - Luftschicht vertikal; _SIWH - Luftschicht vertikal, Participates in Collision Detection: no; _SIWH - Dämmung, weich Mineralwolle, ThermalConductivity: 0.037; _SIWH - Dämmung, weich Mineralwolle, SpecificHeatCapacity: 840 J/kg/K; _SIWH - Dämmung, weich Mineralwolle, MassDensity: 40 kg/m3; _SIWH - Dämmung, weich Mineralwolle, Embodied Energy: 14.3 (MJ/kg); _SIWH - Dämmung, weich Mineralwolle, Embodied Carbon: 1.08 (kgCO₂/kg); _SIWH - Dämmung, weich Mineralwolle, Name: _SIWH - Dämmung, weich Mineralwolle; _SIWH - Dämmung, weich Mineralwolle, Participates in Collision Detection: yes; _SIWH - Beton, Stahlbeton, ThermalConductivity: 1.35; _SIWH - Beton, Stahlbeton, SpecificHeatCapacity: 1000 J/kg/K; _SIWH - Beton, Stahlbeton, MassDensity: 2000 kg/m3; _SIWH - Beton, Stahlbeton, Embodied Energy: 0.78 (MJ/kg); _SIWH - Beton, Stahlbeton, Embodied Carbon: 0.113 (kgCO₂/kg); _SIWH - Beton, Stahlbeton, Name: _SIWH - Beton, Stahlbeton; _SIWH - Beton, Stahlbeton, Participates in Collision Detection: yes
Name | In
A-Wand001 | Erdgeschoss
A-Wand003 | Erdgeschoss
A-Wand044 | Staffelgeschoss
A-Wand045 | Staffelgeschoss
A-Wand046 | Staffelgeschoss

# IfcWallStandardCase: _SIWH - WA | Stb. 24+WD 18 | 42cm 420 (6)
In: Erdgeschoss
Classification: Wand (Archicad Klassifizierung); Material: _SIWH - Dämmung, weich Mineralwolle 0.18 m, _SIWH - Beton, Stahlbeton 0.24 m
Pset_WallCommon - FireRating: -; IsExternal: yes; LoadBearing: yes
Pset_FireRatingProperties - FireResistanceRating: -
Material Properties - _SIWH - Dämmung, weich Mineralwolle, ThermalConductivity: 0.037; _SIWH - Dämmung, weich Mineralwolle, SpecificHeatCapacity: 840 J/kg/K; _SIWH - Dämmung, weich Mineralwolle, MassDensity: 40 kg/m3; _SIWH - Dämmung, weich Mineralwolle, Embodied Energy: 14.3 (MJ/kg); _SIWH - Dämmung, weich Mineralwolle, Embodied Carbon: 1.08 (kgCO₂/kg); _SIWH - Dämmung, weich Mineralwolle, Name: _SIWH - Dämmung, weich Mineralwolle; _SIWH - Dämmung, weich Mineralwolle, Participates in Collision Detection: yes; _SIWH - Beton, Stahlbeton, ThermalConductivity: 1.35; _SIWH - Beton, Stahlbeton, SpecificHeatCapacity: 1000 J/kg/K; _SIWH - Beton, Stahlbeton, MassDensity: 2000 kg/m3; _SIWH - Beton, Stahlbeton, Embodied Energy: 0.78 (MJ/kg); _SIWH - Beton, Stahlbeton, Embodied Carbon: 0.113 (kgCO₂/kg); _SIWH - Beton, Stahlbeton, Name: _SIWH - Beton, Stahlbeton; _SIWH - Beton, Stahlbeton, Participates in Collision Detection: yes
AC_Pset_RenovationAndPhasing - Renovation Status: Existing
Name
A-Wand011
A-Wand008
A-Wand007
A-Wand014
A-Wand015
A-Wand012

# IfcWallStandardCase: _SIWH - WA | Stb. 24+WD 18+LS 2+Verblender 11,5 | 55,5cm 555 (6)
In: Erdgeschoss
Classification: Wand (Archicad Klassifizierung); Material: _SIWH - MW Vormauerziegel 0.115 m, _SIWH - Luftschicht vertikal 0.02 m, _SIWH - Dämmung, weich Mineralwolle 0.18 m, _SIWH - Beton, Stahlbeton 0.24 m
Pset_FireRatingProperties - FireResistanceRating: -
Pset_WallCommon - FireRating: -; IsExternal: yes; LoadBearing: yes
AC_Pset_RenovationAndPhasing - Renovation Status: Existing
Material Properties - _SIWH - MW Vormauerziegel, ThermalConductivity: 0.109; _SIWH - MW Vormauerziegel, SpecificHeatCapacity: 920 J/kg/K; _SIWH - MW Vormauerziegel, MassDensity: 600 kg/m3; _SIWH - MW Vormauerziegel, Embodied Energy: 6 (MJ/kg); _SIWH - MW Vormauerziegel, Embodied Carbon: 0.48 (kgCO₂/kg); _SIWH - MW Vormauerziegel, Name: _SIWH - MW Vormauerziegel; _SIWH - MW Vormauerziegel, Participates in Collision Detection: yes; _SIWH - Luftschicht vertikal, ThermalConductivity: 0.16; _SIWH - Luftschicht vertikal, SpecificHeatCapacity: 1008 J/kg/K; _SIWH - Luftschicht vertikal, MassDensity: 1.2 kg/m3; _SIWH - Luftschicht vertikal, Embodied Energy: 0 (MJ/kg); _SIWH - Luftschicht vertikal, Embodied Carbon: 0 (kgCO₂/kg); _SIWH - Luftschicht vertikal, Name: _SIWH - Luftschicht vertikal; _SIWH - Luftschicht vertikal, Participates in Collision Detection: no; _SIWH - Dämmung, weich Mineralwolle, ThermalConductivity: 0.037; _SIWH - Dämmung, weich Mineralwolle, SpecificHeatCapacity: 840 J/kg/K; _SIWH - Dämmung, weich Mineralwolle, MassDensity: 40 kg/m3; _SIWH - Dämmung, weich Mineralwolle, Embodied Energy: 14.3 (MJ/kg); _SIWH - Dämmung, weich Mineralwolle, Embodied Carbon: 1.08 (kgCO₂/kg); _SIWH - Dämmung, weich Mineralwolle, Name: _SIWH - Dämmung, weich Mineralwolle; _SIWH - Dämmung, weich Mineralwolle, Participates in Collision Detection: yes; _SIWH - Beton, Stahlbeton, ThermalConductivity: 1.35; _SIWH - Beton, Stahlbeton, SpecificHeatCapacity: 1000 J/kg/K; _SIWH - Beton, Stahlbeton, MassDensity: 2000 kg/m3; _SIWH - Beton, Stahlbeton, Embodied Energy: 0.78 (MJ/kg); _SIWH - Beton, Stahlbeton, Embodied Carbon: 0.113 (kgCO₂/kg); _SIWH - Beton, Stahlbeton, Name: _SIWH - Beton, Stahlbeton; _SIWH - Beton, Stahlbeton, Participates in Collision Detection: yes
Name
A-Wand042
A-Wand026
A-Wand027
A-Wand040
A-Wand004
A-Wand028

# IfcWallStandardCase: _SIWH - WA | Stb. 30 | 30cm 300 (5)
In: Kellergeschoss
Classification: Wand (Archicad Klassifizierung); Material: _SIWH - Beton, Stahlbeton 0.3 m
Pset_FireRatingProperties - FireResistanceRating: -
AC_Pset_RenovationAndPhasing - Renovation Status: Existing
Material Properties - _SIWH - Beton, Stahlbeton, ThermalConductivity: 1.35; _SIWH - Beton, Stahlbeton, SpecificHeatCapacity: 1000 J/kg/K; _SIWH - Beton, Stahlbeton, MassDensity: 2000 kg/m3; _SIWH - Beton, Stahlbeton, Embodied Energy: 0.78 (MJ/kg); _SIWH - Beton, Stahlbeton, Embodied Carbon: 0.113 (kgCO₂/kg); _SIWH - Beton, Stahlbeton, Name: _SIWH - Beton, Stahlbeton; _SIWH - Beton, Stahlbeton, Participates in Collision Detection: yes
Pset_WallCommon - FireRating: -; IsExternal: yes; LoadBearing: yes
Name
A-Wand000
A-Wand039
A-Wand002
A-Wand025
A-Wand024

# IfcWallStandardCase: _SIWH - WA | Stb. 30+WD 18+LS 2+Verblender 11,5 | 61,5 615 (2)
In: Erdgeschoss
Classification: Wand (Archicad Klassifizierung); Material: _SIWH - MW Vormauerziegel 0.115 m, _SIWH - Luftschicht vertikal 0.02 m, _SIWH - Dämmung, weich Mineralwolle 0.18 m, _SIWH - Beton, Stahlbeton 0.3 m
Pset_WallCommon - FireRating: -; IsExternal: yes; LoadBearing: yes
Pset_FireRatingProperties - FireResistanceRating: -
AC_Pset_RenovationAndPhasing - Renovation Status: Existing
Material Properties - _SIWH - MW Vormauerziegel, ThermalConductivity: 0.109; _SIWH - MW Vormauerziegel, SpecificHeatCapacity: 920 J/kg/K; _SIWH - MW Vormauerziegel, MassDensity: 600 kg/m3; _SIWH - MW Vormauerziegel, Embodied Energy: 6 (MJ/kg); _SIWH - MW Vormauerziegel, Embodied Carbon: 0.48 (kgCO₂/kg); _SIWH - MW Vormauerziegel, Name: _SIWH - MW Vormauerziegel; _SIWH - MW Vormauerziegel, Participates in Collision Detection: yes; _SIWH - Luftschicht vertikal, ThermalConductivity: 0.16; _SIWH - Luftschicht vertikal, SpecificHeatCapacity: 1008 J/kg/K; _SIWH - Luftschicht vertikal, MassDensity: 1.2 kg/m3; _SIWH - Luftschicht vertikal, Embodied Energy: 0 (MJ/kg); _SIWH - Luftschicht vertikal, Embodied Carbon: 0 (kgCO₂/kg); _SIWH - Luftschicht vertikal, Name: _SIWH - Luftschicht vertikal; _SIWH - Luftschicht vertikal, Participates in Collision Detection: no; _SIWH - Dämmung, weich Mineralwolle, ThermalConductivity: 0.037; _SIWH - Dämmung, weich Mineralwolle, SpecificHeatCapacity: 840 J/kg/K; _SIWH - Dämmung, weich Mineralwolle, MassDensity: 40 kg/m3; _SIWH - Dämmung, weich Mineralwolle, Embodied Energy: 14.3 (MJ/kg); _SIWH - Dämmung, weich Mineralwolle, Embodied Carbon: 1.08 (kgCO₂/kg); _SIWH - Dämmung, weich Mineralwolle, Name: _SIWH - Dämmung, weich Mineralwolle; _SIWH - Dämmung, weich Mineralwolle, Participates in Collision Detection: yes; _SIWH - Beton, Stahlbeton, ThermalConductivity: 1.35; _SIWH - Beton, Stahlbeton, SpecificHeatCapacity: 1000 J/kg/K; _SIWH - Beton, Stahlbeton, MassDensity: 2000 kg/m3; _SIWH - Beton, Stahlbeton, Embodied Energy: 0.78 (MJ/kg); _SIWH - Beton, Stahlbeton, Embodied Carbon: 0.113 (kgCO₂/kg); _SIWH - Beton, Stahlbeton, Name: _SIWH - Beton, Stahlbeton; _SIWH - Beton, Stahlbeton, Participates in Collision Detection: yes
Name
A-Wand005
A-Wand023

# IfcWallStandardCase: _SIWH - WI | GK 2-lagig | 12,5cm 125 (5)
Classification: Wand (Archicad Klassifizierung); Material: _SIWH - Gipskarton 0.0125 m, _SIWH - Gipskarton 0.0125 m, _SIWH - Dämmung, weich Mineralwolle 0.075 m, _SIWH - Gipskarton 0.0125 m, _SIWH - Gipskarton 0.0125 m
Pset_WallCommon - FireRating: -; IsExternal: no; LoadBearing: no
Pset_FireRatingProperties - FireResistanceRating: -
AC_Pset_RenovationAndPhasing - Renovation Status: Existing
Material Properties - _SIWH - Gipskarton, ThermalConductivity: 0.25; _SIWH - Gipskarton, SpecificHeatCapacity: 1000 J/kg/K; _SIWH - Gipskarton, MassDensity: 900 kg/m3; _SIWH - Gipskarton, Embodied Energy: 6.75 (MJ/kg); _SIWH - Gipskarton, Embodied Carbon: 0.39 (kgCO₂/kg); _SIWH - Gipskarton, Name: _SIWH - Gipskarton; _SIWH - Gipskarton, Participates in Collision Detection: yes; _SIWH - Dämmung, weich Mineralwolle, ThermalConductivity: 0.037; _SIWH - Dämmung, weich Mineralwolle, SpecificHeatCapacity: 840 J/kg/K; _SIWH - Dämmung, weich Mineralwolle, MassDensity: 40 kg/m3; _SIWH - Dämmung, weich Mineralwolle, Embodied Energy: 14.3 (MJ/kg); _SIWH - Dämmung, weich Mineralwolle, Embodied Carbon: 1.08 (kgCO₂/kg); _SIWH - Dämmung, weich Mineralwolle, Name: _SIWH - Dämmung, weich Mineralwolle; _SIWH - Dämmung, weich Mineralwolle, Participates in Collision Detection: yes
Name | In
I-Wand037 | Erdgeschoss
I-Wand038 | Erdgeschoss
I-Wand043 | Erdgeschoss
I-Wand040 | Staffelgeschoss
I-Wand041 | Staffelgeschoss

# IfcWallStandardCase: _SIWH - WI | GK 2-lagig | 15cm 150, I-Wand042
In: Erdgeschoss
Classification: Wand (Archicad Klassifizierung); Material: _SIWH - Gipskarton 0.0125 m, _SIWH - Gipskarton 0.0125 m, _SIWH - Dämmung, weich Mineralwolle 0.1 m, _SIWH - Gipskarton 0.0125 m, _SIWH - Gipskarton 0.0125 m
Pset_WallCommon - FireRating: -; IsExternal: no; LoadBearing: no
Pset_FireRatingProperties - FireResistanceRating: -
AC_Pset_RenovationAndPhasing - Renovation Status: Existing
Material Properties - _SIWH - Gipskarton, ThermalConductivity: 0.25; _SIWH - Gipskarton, SpecificHeatCapacity: 1000 J/kg/K; _SIWH - Gipskarton, MassDensity: 900 kg/m3; _SIWH - Gipskarton, Embodied Energy: 6.75 (MJ/kg); _SIWH - Gipskarton, Embodied Carbon: 0.39 (kgCO₂/kg); _SIWH - Gipskarton, Name: _SIWH - Gipskarton; _SIWH - Gipskarton, Participates in Collision Detection: yes; _SIWH - Dämmung, weich Mineralwolle, ThermalConductivity: 0.037; _SIWH - Dämmung, weich Mineralwolle, SpecificHeatCapacity: 840 J/kg/K; _SIWH - Dämmung, weich Mineralwolle, MassDensity: 40 kg/m3; _SIWH - Dämmung, weich Mineralwolle, Embodied Energy: 14.3 (MJ/kg); _SIWH - Dämmung, weich Mineralwolle, Embodied Carbon: 1.08 (kgCO₂/kg); _SIWH - Dämmung, weich Mineralwolle, Name: _SIWH - Dämmung, weich Mineralwolle; _SIWH - Dämmung, weich Mineralwolle, Participates in Collision Detection: yes

# IfcWallStandardCase: _SIWH - WI | KS 17,5 | 17,5cm 175 (18)
Classification: Wand (Archicad Klassifizierung); Material: _SIWH - MW Kalksandstein 0.175 m
Pset_WallCommon - FireRating: -; IsExternal: no; LoadBearing: yes
Pset_FireRatingProperties - FireResistanceRating: -
AC_Pset_RenovationAndPhasing - Renovation Status: Existing
Material Properties - _SIWH - MW Kalksandstein, ThermalConductivity: 0.93; _SIWH - MW Kalksandstein, SpecificHeatCapacity: 840 J/kg/K; _SIWH - MW Kalksandstein, MassDensity: 1800 kg/m3; _SIWH - MW Kalksandstein, Embodied Energy: 1.2 (MJ/kg); _SIWH - MW Kalksandstein, Embodied Carbon: 0.07 (kgCO₂/kg); _SIWH - MW Kalksandstein, Name: _SIWH - MW Kalksandstein; _SIWH - MW Kalksandstein, Participates in Collision Detection: yes
Name | In
I-Wand023 | Kellergeschoss
I-Wand025 | Kellergeschoss
I-Wand027 | Kellergeschoss
I-Wand028 | Kellergeschoss
I-Wand033 | Kellergeschoss
I-Wand031 | Kellergeschoss
I-Wand026 | Erdgeschoss
I-Wand029 | Erdgeschoss
I-Wand003 | Erdgeschoss
I-Wand004 | Erdgeschoss
I-Wand030 | Erdgeschoss
I-Wand032 | Erdgeschoss
I-Wand015 | Staffelgeschoss
I-Wand016 | Staffelgeschoss
I-Wand017 | Staffelgeschoss
I-Wand018 | Staffelgeschoss
I-Wand019 | Staffelgeschoss
I-Wand022 | Staffelgeschoss

# IfcWallStandardCase: _SIWH - WI | KS 20 nichttragend | 20cm 200, I-Wand039
In: Erdgeschoss
Classification: Wand (Archicad Klassifizierung); Material: _SIWH - MW Kalksandstein, nichttragend 0.2 m
Pset_WallCommon - FireRating: -; IsExternal: no; LoadBearing: no
Pset_FireRatingProperties - FireResistanceRating: -
AC_Pset_RenovationAndPhasing - Renovation Status: Existing
Material Properties - _SIWH - MW Kalksandstein, nichttragend, ThermalConductivity: 0.93; _SIWH - MW Kalksandstein, nichttragend, SpecificHeatCapacity: 840 J/kg/K; _SIWH - MW Kalksandstein, nichttragend, MassDensity: 1800 kg/m3; _SIWH - MW Kalksandstein, nichttragend, Embodied Energy: 1.2 (MJ/kg); _SIWH - MW Kalksandstein, nichttragend, Embodied Carbon: 0.07 (kgCO₂/kg); _SIWH - MW Kalksandstein, nichttragend, Name: _SIWH - MW Kalksandstein, nichttragend; _SIWH - MW Kalksandstein, nichttragend, Participates in Collision Detection: yes

# IfcWallStandardCase: _SIWH - WI | Stb. 12 | 12cm 120, I-Wand024
In: Erdgeschoss
Classification: Wand (Archicad Klassifizierung); Material: _SIWH - Beton, Stahlbeton 0.12 m
Pset_WallCommon - FireRating: -; IsExternal: no; LoadBearing: yes
AC_Pset_RenovationAndPhasing - Renovation Status: Existing
Material Properties - _SIWH - Beton, Stahlbeton, ThermalConductivity: 1.35; _SIWH - Beton, Stahlbeton, SpecificHeatCapacity: 1000 J/kg/K; _SIWH - Beton, Stahlbeton, MassDensity: 2000 kg/m3; _SIWH - Beton, Stahlbeton, Embodied Energy: 0.78 (MJ/kg); _SIWH - Beton, Stahlbeton, Embodied Carbon: 0.113 (kgCO₂/kg); _SIWH - Beton, Stahlbeton, Name: _SIWH - Beton, Stahlbeton; _SIWH - Beton, Stahlbeton, Participates in Collision Detection: yes
Pset_FireRatingProperties - FireResistanceRating: -

# IfcWallStandardCase: _SIWH - WI | Stb. 20 | 20cm 200 (7)
Classification: Wand (Archicad Klassifizierung); Material: _SIWH - Beton, Stahlbeton 0.2 m
Pset_WallCommon - FireRating: -; IsExternal: no; LoadBearing: yes
Pset_FireRatingProperties - FireResistanceRating: -
AC_Pset_RenovationAndPhasing - Renovation Status: Existing
Material Properties - _SIWH - Beton, Stahlbeton, ThermalConductivity: 1.35; _SIWH - Beton, Stahlbeton, SpecificHeatCapacity: 1000 J/kg/K; _SIWH - Beton, Stahlbeton, MassDensity: 2000 kg/m3; _SIWH - Beton, Stahlbeton, Embodied Energy: 0.78 (MJ/kg); _SIWH - Beton, Stahlbeton, Embodied Carbon: 0.113 (kgCO₂/kg); _SIWH - Beton, Stahlbeton, Name: _SIWH - Beton, Stahlbeton; _SIWH - Beton, Stahlbeton, Participates in Collision Detection: yes
Name | In
I-Wand007 | Erdgeschoss
I-Wand010 | Erdgeschoss
I-Wand008 | Erdgeschoss
I-Wand011 | Erdgeschoss
I-Wand012 | Erdgeschoss
I-Wand014 | Staffelgeschoss
I-Wand009 | Staffelgeschoss

# IfcWallStandardCase: _SIWH - WI | Stb. 24 | 24cm 240 (3)
In: Erdgeschoss
Classification: Wand (Archicad Klassifizierung); Material: _SIWH - Beton, Stahlbeton 0.24 m
Pset_FireRatingProperties - FireResistanceRating: -
Pset_WallCommon - FireRating: -; LoadBearing: yes
AC_Pset_RenovationAndPhasing - Renovation Status: Existing
Material Properties - _SIWH - Beton, Stahlbeton, ThermalConductivity: 1.35; _SIWH - Beton, Stahlbeton, SpecificHeatCapacity: 1000 J/kg/K; _SIWH - Beton, Stahlbeton, MassDensity: 2000 kg/m3; _SIWH - Beton, Stahlbeton, Embodied Energy: 0.78 (MJ/kg); _SIWH - Beton, Stahlbeton, Embodied Carbon: 0.113 (kgCO₂/kg); _SIWH - Beton, Stahlbeton, Name: _SIWH - Beton, Stahlbeton; _SIWH - Beton, Stahlbeton, Participates in Collision Detection: yes
Name | IsExternal
I-Wand005 | no
A-Wand006 | yes
I-Wand006 | no

# IfcWallStandardCase: _SIWH - WI | Vorsatz-GK 2-lagig | 12,5cm 125 (4)
In: Erdgeschoss
Type - PredefinedType: PLUMBINGWALL
Classification: Vorwand / Installationswand (Archicad Klassifizierung); Material: _SIWH - Gipskarton 0.0125 m, _SIWH - Gipskarton 0.0125 m, _SIWH - Installationswand, raumhoch 0.1 m
Pset_WallCommon - FireRating: -; IsExternal: no; LoadBearing: no
AC_Pset_RenovationAndPhasing - Renovation Status: Existing
Pset_FireRatingProperties - FireResistanceRating: -
Material Properties - _SIWH - Gipskarton, ThermalConductivity: 0.25; _SIWH - Gipskarton, SpecificHeatCapacity: 1000 J/kg/K; _SIWH - Gipskarton, MassDensity: 900 kg/m3; _SIWH - Gipskarton, Embodied Energy: 6.75 (MJ/kg); _SIWH - Gipskarton, Embodied Carbon: 0.39 (kgCO₂/kg); _SIWH - Gipskarton, Name: _SIWH - Gipskarton; _SIWH - Gipskarton, Participates in Collision Detection: yes; _SIWH - Installationswand, raumhoch, ThermalConductivity: 0.16; _SIWH - Installationswand, raumhoch, SpecificHeatCapacity: 1008 J/kg/K; _SIWH - Installationswand, raumhoch, MassDensity: 1.2 kg/m3; _SIWH - Installationswand, raumhoch, Embodied Energy: 0 (MJ/kg); _SIWH - Installationswand, raumhoch, Embodied Carbon: 0 (kgCO₂/kg); _SIWH - Installationswand, raumhoch, Name: _SIWH - Installationswand, raumhoch; _SIWH - Installationswand, raumhoch, Participates in Collision Detection: no
Name
L-Wand011
L-Wand010
L-Wand041
L-Wand035

# IfcWallStandardCase: _SIWH - WI | Vorsatz-GK 2-lagig | 14cm 140, L-Wand024
In: Erdgeschoss
Type - PredefinedType: PLUMBINGWALL
Classification: Vorwand / Installationswand (Archicad Klassifizierung); Material: _SIWH - Gipskarton 0.0125 m, _SIWH - Gipskarton 0.0125 m, _SIWH - Installationswand, raumhoch 0.115 m
Pset_WallCommon - FireRating: -; IsExternal: no; LoadBearing: no
Pset_FireRatingProperties - FireResistanceRating: -
AC_Pset_RenovationAndPhasing - Renovation Status: Existing
Material Properties - _SIWH - Gipskarton, ThermalConductivity: 0.25; _SIWH - Gipskarton, SpecificHeatCapacity: 1000 J/kg/K; _SIWH - Gipskarton, MassDensity: 900 kg/m3; _SIWH - Gipskarton, Embodied Energy: 6.75 (MJ/kg); _SIWH - Gipskarton, Embodied Carbon: 0.39 (kgCO₂/kg); _SIWH - Gipskarton, Name: _SIWH - Gipskarton; _SIWH - Gipskarton, Participates in Collision Detection: yes; _SIWH - Installationswand, raumhoch, ThermalConductivity: 0.16; _SIWH - Installationswand, raumhoch, SpecificHeatCapacity: 1008 J/kg/K; _SIWH - Installationswand, raumhoch, MassDensity: 1.2 kg/m3; _SIWH - Installationswand, raumhoch, Embodied Energy: 0 (MJ/kg); _SIWH - Installationswand, raumhoch, Embodied Carbon: 0 (kgCO₂/kg); _SIWH - Installationswand, raumhoch, Name: _SIWH - Installationswand, raumhoch; _SIWH - Installationswand, raumhoch, Participates in Collision Detection: no

# IfcWallStandardCase: _SIWH - WI | Vorsatz-GK 2-lagig | 15cm 150 (4)
Type - PredefinedType: PLUMBINGWALL
Classification: Vorwand / Installationswand (Archicad Klassifizierung); Material: _SIWH - Gipskarton 0.0125 m, _SIWH - Gipskarton 0.0125 m, _SIWH - Installationswand, raumhoch 0.1 m, _SIWH - Gipskarton 0.0125 m, _SIWH - Gipskarton 0.0125 m
AC_Pset_RenovationAndPhasing - Renovation Status: Existing
Material Properties - _SIWH - Gipskarton, ThermalConductivity: 0.25; _SIWH - Gipskarton, SpecificHeatCapacity: 1000 J/kg/K; _SIWH - Gipskarton, MassDensity: 900 kg/m3; _SIWH - Gipskarton, Embodied Energy: 6.75 (MJ/kg); _SIWH - Gipskarton, Embodied Carbon: 0.39 (kgCO₂/kg); _SIWH - Gipskarton, Name: _SIWH - Gipskarton; _SIWH - Gipskarton, Participates in Collision Detection: yes; _SIWH - Installationswand, raumhoch, ThermalConductivity: 0.16; _SIWH - Installationswand, raumhoch, SpecificHeatCapacity: 1008 J/kg/K; _SIWH - Installationswand, raumhoch, MassDensity: 1.2 kg/m3; _SIWH - Installationswand, raumhoch, Embodied Energy: 0 (MJ/kg); _SIWH - Installationswand, raumhoch, Embodied Carbon: 0 (kgCO₂/kg); _SIWH - Installationswand, raumhoch, Name: _SIWH - Installationswand, raumhoch; _SIWH - Installationswand, raumhoch, Participates in Collision Detection: no
Pset_FireRatingProperties - FireResistanceRating: -
Pset_WallCommon - FireRating: -; IsExternal: no; LoadBearing: no
Name | In
L-Wand019 | Erdgeschoss
L-Wand018 | Erdgeschoss
L-Wand049 | Staffelgeschoss
L-Wand048 | Staffelgeschoss

# IfcWallStandardCase: _SIWH - WI | Vorsatz-GK 2-lagig | 20cm 200 (3)
Type - PredefinedType: PLUMBINGWALL
Classification: Vorwand / Installationswand (Archicad Klassifizierung); Material: _SIWH - Gipskarton 0.0125 m, _SIWH - Gipskarton 0.0125 m, _SIWH - Installationswand, raumhoch 0.175 m
Pset_WallCommon - FireRating: -; IsExternal: no; LoadBearing: no
AC_Pset_RenovationAndPhasing - Renovation Status: Existing
Material Properties - _SIWH - Gipskarton, ThermalConductivity: 0.25; _SIWH - Gipskarton, SpecificHeatCapacity: 1000 J/kg/K; _SIWH - Gipskarton, MassDensity: 900 kg/m3; _SIWH - Gipskarton, Embodied Energy: 6.75 (MJ/kg); _SIWH - Gipskarton, Embodied Carbon: 0.39 (kgCO₂/kg); _SIWH - Gipskarton, Name: _SIWH - Gipskarton; _SIWH - Gipskarton, Participates in Collision Detection: yes; _SIWH - Installationswand, raumhoch, ThermalConductivity: 0.16; _SIWH - Installationswand, raumhoch, SpecificHeatCapacity: 1008 J/kg/K; _SIWH - Installationswand, raumhoch, MassDensity: 1.2 kg/m3; _SIWH - Installationswand, raumhoch, Embodied Energy: 0 (MJ/kg); _SIWH - Installationswand, raumhoch, Embodied Carbon: 0 (kgCO₂/kg); _SIWH - Installationswand, raumhoch, Name: _SIWH - Installationswand, raumhoch; _SIWH - Installationswand, raumhoch, Participates in Collision Detection: no
Pset_FireRatingProperties - FireResistanceRating: -
Name | In
L-Wand028 | Erdgeschoss
L-Wand022 | Staffelgeschoss
L-Wand023 | Staffelgeschoss

# IfcWallStandardCase: _SIWH - WI | Vorsatz-GK 2-lagig | 7,5cm 75 (26)
Type - PredefinedType: PLUMBINGWALL
Classification: Vorwand / Installationswand (Archicad Klassifizierung); Material: _SIWH - Gipskarton 0.0125 m, _SIWH - Gipskarton 0.0125 m, _SIWH - Installationswand, raumhoch 0.05 m
Pset_WallCommon - FireRating: -; IsExternal: no; LoadBearing: no
Pset_FireRatingProperties - FireResistanceRating: -
AC_Pset_RenovationAndPhasing - Renovation Status: Existing
Material Properties - _SIWH - Gipskarton, ThermalConductivity: 0.25; _SIWH - Gipskarton, SpecificHeatCapacity: 1000 J/kg/K; _SIWH - Gipskarton, MassDensity: 900 kg/m3; _SIWH - Gipskarton, Embodied Energy: 6.75 (MJ/kg); _SIWH - Gipskarton, Embodied Carbon: 0.39 (kgCO₂/kg); _SIWH - Gipskarton, Name: _SIWH - Gipskarton; _SIWH - Gipskarton, Participates in Collision Detection: yes; _SIWH - Installationswand, raumhoch, ThermalConductivity: 0.16; _SIWH - Installationswand, raumhoch, SpecificHeatCapacity: 1008 J/kg/K; _SIWH - Installationswand, raumhoch, MassDensity: 1.2 kg/m3; _SIWH - Installationswand, raumhoch, Embodied Energy: 0 (MJ/kg); _SIWH - Installationswand, raumhoch, Embodied Carbon: 0 (kgCO₂/kg); _SIWH - Installationswand, raumhoch, Name: _SIWH - Installationswand, raumhoch; _SIWH - Installationswand, raumhoch, Participates in Collision Detection: no
Name | In
L-Wand002 | Erdgeschoss
L-Wand009 | Erdgeschoss
L-Wand008 | Erdgeschoss
L-Wand015 | Erdgeschoss
L-Wand005 | Erdgeschoss
L-Wand007 | Erdgeschoss
L-Wand006 | Erdgeschoss
L-Wand000 | Erdgeschoss
L-Wand020 | Erdgeschoss
L-Wand004 | Erdgeschoss
L-Wand012 | Erdgeschoss
L-Wand034 | Erdgeschoss
L-Wand037 | Erdgeschoss
L-Wand003 | Erdgeschoss
L-Wand016 | Erdgeschoss
L-Wand013 | Erdgeschoss
L-Wand014 | Erdgeschoss
L-Wand001 | Erdgeschoss
L-Wand017 | Erdgeschoss
L-Wand021 | Staffelgeschoss
L-Wand029 | Staffelgeschoss
L-Wand031 | Staffelgeschoss
L-Wand030 | Staffelgeschoss
L-Wand032 | Staffelgeschoss
L-Wand038 | Staffelgeschoss
L-Wand042 | Staffelgeschoss

# IfcWindow: 1-Flügelfenster 22, Fenster-016
In: Kellergeschoss
Type - OperationType: SINGLE_PANEL; ParameterTakesPrecedence: no; Sizeable: no
OverallHeight: 0.625 m; OverallWidth: 1 m; Classification: Fenster (Archicad Klassifizierung)
Pset_WindowCommon - FireRating: -; SmokeStop: no
AC_Pset_RenovationAndPhasing - Renovation Status: Existing
Pset_FireRatingProperties - FireResistanceRating: -

# IfcWindow: Dachfenster Glaskuppel 03 26, Objekt-0097
In: Staffelgeschoss
Type - ParameterTakesPrecedence: no; Sizeable: no
Classification: Lichtkuppel (Archicad Klassifizierung)
Pset_WindowCommon - FireRating: -; SmokeStop: no; IsExternal: yes
Pset_FireRatingProperties - FireResistanceRating: -
AC_Pset_RenovationAndPhasing - Renovation Status: Existing

# IfcWindow: _SIWH - Beton, Stahlbeton 85 (4)
In: Staffelgeschoss
Type - ParameterTakesPrecedence: no; Sizeable: no
Classification: Lichtkuppel (Archicad Klassifizierung); Material: _SIWH - Beton, Stahlbeton
Pset_WindowCommon - FireRating: -; SmokeStop: no; IsExternal: yes
AC_Pset_RenovationAndPhasing - Renovation Status: Existing
Material Properties - _SIWH - Beton, Stahlbeton, ThermalConductivity: 1.35; _SIWH - Beton, Stahlbeton, SpecificHeatCapacity: 1000 J/kg/K; _SIWH - Beton, Stahlbeton, MassDensity: 2000 kg/m3; _SIWH - Beton, Stahlbeton, Embodied Energy: 0.78 (MJ/kg); _SIWH - Beton, Stahlbeton, Embodied Carbon: 0.113 (kgCO₂/kg); _SIWH - Beton, Stahlbeton, Name: _SIWH - Beton, Stahlbeton; _SIWH - Beton, Stahlbeton, Participates in Collision Detection: yes
Pset_FireRatingProperties - FireResistanceRating: -
Name
A-Wand064
A-Wand062
A-Wand061
A-Wand063
